VERSION 5.8 ;
BUSBITCHARS "[]" ;
DIVIDERCHAR "/" ;
UNITS
    DATABASE MICRONS 1000 ;
END UNITS

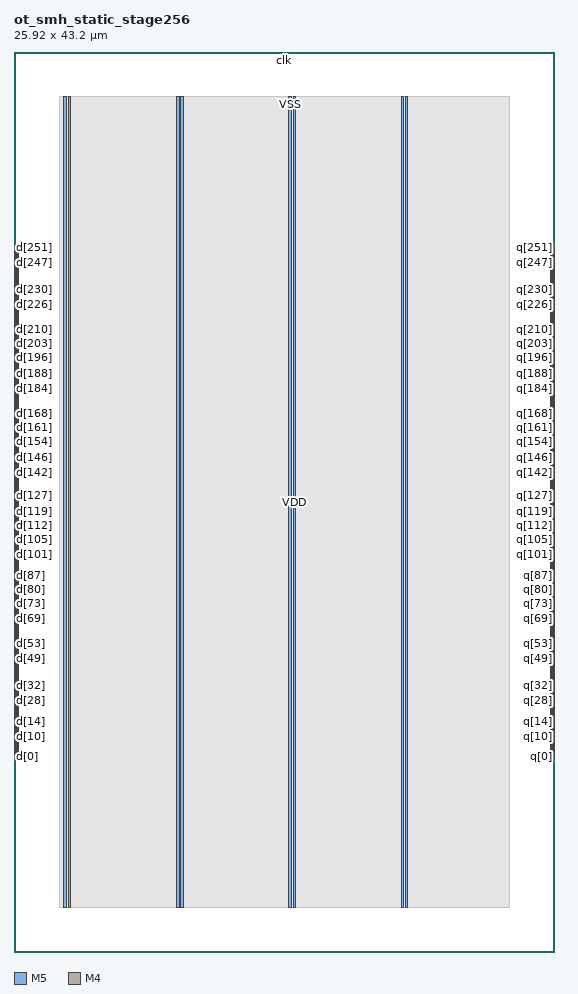
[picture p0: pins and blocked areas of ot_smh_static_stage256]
MACRO ot_smh_static_stage256
  FOREIGN ot_smh_static_stage256 0 0 ;
  CLASS BLOCK ;
  SIZE 25.92 BY 43.2 ;
  PIN clk
    DIRECTION INPUT ;
    USE SIGNAL ;
    PORT
      LAYER M5 ;
        RECT  12.96 43.008 12.984 43.2 ;
    END
  END clk
  PIN d[0]
    DIRECTION INPUT ;
    USE SIGNAL ;
    PORT
      LAYER M4 ;
        RECT  0 9.36 0.192 9.384 ;
    END
  END d[0]
  PIN d[100]
    DIRECTION INPUT ;
    USE SIGNAL ;
    PORT
      LAYER M4 ;
        RECT  0 18.96 0.192 18.984 ;
    END
  END d[100]
  PIN d[101]
    DIRECTION INPUT ;
    USE SIGNAL ;
    PORT
      LAYER M4 ;
        RECT  0 19.056 0.192 19.08 ;
    END
  END d[101]
  PIN d[102]
    DIRECTION INPUT ;
    USE SIGNAL ;
    PORT
      LAYER M4 ;
        RECT  0 19.152 0.192 19.176 ;
    END
  END d[102]
  PIN d[103]
    DIRECTION INPUT ;
    USE SIGNAL ;
    PORT
      LAYER M4 ;
        RECT  0 19.248 0.192 19.272 ;
    END
  END d[103]
  PIN d[104]
    DIRECTION INPUT ;
    USE SIGNAL ;
    PORT
      LAYER M4 ;
        RECT  0 19.344 0.192 19.368 ;
    END
  END d[104]
  PIN d[105]
    DIRECTION INPUT ;
    USE SIGNAL ;
    PORT
      LAYER M4 ;
        RECT  0 19.44 0.192 19.464 ;
    END
  END d[105]
  PIN d[106]
    DIRECTION INPUT ;
    USE SIGNAL ;
    PORT
      LAYER M4 ;
        RECT  0 19.536 0.192 19.56 ;
    END
  END d[106]
  PIN d[107]
    DIRECTION INPUT ;
    USE SIGNAL ;
    PORT
      LAYER M4 ;
        RECT  0 19.632 0.192 19.656 ;
    END
  END d[107]
  PIN d[108]
    DIRECTION INPUT ;
    USE SIGNAL ;
    PORT
      LAYER M4 ;
        RECT  0 19.728 0.192 19.752 ;
    END
  END d[108]
  PIN d[109]
    DIRECTION INPUT ;
    USE SIGNAL ;
    PORT
      LAYER M4 ;
        RECT  0 19.824 0.192 19.848 ;
    END
  END d[109]
  PIN d[10]
    DIRECTION INPUT ;
    USE SIGNAL ;
    PORT
      LAYER M4 ;
        RECT  0 10.32 0.192 10.344 ;
    END
  END d[10]
  PIN d[110]
    DIRECTION INPUT ;
    USE SIGNAL ;
    PORT
      LAYER M4 ;
        RECT  0 19.92 0.192 19.944 ;
    END
  END d[110]
  PIN d[111]
    DIRECTION INPUT ;
    USE SIGNAL ;
    PORT
      LAYER M4 ;
        RECT  0 20.016 0.192 20.04 ;
    END
  END d[111]
  PIN d[112]
    DIRECTION INPUT ;
    USE SIGNAL ;
    PORT
      LAYER M4 ;
        RECT  0 20.112 0.192 20.136 ;
    END
  END d[112]
  PIN d[113]
    DIRECTION INPUT ;
    USE SIGNAL ;
    PORT
      LAYER M4 ;
        RECT  0 20.208 0.192 20.232 ;
    END
  END d[113]
  PIN d[114]
    DIRECTION INPUT ;
    USE SIGNAL ;
    PORT
      LAYER M4 ;
        RECT  0 20.304 0.192 20.328 ;
    END
  END d[114]
  PIN d[115]
    DIRECTION INPUT ;
    USE SIGNAL ;
    PORT
      LAYER M4 ;
        RECT  0 20.4 0.192 20.424 ;
    END
  END d[115]
  PIN d[116]
    DIRECTION INPUT ;
    USE SIGNAL ;
    PORT
      LAYER M4 ;
        RECT  0 20.496 0.192 20.52 ;
    END
  END d[116]
  PIN d[117]
    DIRECTION INPUT ;
    USE SIGNAL ;
    PORT
      LAYER M4 ;
        RECT  0 20.592 0.192 20.616 ;
    END
  END d[117]
  PIN d[118]
    DIRECTION INPUT ;
    USE SIGNAL ;
    PORT
      LAYER M4 ;
        RECT  0 20.688 0.192 20.712 ;
    END
  END d[118]
  PIN d[119]
    DIRECTION INPUT ;
    USE SIGNAL ;
    PORT
      LAYER M4 ;
        RECT  0 20.784 0.192 20.808 ;
    END
  END d[119]
  PIN d[11]
    DIRECTION INPUT ;
    USE SIGNAL ;
    PORT
      LAYER M4 ;
        RECT  0 10.416 0.192 10.44 ;
    END
  END d[11]
  PIN d[120]
    DIRECTION INPUT ;
    USE SIGNAL ;
    PORT
      LAYER M4 ;
        RECT  0 20.88 0.192 20.904 ;
    END
  END d[120]
  PIN d[121]
    DIRECTION INPUT ;
    USE SIGNAL ;
    PORT
      LAYER M4 ;
        RECT  0 20.976 0.192 21 ;
    END
  END d[121]
  PIN d[122]
    DIRECTION INPUT ;
    USE SIGNAL ;
    PORT
      LAYER M4 ;
        RECT  0 21.072 0.192 21.096 ;
    END
  END d[122]
  PIN d[123]
    DIRECTION INPUT ;
    USE SIGNAL ;
    PORT
      LAYER M4 ;
        RECT  0 21.168 0.192 21.192 ;
    END
  END d[123]
  PIN d[124]
    DIRECTION INPUT ;
    USE SIGNAL ;
    PORT
      LAYER M4 ;
        RECT  0 21.264 0.192 21.288 ;
    END
  END d[124]
  PIN d[125]
    DIRECTION INPUT ;
    USE SIGNAL ;
    PORT
      LAYER M4 ;
        RECT  0 21.36 0.192 21.384 ;
    END
  END d[125]
  PIN d[126]
    DIRECTION INPUT ;
    USE SIGNAL ;
    PORT
      LAYER M4 ;
        RECT  0 21.456 0.192 21.48 ;
    END
  END d[126]
  PIN d[127]
    DIRECTION INPUT ;
    USE SIGNAL ;
    PORT
      LAYER M4 ;
        RECT  0 21.552 0.192 21.576 ;
    END
  END d[127]
  PIN d[128]
    DIRECTION INPUT ;
    USE SIGNAL ;
    PORT
      LAYER M4 ;
        RECT  0 21.648 0.192 21.672 ;
    END
  END d[128]
  PIN d[129]
    DIRECTION INPUT ;
    USE SIGNAL ;
    PORT
      LAYER M4 ;
        RECT  0 21.744 0.192 21.768 ;
    END
  END d[129]
  PIN d[12]
    DIRECTION INPUT ;
    USE SIGNAL ;
    PORT
      LAYER M4 ;
        RECT  0 10.512 0.192 10.536 ;
    END
  END d[12]
  PIN d[130]
    DIRECTION INPUT ;
    USE SIGNAL ;
    PORT
      LAYER M4 ;
        RECT  0 21.84 0.192 21.864 ;
    END
  END d[130]
  PIN d[131]
    DIRECTION INPUT ;
    USE SIGNAL ;
    PORT
      LAYER M4 ;
        RECT  0 21.936 0.192 21.96 ;
    END
  END d[131]
  PIN d[132]
    DIRECTION INPUT ;
    USE SIGNAL ;
    PORT
      LAYER M4 ;
        RECT  0 22.032 0.192 22.056 ;
    END
  END d[132]
  PIN d[133]
    DIRECTION INPUT ;
    USE SIGNAL ;
    PORT
      LAYER M4 ;
        RECT  0 22.128 0.192 22.152 ;
    END
  END d[133]
  PIN d[134]
    DIRECTION INPUT ;
    USE SIGNAL ;
    PORT
      LAYER M4 ;
        RECT  0 22.224 0.192 22.248 ;
    END
  END d[134]
  PIN d[135]
    DIRECTION INPUT ;
    USE SIGNAL ;
    PORT
      LAYER M4 ;
        RECT  0 22.32 0.192 22.344 ;
    END
  END d[135]
  PIN d[136]
    DIRECTION INPUT ;
    USE SIGNAL ;
    PORT
      LAYER M4 ;
        RECT  0 22.416 0.192 22.44 ;
    END
  END d[136]
  PIN d[137]
    DIRECTION INPUT ;
    USE SIGNAL ;
    PORT
      LAYER M4 ;
        RECT  0 22.512 0.192 22.536 ;
    END
  END d[137]
  PIN d[138]
    DIRECTION INPUT ;
    USE SIGNAL ;
    PORT
      LAYER M4 ;
        RECT  0 22.608 0.192 22.632 ;
    END
  END d[138]
  PIN d[139]
    DIRECTION INPUT ;
    USE SIGNAL ;
    PORT
      LAYER M4 ;
        RECT  0 22.704 0.192 22.728 ;
    END
  END d[139]
  PIN d[13]
    DIRECTION INPUT ;
    USE SIGNAL ;
    PORT
      LAYER M4 ;
        RECT  0 10.608 0.192 10.632 ;
    END
  END d[13]
  PIN d[140]
    DIRECTION INPUT ;
    USE SIGNAL ;
    PORT
      LAYER M4 ;
        RECT  0 22.8 0.192 22.824 ;
    END
  END d[140]
  PIN d[141]
    DIRECTION INPUT ;
    USE SIGNAL ;
    PORT
      LAYER M4 ;
        RECT  0 22.896 0.192 22.92 ;
    END
  END d[141]
  PIN d[142]
    DIRECTION INPUT ;
    USE SIGNAL ;
    PORT
      LAYER M4 ;
        RECT  0 22.992 0.192 23.016 ;
    END
  END d[142]
  PIN d[143]
    DIRECTION INPUT ;
    USE SIGNAL ;
    PORT
      LAYER M4 ;
        RECT  0 23.088 0.192 23.112 ;
    END
  END d[143]
  PIN d[144]
    DIRECTION INPUT ;
    USE SIGNAL ;
    PORT
      LAYER M4 ;
        RECT  0 23.184 0.192 23.208 ;
    END
  END d[144]
  PIN d[145]
    DIRECTION INPUT ;
    USE SIGNAL ;
    PORT
      LAYER M4 ;
        RECT  0 23.28 0.192 23.304 ;
    END
  END d[145]
  PIN d[146]
    DIRECTION INPUT ;
    USE SIGNAL ;
    PORT
      LAYER M4 ;
        RECT  0 23.376 0.192 23.4 ;
    END
  END d[146]
  PIN d[147]
    DIRECTION INPUT ;
    USE SIGNAL ;
    PORT
      LAYER M4 ;
        RECT  0 23.472 0.192 23.496 ;
    END
  END d[147]
  PIN d[148]
    DIRECTION INPUT ;
    USE SIGNAL ;
    PORT
      LAYER M4 ;
        RECT  0 23.568 0.192 23.592 ;
    END
  END d[148]
  PIN d[149]
    DIRECTION INPUT ;
    USE SIGNAL ;
    PORT
      LAYER M4 ;
        RECT  0 23.664 0.192 23.688 ;
    END
  END d[149]
  PIN d[14]
    DIRECTION INPUT ;
    USE SIGNAL ;
    PORT
      LAYER M4 ;
        RECT  0 10.704 0.192 10.728 ;
    END
  END d[14]
  PIN d[150]
    DIRECTION INPUT ;
    USE SIGNAL ;
    PORT
      LAYER M4 ;
        RECT  0 23.76 0.192 23.784 ;
    END
  END d[150]
  PIN d[151]
    DIRECTION INPUT ;
    USE SIGNAL ;
    PORT
      LAYER M4 ;
        RECT  0 23.856 0.192 23.88 ;
    END
  END d[151]
  PIN d[152]
    DIRECTION INPUT ;
    USE SIGNAL ;
    PORT
      LAYER M4 ;
        RECT  0 23.952 0.192 23.976 ;
    END
  END d[152]
  PIN d[153]
    DIRECTION INPUT ;
    USE SIGNAL ;
    PORT
      LAYER M4 ;
        RECT  0 24.048 0.192 24.072 ;
    END
  END d[153]
  PIN d[154]
    DIRECTION INPUT ;
    USE SIGNAL ;
    PORT
      LAYER M4 ;
        RECT  0 24.144 0.192 24.168 ;
    END
  END d[154]
  PIN d[155]
    DIRECTION INPUT ;
    USE SIGNAL ;
    PORT
      LAYER M4 ;
        RECT  0 24.24 0.192 24.264 ;
    END
  END d[155]
  PIN d[156]
    DIRECTION INPUT ;
    USE SIGNAL ;
    PORT
      LAYER M4 ;
        RECT  0 24.336 0.192 24.36 ;
    END
  END d[156]
  PIN d[157]
    DIRECTION INPUT ;
    USE SIGNAL ;
    PORT
      LAYER M4 ;
        RECT  0 24.432 0.192 24.456 ;
    END
  END d[157]
  PIN d[158]
    DIRECTION INPUT ;
    USE SIGNAL ;
    PORT
      LAYER M4 ;
        RECT  0 24.528 0.192 24.552 ;
    END
  END d[158]
  PIN d[159]
    DIRECTION INPUT ;
    USE SIGNAL ;
    PORT
      LAYER M4 ;
        RECT  0 24.624 0.192 24.648 ;
    END
  END d[159]
  PIN d[15]
    DIRECTION INPUT ;
    USE SIGNAL ;
    PORT
      LAYER M4 ;
        RECT  0 10.8 0.192 10.824 ;
    END
  END d[15]
  PIN d[160]
    DIRECTION INPUT ;
    USE SIGNAL ;
    PORT
      LAYER M4 ;
        RECT  0 24.72 0.192 24.744 ;
    END
  END d[160]
  PIN d[161]
    DIRECTION INPUT ;
    USE SIGNAL ;
    PORT
      LAYER M4 ;
        RECT  0 24.816 0.192 24.84 ;
    END
  END d[161]
  PIN d[162]
    DIRECTION INPUT ;
    USE SIGNAL ;
    PORT
      LAYER M4 ;
        RECT  0 24.912 0.192 24.936 ;
    END
  END d[162]
  PIN d[163]
    DIRECTION INPUT ;
    USE SIGNAL ;
    PORT
      LAYER M4 ;
        RECT  0 25.008 0.192 25.032 ;
    END
  END d[163]
  PIN d[164]
    DIRECTION INPUT ;
    USE SIGNAL ;
    PORT
      LAYER M4 ;
        RECT  0 25.104 0.192 25.128 ;
    END
  END d[164]
  PIN d[165]
    DIRECTION INPUT ;
    USE SIGNAL ;
    PORT
      LAYER M4 ;
        RECT  0 25.2 0.192 25.224 ;
    END
  END d[165]
  PIN d[166]
    DIRECTION INPUT ;
    USE SIGNAL ;
    PORT
      LAYER M4 ;
        RECT  0 25.296 0.192 25.32 ;
    END
  END d[166]
  PIN d[167]
    DIRECTION INPUT ;
    USE SIGNAL ;
    PORT
      LAYER M4 ;
        RECT  0 25.392 0.192 25.416 ;
    END
  END d[167]
  PIN d[168]
    DIRECTION INPUT ;
    USE SIGNAL ;
    PORT
      LAYER M4 ;
        RECT  0 25.488 0.192 25.512 ;
    END
  END d[168]
  PIN d[169]
    DIRECTION INPUT ;
    USE SIGNAL ;
    PORT
      LAYER M4 ;
        RECT  0 25.584 0.192 25.608 ;
    END
  END d[169]
  PIN d[16]
    DIRECTION INPUT ;
    USE SIGNAL ;
    PORT
      LAYER M4 ;
        RECT  0 10.896 0.192 10.92 ;
    END
  END d[16]
  PIN d[170]
    DIRECTION INPUT ;
    USE SIGNAL ;
    PORT
      LAYER M4 ;
        RECT  0 25.68 0.192 25.704 ;
    END
  END d[170]
  PIN d[171]
    DIRECTION INPUT ;
    USE SIGNAL ;
    PORT
      LAYER M4 ;
        RECT  0 25.776 0.192 25.8 ;
    END
  END d[171]
  PIN d[172]
    DIRECTION INPUT ;
    USE SIGNAL ;
    PORT
      LAYER M4 ;
        RECT  0 25.872 0.192 25.896 ;
    END
  END d[172]
  PIN d[173]
    DIRECTION INPUT ;
    USE SIGNAL ;
    PORT
      LAYER M4 ;
        RECT  0 25.968 0.192 25.992 ;
    END
  END d[173]
  PIN d[174]
    DIRECTION INPUT ;
    USE SIGNAL ;
    PORT
      LAYER M4 ;
        RECT  0 26.064 0.192 26.088 ;
    END
  END d[174]
  PIN d[175]
    DIRECTION INPUT ;
    USE SIGNAL ;
    PORT
      LAYER M4 ;
        RECT  0 26.16 0.192 26.184 ;
    END
  END d[175]
  PIN d[176]
    DIRECTION INPUT ;
    USE SIGNAL ;
    PORT
      LAYER M4 ;
        RECT  0 26.256 0.192 26.28 ;
    END
  END d[176]
  PIN d[177]
    DIRECTION INPUT ;
    USE SIGNAL ;
    PORT
      LAYER M4 ;
        RECT  0 26.352 0.192 26.376 ;
    END
  END d[177]
  PIN d[178]
    DIRECTION INPUT ;
    USE SIGNAL ;
    PORT
      LAYER M4 ;
        RECT  0 26.448 0.192 26.472 ;
    END
  END d[178]
  PIN d[179]
    DIRECTION INPUT ;
    USE SIGNAL ;
    PORT
      LAYER M4 ;
        RECT  0 26.544 0.192 26.568 ;
    END
  END d[179]
  PIN d[17]
    DIRECTION INPUT ;
    USE SIGNAL ;
    PORT
      LAYER M4 ;
        RECT  0 10.992 0.192 11.016 ;
    END
  END d[17]
  PIN d[180]
    DIRECTION INPUT ;
    USE SIGNAL ;
    PORT
      LAYER M4 ;
        RECT  0 26.64 0.192 26.664 ;
    END
  END d[180]
  PIN d[181]
    DIRECTION INPUT ;
    USE SIGNAL ;
    PORT
      LAYER M4 ;
        RECT  0 26.736 0.192 26.76 ;
    END
  END d[181]
  PIN d[182]
    DIRECTION INPUT ;
    USE SIGNAL ;
    PORT
      LAYER M4 ;
        RECT  0 26.832 0.192 26.856 ;
    END
  END d[182]
  PIN d[183]
    DIRECTION INPUT ;
    USE SIGNAL ;
    PORT
      LAYER M4 ;
        RECT  0 26.928 0.192 26.952 ;
    END
  END d[183]
  PIN d[184]
    DIRECTION INPUT ;
    USE SIGNAL ;
    PORT
      LAYER M4 ;
        RECT  0 27.024 0.192 27.048 ;
    END
  END d[184]
  PIN d[185]
    DIRECTION INPUT ;
    USE SIGNAL ;
    PORT
      LAYER M4 ;
        RECT  0 27.12 0.192 27.144 ;
    END
  END d[185]
  PIN d[186]
    DIRECTION INPUT ;
    USE SIGNAL ;
    PORT
      LAYER M4 ;
        RECT  0 27.216 0.192 27.24 ;
    END
  END d[186]
  PIN d[187]
    DIRECTION INPUT ;
    USE SIGNAL ;
    PORT
      LAYER M4 ;
        RECT  0 27.312 0.192 27.336 ;
    END
  END d[187]
  PIN d[188]
    DIRECTION INPUT ;
    USE SIGNAL ;
    PORT
      LAYER M4 ;
        RECT  0 27.408 0.192 27.432 ;
    END
  END d[188]
  PIN d[189]
    DIRECTION INPUT ;
    USE SIGNAL ;
    PORT
      LAYER M4 ;
        RECT  0 27.504 0.192 27.528 ;
    END
  END d[189]
  PIN d[18]
    DIRECTION INPUT ;
    USE SIGNAL ;
    PORT
      LAYER M4 ;
        RECT  0 11.088 0.192 11.112 ;
    END
  END d[18]
  PIN d[190]
    DIRECTION INPUT ;
    USE SIGNAL ;
    PORT
      LAYER M4 ;
        RECT  0 27.6 0.192 27.624 ;
    END
  END d[190]
  PIN d[191]
    DIRECTION INPUT ;
    USE SIGNAL ;
    PORT
      LAYER M4 ;
        RECT  0 27.696 0.192 27.72 ;
    END
  END d[191]
  PIN d[192]
    DIRECTION INPUT ;
    USE SIGNAL ;
    PORT
      LAYER M4 ;
        RECT  0 27.792 0.192 27.816 ;
    END
  END d[192]
  PIN d[193]
    DIRECTION INPUT ;
    USE SIGNAL ;
    PORT
      LAYER M4 ;
        RECT  0 27.888 0.192 27.912 ;
    END
  END d[193]
  PIN d[194]
    DIRECTION INPUT ;
    USE SIGNAL ;
    PORT
      LAYER M4 ;
        RECT  0 27.984 0.192 28.008 ;
    END
  END d[194]
  PIN d[195]
    DIRECTION INPUT ;
    USE SIGNAL ;
    PORT
      LAYER M4 ;
        RECT  0 28.08 0.192 28.104 ;
    END
  END d[195]
  PIN d[196]
    DIRECTION INPUT ;
    USE SIGNAL ;
    PORT
      LAYER M4 ;
        RECT  0 28.176 0.192 28.2 ;
    END
  END d[196]
  PIN d[197]
    DIRECTION INPUT ;
    USE SIGNAL ;
    PORT
      LAYER M4 ;
        RECT  0 28.272 0.192 28.296 ;
    END
  END d[197]
  PIN d[198]
    DIRECTION INPUT ;
    USE SIGNAL ;
    PORT
      LAYER M4 ;
        RECT  0 28.368 0.192 28.392 ;
    END
  END d[198]
  PIN d[199]
    DIRECTION INPUT ;
    USE SIGNAL ;
    PORT
      LAYER M4 ;
        RECT  0 28.464 0.192 28.488 ;
    END
  END d[199]
  PIN d[19]
    DIRECTION INPUT ;
    USE SIGNAL ;
    PORT
      LAYER M4 ;
        RECT  0 11.184 0.192 11.208 ;
    END
  END d[19]
  PIN d[1]
    DIRECTION INPUT ;
    USE SIGNAL ;
    PORT
      LAYER M4 ;
        RECT  0 9.456 0.192 9.48 ;
    END
  END d[1]
  PIN d[200]
    DIRECTION INPUT ;
    USE SIGNAL ;
    PORT
      LAYER M4 ;
        RECT  0 28.56 0.192 28.584 ;
    END
  END d[200]
  PIN d[201]
    DIRECTION INPUT ;
    USE SIGNAL ;
    PORT
      LAYER M4 ;
        RECT  0 28.656 0.192 28.68 ;
    END
  END d[201]
  PIN d[202]
    DIRECTION INPUT ;
    USE SIGNAL ;
    PORT
      LAYER M4 ;
        RECT  0 28.752 0.192 28.776 ;
    END
  END d[202]
  PIN d[203]
    DIRECTION INPUT ;
    USE SIGNAL ;
    PORT
      LAYER M4 ;
        RECT  0 28.848 0.192 28.872 ;
    END
  END d[203]
  PIN d[204]
    DIRECTION INPUT ;
    USE SIGNAL ;
    PORT
      LAYER M4 ;
        RECT  0 28.944 0.192 28.968 ;
    END
  END d[204]
  PIN d[205]
    DIRECTION INPUT ;
    USE SIGNAL ;
    PORT
      LAYER M4 ;
        RECT  0 29.04 0.192 29.064 ;
    END
  END d[205]
  PIN d[206]
    DIRECTION INPUT ;
    USE SIGNAL ;
    PORT
      LAYER M4 ;
        RECT  0 29.136 0.192 29.16 ;
    END
  END d[206]
  PIN d[207]
    DIRECTION INPUT ;
    USE SIGNAL ;
    PORT
      LAYER M4 ;
        RECT  0 29.232 0.192 29.256 ;
    END
  END d[207]
  PIN d[208]
    DIRECTION INPUT ;
    USE SIGNAL ;
    PORT
      LAYER M4 ;
        RECT  0 29.328 0.192 29.352 ;
    END
  END d[208]
  PIN d[209]
    DIRECTION INPUT ;
    USE SIGNAL ;
    PORT
      LAYER M4 ;
        RECT  0 29.424 0.192 29.448 ;
    END
  END d[209]
  PIN d[20]
    DIRECTION INPUT ;
    USE SIGNAL ;
    PORT
      LAYER M4 ;
        RECT  0 11.28 0.192 11.304 ;
    END
  END d[20]
  PIN d[210]
    DIRECTION INPUT ;
    USE SIGNAL ;
    PORT
      LAYER M4 ;
        RECT  0 29.52 0.192 29.544 ;
    END
  END d[210]
  PIN d[211]
    DIRECTION INPUT ;
    USE SIGNAL ;
    PORT
      LAYER M4 ;
        RECT  0 29.616 0.192 29.64 ;
    END
  END d[211]
  PIN d[212]
    DIRECTION INPUT ;
    USE SIGNAL ;
    PORT
      LAYER M4 ;
        RECT  0 29.712 0.192 29.736 ;
    END
  END d[212]
  PIN d[213]
    DIRECTION INPUT ;
    USE SIGNAL ;
    PORT
      LAYER M4 ;
        RECT  0 29.808 0.192 29.832 ;
    END
  END d[213]
  PIN d[214]
    DIRECTION INPUT ;
    USE SIGNAL ;
    PORT
      LAYER M4 ;
        RECT  0 29.904 0.192 29.928 ;
    END
  END d[214]
  PIN d[215]
    DIRECTION INPUT ;
    USE SIGNAL ;
    PORT
      LAYER M4 ;
        RECT  0 30 0.192 30.024 ;
    END
  END d[215]
  PIN d[216]
    DIRECTION INPUT ;
    USE SIGNAL ;
    PORT
      LAYER M4 ;
        RECT  0 30.096 0.192 30.12 ;
    END
  END d[216]
  PIN d[217]
    DIRECTION INPUT ;
    USE SIGNAL ;
    PORT
      LAYER M4 ;
        RECT  0 30.192 0.192 30.216 ;
    END
  END d[217]
  PIN d[218]
    DIRECTION INPUT ;
    USE SIGNAL ;
    PORT
      LAYER M4 ;
        RECT  0 30.288 0.192 30.312 ;
    END
  END d[218]
  PIN d[219]
    DIRECTION INPUT ;
    USE SIGNAL ;
    PORT
      LAYER M4 ;
        RECT  0 30.384 0.192 30.408 ;
    END
  END d[219]
  PIN d[21]
    DIRECTION INPUT ;
    USE SIGNAL ;
    PORT
      LAYER M4 ;
        RECT  0 11.376 0.192 11.4 ;
    END
  END d[21]
  PIN d[220]
    DIRECTION INPUT ;
    USE SIGNAL ;
    PORT
      LAYER M4 ;
        RECT  0 30.48 0.192 30.504 ;
    END
  END d[220]
  PIN d[221]
    DIRECTION INPUT ;
    USE SIGNAL ;
    PORT
      LAYER M4 ;
        RECT  0 30.576 0.192 30.6 ;
    END
  END d[221]
  PIN d[222]
    DIRECTION INPUT ;
    USE SIGNAL ;
    PORT
      LAYER M4 ;
        RECT  0 30.672 0.192 30.696 ;
    END
  END d[222]
  PIN d[223]
    DIRECTION INPUT ;
    USE SIGNAL ;
    PORT
      LAYER M4 ;
        RECT  0 30.768 0.192 30.792 ;
    END
  END d[223]
  PIN d[224]
    DIRECTION INPUT ;
    USE SIGNAL ;
    PORT
      LAYER M4 ;
        RECT  0 30.864 0.192 30.888 ;
    END
  END d[224]
  PIN d[225]
    DIRECTION INPUT ;
    USE SIGNAL ;
    PORT
      LAYER M4 ;
        RECT  0 30.96 0.192 30.984 ;
    END
  END d[225]
  PIN d[226]
    DIRECTION INPUT ;
    USE SIGNAL ;
    PORT
      LAYER M4 ;
        RECT  0 31.056 0.192 31.08 ;
    END
  END d[226]
  PIN d[227]
    DIRECTION INPUT ;
    USE SIGNAL ;
    PORT
      LAYER M4 ;
        RECT  0 31.152 0.192 31.176 ;
    END
  END d[227]
  PIN d[228]
    DIRECTION INPUT ;
    USE SIGNAL ;
    PORT
      LAYER M4 ;
        RECT  0 31.248 0.192 31.272 ;
    END
  END d[228]
  PIN d[229]
    DIRECTION INPUT ;
    USE SIGNAL ;
    PORT
      LAYER M4 ;
        RECT  0 31.344 0.192 31.368 ;
    END
  END d[229]
  PIN d[22]
    DIRECTION INPUT ;
    USE SIGNAL ;
    PORT
      LAYER M4 ;
        RECT  0 11.472 0.192 11.496 ;
    END
  END d[22]
  PIN d[230]
    DIRECTION INPUT ;
    USE SIGNAL ;
    PORT
      LAYER M4 ;
        RECT  0 31.44 0.192 31.464 ;
    END
  END d[230]
  PIN d[231]
    DIRECTION INPUT ;
    USE SIGNAL ;
    PORT
      LAYER M4 ;
        RECT  0 31.536 0.192 31.56 ;
    END
  END d[231]
  PIN d[232]
    DIRECTION INPUT ;
    USE SIGNAL ;
    PORT
      LAYER M4 ;
        RECT  0 31.632 0.192 31.656 ;
    END
  END d[232]
  PIN d[233]
    DIRECTION INPUT ;
    USE SIGNAL ;
    PORT
      LAYER M4 ;
        RECT  0 31.728 0.192 31.752 ;
    END
  END d[233]
  PIN d[234]
    DIRECTION INPUT ;
    USE SIGNAL ;
    PORT
      LAYER M4 ;
        RECT  0 31.824 0.192 31.848 ;
    END
  END d[234]
  PIN d[235]
    DIRECTION INPUT ;
    USE SIGNAL ;
    PORT
      LAYER M4 ;
        RECT  0 31.92 0.192 31.944 ;
    END
  END d[235]
  PIN d[236]
    DIRECTION INPUT ;
    USE SIGNAL ;
    PORT
      LAYER M4 ;
        RECT  0 32.016 0.192 32.04 ;
    END
  END d[236]
  PIN d[237]
    DIRECTION INPUT ;
    USE SIGNAL ;
    PORT
      LAYER M4 ;
        RECT  0 32.112 0.192 32.136 ;
    END
  END d[237]
  PIN d[238]
    DIRECTION INPUT ;
    USE SIGNAL ;
    PORT
      LAYER M4 ;
        RECT  0 32.208 0.192 32.232 ;
    END
  END d[238]
  PIN d[239]
    DIRECTION INPUT ;
    USE SIGNAL ;
    PORT
      LAYER M4 ;
        RECT  0 32.304 0.192 32.328 ;
    END
  END d[239]
  PIN d[23]
    DIRECTION INPUT ;
    USE SIGNAL ;
    PORT
      LAYER M4 ;
        RECT  0 11.568 0.192 11.592 ;
    END
  END d[23]
  PIN d[240]
    DIRECTION INPUT ;
    USE SIGNAL ;
    PORT
      LAYER M4 ;
        RECT  0 32.4 0.192 32.424 ;
    END
  END d[240]
  PIN d[241]
    DIRECTION INPUT ;
    USE SIGNAL ;
    PORT
      LAYER M4 ;
        RECT  0 32.496 0.192 32.52 ;
    END
  END d[241]
  PIN d[242]
    DIRECTION INPUT ;
    USE SIGNAL ;
    PORT
      LAYER M4 ;
        RECT  0 32.592 0.192 32.616 ;
    END
  END d[242]
  PIN d[243]
    DIRECTION INPUT ;
    USE SIGNAL ;
    PORT
      LAYER M4 ;
        RECT  0 32.688 0.192 32.712 ;
    END
  END d[243]
  PIN d[244]
    DIRECTION INPUT ;
    USE SIGNAL ;
    PORT
      LAYER M4 ;
        RECT  0 32.784 0.192 32.808 ;
    END
  END d[244]
  PIN d[245]
    DIRECTION INPUT ;
    USE SIGNAL ;
    PORT
      LAYER M4 ;
        RECT  0 32.88 0.192 32.904 ;
    END
  END d[245]
  PIN d[246]
    DIRECTION INPUT ;
    USE SIGNAL ;
    PORT
      LAYER M4 ;
        RECT  0 32.976 0.192 33 ;
    END
  END d[246]
  PIN d[247]
    DIRECTION INPUT ;
    USE SIGNAL ;
    PORT
      LAYER M4 ;
        RECT  0 33.072 0.192 33.096 ;
    END
  END d[247]
  PIN d[248]
    DIRECTION INPUT ;
    USE SIGNAL ;
    PORT
      LAYER M4 ;
        RECT  0 33.168 0.192 33.192 ;
    END
  END d[248]
  PIN d[249]
    DIRECTION INPUT ;
    USE SIGNAL ;
    PORT
      LAYER M4 ;
        RECT  0 33.264 0.192 33.288 ;
    END
  END d[249]
  PIN d[24]
    DIRECTION INPUT ;
    USE SIGNAL ;
    PORT
      LAYER M4 ;
        RECT  0 11.664 0.192 11.688 ;
    END
  END d[24]
  PIN d[250]
    DIRECTION INPUT ;
    USE SIGNAL ;
    PORT
      LAYER M4 ;
        RECT  0 33.36 0.192 33.384 ;
    END
  END d[250]
  PIN d[251]
    DIRECTION INPUT ;
    USE SIGNAL ;
    PORT
      LAYER M4 ;
        RECT  0 33.456 0.192 33.48 ;
    END
  END d[251]
  PIN d[252]
    DIRECTION INPUT ;
    USE SIGNAL ;
    PORT
      LAYER M4 ;
        RECT  0 33.552 0.192 33.576 ;
    END
  END d[252]
  PIN d[253]
    DIRECTION INPUT ;
    USE SIGNAL ;
    PORT
      LAYER M4 ;
        RECT  0 33.648 0.192 33.672 ;
    END
  END d[253]
  PIN d[254]
    DIRECTION INPUT ;
    USE SIGNAL ;
    PORT
      LAYER M4 ;
        RECT  0 33.744 0.192 33.768 ;
    END
  END d[254]
  PIN d[255]
    DIRECTION INPUT ;
    USE SIGNAL ;
    PORT
      LAYER M4 ;
        RECT  0 33.84 0.192 33.864 ;
    END
  END d[255]
  PIN d[25]
    DIRECTION INPUT ;
    USE SIGNAL ;
    PORT
      LAYER M4 ;
        RECT  0 11.76 0.192 11.784 ;
    END
  END d[25]
  PIN d[26]
    DIRECTION INPUT ;
    USE SIGNAL ;
    PORT
      LAYER M4 ;
        RECT  0 11.856 0.192 11.88 ;
    END
  END d[26]
  PIN d[27]
    DIRECTION INPUT ;
    USE SIGNAL ;
    PORT
      LAYER M4 ;
        RECT  0 11.952 0.192 11.976 ;
    END
  END d[27]
  PIN d[28]
    DIRECTION INPUT ;
    USE SIGNAL ;
    PORT
      LAYER M4 ;
        RECT  0 12.048 0.192 12.072 ;
    END
  END d[28]
  PIN d[29]
    DIRECTION INPUT ;
    USE SIGNAL ;
    PORT
      LAYER M4 ;
        RECT  0 12.144 0.192 12.168 ;
    END
  END d[29]
  PIN d[2]
    DIRECTION INPUT ;
    USE SIGNAL ;
    PORT
      LAYER M4 ;
        RECT  0 9.552 0.192 9.576 ;
    END
  END d[2]
  PIN d[30]
    DIRECTION INPUT ;
    USE SIGNAL ;
    PORT
      LAYER M4 ;
        RECT  0 12.24 0.192 12.264 ;
    END
  END d[30]
  PIN d[31]
    DIRECTION INPUT ;
    USE SIGNAL ;
    PORT
      LAYER M4 ;
        RECT  0 12.336 0.192 12.36 ;
    END
  END d[31]
  PIN d[32]
    DIRECTION INPUT ;
    USE SIGNAL ;
    PORT
      LAYER M4 ;
        RECT  0 12.432 0.192 12.456 ;
    END
  END d[32]
  PIN d[33]
    DIRECTION INPUT ;
    USE SIGNAL ;
    PORT
      LAYER M4 ;
        RECT  0 12.528 0.192 12.552 ;
    END
  END d[33]
  PIN d[34]
    DIRECTION INPUT ;
    USE SIGNAL ;
    PORT
      LAYER M4 ;
        RECT  0 12.624 0.192 12.648 ;
    END
  END d[34]
  PIN d[35]
    DIRECTION INPUT ;
    USE SIGNAL ;
    PORT
      LAYER M4 ;
        RECT  0 12.72 0.192 12.744 ;
    END
  END d[35]
  PIN d[36]
    DIRECTION INPUT ;
    USE SIGNAL ;
    PORT
      LAYER M4 ;
        RECT  0 12.816 0.192 12.84 ;
    END
  END d[36]
  PIN d[37]
    DIRECTION INPUT ;
    USE SIGNAL ;
    PORT
      LAYER M4 ;
        RECT  0 12.912 0.192 12.936 ;
    END
  END d[37]
  PIN d[38]
    DIRECTION INPUT ;
    USE SIGNAL ;
    PORT
      LAYER M4 ;
        RECT  0 13.008 0.192 13.032 ;
    END
  END d[38]
  PIN d[39]
    DIRECTION INPUT ;
    USE SIGNAL ;
    PORT
      LAYER M4 ;
        RECT  0 13.104 0.192 13.128 ;
    END
  END d[39]
  PIN d[3]
    DIRECTION INPUT ;
    USE SIGNAL ;
    PORT
      LAYER M4 ;
        RECT  0 9.648 0.192 9.672 ;
    END
  END d[3]
  PIN d[40]
    DIRECTION INPUT ;
    USE SIGNAL ;
    PORT
      LAYER M4 ;
        RECT  0 13.2 0.192 13.224 ;
    END
  END d[40]
  PIN d[41]
    DIRECTION INPUT ;
    USE SIGNAL ;
    PORT
      LAYER M4 ;
        RECT  0 13.296 0.192 13.32 ;
    END
  END d[41]
  PIN d[42]
    DIRECTION INPUT ;
    USE SIGNAL ;
    PORT
      LAYER M4 ;
        RECT  0 13.392 0.192 13.416 ;
    END
  END d[42]
  PIN d[43]
    DIRECTION INPUT ;
    USE SIGNAL ;
    PORT
      LAYER M4 ;
        RECT  0 13.488 0.192 13.512 ;
    END
  END d[43]
  PIN d[44]
    DIRECTION INPUT ;
    USE SIGNAL ;
    PORT
      LAYER M4 ;
        RECT  0 13.584 0.192 13.608 ;
    END
  END d[44]
  PIN d[45]
    DIRECTION INPUT ;
    USE SIGNAL ;
    PORT
      LAYER M4 ;
        RECT  0 13.68 0.192 13.704 ;
    END
  END d[45]
  PIN d[46]
    DIRECTION INPUT ;
    USE SIGNAL ;
    PORT
      LAYER M4 ;
        RECT  0 13.776 0.192 13.8 ;
    END
  END d[46]
  PIN d[47]
    DIRECTION INPUT ;
    USE SIGNAL ;
    PORT
      LAYER M4 ;
        RECT  0 13.872 0.192 13.896 ;
    END
  END d[47]
  PIN d[48]
    DIRECTION INPUT ;
    USE SIGNAL ;
    PORT
      LAYER M4 ;
        RECT  0 13.968 0.192 13.992 ;
    END
  END d[48]
  PIN d[49]
    DIRECTION INPUT ;
    USE SIGNAL ;
    PORT
      LAYER M4 ;
        RECT  0 14.064 0.192 14.088 ;
    END
  END d[49]
  PIN d[4]
    DIRECTION INPUT ;
    USE SIGNAL ;
    PORT
      LAYER M4 ;
        RECT  0 9.744 0.192 9.768 ;
    END
  END d[4]
  PIN d[50]
    DIRECTION INPUT ;
    USE SIGNAL ;
    PORT
      LAYER M4 ;
        RECT  0 14.16 0.192 14.184 ;
    END
  END d[50]
  PIN d[51]
    DIRECTION INPUT ;
    USE SIGNAL ;
    PORT
      LAYER M4 ;
        RECT  0 14.256 0.192 14.28 ;
    END
  END d[51]
  PIN d[52]
    DIRECTION INPUT ;
    USE SIGNAL ;
    PORT
      LAYER M4 ;
        RECT  0 14.352 0.192 14.376 ;
    END
  END d[52]
  PIN d[53]
    DIRECTION INPUT ;
    USE SIGNAL ;
    PORT
      LAYER M4 ;
        RECT  0 14.448 0.192 14.472 ;
    END
  END d[53]
  PIN d[54]
    DIRECTION INPUT ;
    USE SIGNAL ;
    PORT
      LAYER M4 ;
        RECT  0 14.544 0.192 14.568 ;
    END
  END d[54]
  PIN d[55]
    DIRECTION INPUT ;
    USE SIGNAL ;
    PORT
      LAYER M4 ;
        RECT  0 14.64 0.192 14.664 ;
    END
  END d[55]
  PIN d[56]
    DIRECTION INPUT ;
    USE SIGNAL ;
    PORT
      LAYER M4 ;
        RECT  0 14.736 0.192 14.76 ;
    END
  END d[56]
  PIN d[57]
    DIRECTION INPUT ;
    USE SIGNAL ;
    PORT
      LAYER M4 ;
        RECT  0 14.832 0.192 14.856 ;
    END
  END d[57]
  PIN d[58]
    DIRECTION INPUT ;
    USE SIGNAL ;
    PORT
      LAYER M4 ;
        RECT  0 14.928 0.192 14.952 ;
    END
  END d[58]
  PIN d[59]
    DIRECTION INPUT ;
    USE SIGNAL ;
    PORT
      LAYER M4 ;
        RECT  0 15.024 0.192 15.048 ;
    END
  END d[59]
  PIN d[5]
    DIRECTION INPUT ;
    USE SIGNAL ;
    PORT
      LAYER M4 ;
        RECT  0 9.84 0.192 9.864 ;
    END
  END d[5]
  PIN d[60]
    DIRECTION INPUT ;
    USE SIGNAL ;
    PORT
      LAYER M4 ;
        RECT  0 15.12 0.192 15.144 ;
    END
  END d[60]
  PIN d[61]
    DIRECTION INPUT ;
    USE SIGNAL ;
    PORT
      LAYER M4 ;
        RECT  0 15.216 0.192 15.24 ;
    END
  END d[61]
  PIN d[62]
    DIRECTION INPUT ;
    USE SIGNAL ;
    PORT
      LAYER M4 ;
        RECT  0 15.312 0.192 15.336 ;
    END
  END d[62]
  PIN d[63]
    DIRECTION INPUT ;
    USE SIGNAL ;
    PORT
      LAYER M4 ;
        RECT  0 15.408 0.192 15.432 ;
    END
  END d[63]
  PIN d[64]
    DIRECTION INPUT ;
    USE SIGNAL ;
    PORT
      LAYER M4 ;
        RECT  0 15.504 0.192 15.528 ;
    END
  END d[64]
  PIN d[65]
    DIRECTION INPUT ;
    USE SIGNAL ;
    PORT
      LAYER M4 ;
        RECT  0 15.6 0.192 15.624 ;
    END
  END d[65]
  PIN d[66]
    DIRECTION INPUT ;
    USE SIGNAL ;
    PORT
      LAYER M4 ;
        RECT  0 15.696 0.192 15.72 ;
    END
  END d[66]
  PIN d[67]
    DIRECTION INPUT ;
    USE SIGNAL ;
    PORT
      LAYER M4 ;
        RECT  0 15.792 0.192 15.816 ;
    END
  END d[67]
  PIN d[68]
    DIRECTION INPUT ;
    USE SIGNAL ;
    PORT
      LAYER M4 ;
        RECT  0 15.888 0.192 15.912 ;
    END
  END d[68]
  PIN d[69]
    DIRECTION INPUT ;
    USE SIGNAL ;
    PORT
      LAYER M4 ;
        RECT  0 15.984 0.192 16.008 ;
    END
  END d[69]
  PIN d[6]
    DIRECTION INPUT ;
    USE SIGNAL ;
    PORT
      LAYER M4 ;
        RECT  0 9.936 0.192 9.96 ;
    END
  END d[6]
  PIN d[70]
    DIRECTION INPUT ;
    USE SIGNAL ;
    PORT
      LAYER M4 ;
        RECT  0 16.08 0.192 16.104 ;
    END
  END d[70]
  PIN d[71]
    DIRECTION INPUT ;
    USE SIGNAL ;
    PORT
      LAYER M4 ;
        RECT  0 16.176 0.192 16.2 ;
    END
  END d[71]
  PIN d[72]
    DIRECTION INPUT ;
    USE SIGNAL ;
    PORT
      LAYER M4 ;
        RECT  0 16.272 0.192 16.296 ;
    END
  END d[72]
  PIN d[73]
    DIRECTION INPUT ;
    USE SIGNAL ;
    PORT
      LAYER M4 ;
        RECT  0 16.368 0.192 16.392 ;
    END
  END d[73]
  PIN d[74]
    DIRECTION INPUT ;
    USE SIGNAL ;
    PORT
      LAYER M4 ;
        RECT  0 16.464 0.192 16.488 ;
    END
  END d[74]
  PIN d[75]
    DIRECTION INPUT ;
    USE SIGNAL ;
    PORT
      LAYER M4 ;
        RECT  0 16.56 0.192 16.584 ;
    END
  END d[75]
  PIN d[76]
    DIRECTION INPUT ;
    USE SIGNAL ;
    PORT
      LAYER M4 ;
        RECT  0 16.656 0.192 16.68 ;
    END
  END d[76]
  PIN d[77]
    DIRECTION INPUT ;
    USE SIGNAL ;
    PORT
      LAYER M4 ;
        RECT  0 16.752 0.192 16.776 ;
    END
  END d[77]
  PIN d[78]
    DIRECTION INPUT ;
    USE SIGNAL ;
    PORT
      LAYER M4 ;
        RECT  0 16.848 0.192 16.872 ;
    END
  END d[78]
  PIN d[79]
    DIRECTION INPUT ;
    USE SIGNAL ;
    PORT
      LAYER M4 ;
        RECT  0 16.944 0.192 16.968 ;
    END
  END d[79]
  PIN d[7]
    DIRECTION INPUT ;
    USE SIGNAL ;
    PORT
      LAYER M4 ;
        RECT  0 10.032 0.192 10.056 ;
    END
  END d[7]
  PIN d[80]
    DIRECTION INPUT ;
    USE SIGNAL ;
    PORT
      LAYER M4 ;
        RECT  0 17.04 0.192 17.064 ;
    END
  END d[80]
  PIN d[81]
    DIRECTION INPUT ;
    USE SIGNAL ;
    PORT
      LAYER M4 ;
        RECT  0 17.136 0.192 17.16 ;
    END
  END d[81]
  PIN d[82]
    DIRECTION INPUT ;
    USE SIGNAL ;
    PORT
      LAYER M4 ;
        RECT  0 17.232 0.192 17.256 ;
    END
  END d[82]
  PIN d[83]
    DIRECTION INPUT ;
    USE SIGNAL ;
    PORT
      LAYER M4 ;
        RECT  0 17.328 0.192 17.352 ;
    END
  END d[83]
  PIN d[84]
    DIRECTION INPUT ;
    USE SIGNAL ;
    PORT
      LAYER M4 ;
        RECT  0 17.424 0.192 17.448 ;
    END
  END d[84]
  PIN d[85]
    DIRECTION INPUT ;
    USE SIGNAL ;
    PORT
      LAYER M4 ;
        RECT  0 17.52 0.192 17.544 ;
    END
  END d[85]
  PIN d[86]
    DIRECTION INPUT ;
    USE SIGNAL ;
    PORT
      LAYER M4 ;
        RECT  0 17.616 0.192 17.64 ;
    END
  END d[86]
  PIN d[87]
    DIRECTION INPUT ;
    USE SIGNAL ;
    PORT
      LAYER M4 ;
        RECT  0 17.712 0.192 17.736 ;
    END
  END d[87]
  PIN d[88]
    DIRECTION INPUT ;
    USE SIGNAL ;
    PORT
      LAYER M4 ;
        RECT  0 17.808 0.192 17.832 ;
    END
  END d[88]
  PIN d[89]
    DIRECTION INPUT ;
    USE SIGNAL ;
    PORT
      LAYER M4 ;
        RECT  0 17.904 0.192 17.928 ;
    END
  END d[89]
  PIN d[8]
    DIRECTION INPUT ;
    USE SIGNAL ;
    PORT
      LAYER M4 ;
        RECT  0 10.128 0.192 10.152 ;
    END
  END d[8]
  PIN d[90]
    DIRECTION INPUT ;
    USE SIGNAL ;
    PORT
      LAYER M4 ;
        RECT  0 18 0.192 18.024 ;
    END
  END d[90]
  PIN d[91]
    DIRECTION INPUT ;
    USE SIGNAL ;
    PORT
      LAYER M4 ;
        RECT  0 18.096 0.192 18.12 ;
    END
  END d[91]
  PIN d[92]
    DIRECTION INPUT ;
    USE SIGNAL ;
    PORT
      LAYER M4 ;
        RECT  0 18.192 0.192 18.216 ;
    END
  END d[92]
  PIN d[93]
    DIRECTION INPUT ;
    USE SIGNAL ;
    PORT
      LAYER M4 ;
        RECT  0 18.288 0.192 18.312 ;
    END
  END d[93]
  PIN d[94]
    DIRECTION INPUT ;
    USE SIGNAL ;
    PORT
      LAYER M4 ;
        RECT  0 18.384 0.192 18.408 ;
    END
  END d[94]
  PIN d[95]
    DIRECTION INPUT ;
    USE SIGNAL ;
    PORT
      LAYER M4 ;
        RECT  0 18.48 0.192 18.504 ;
    END
  END d[95]
  PIN d[96]
    DIRECTION INPUT ;
    USE SIGNAL ;
    PORT
      LAYER M4 ;
        RECT  0 18.576 0.192 18.6 ;
    END
  END d[96]
  PIN d[97]
    DIRECTION INPUT ;
    USE SIGNAL ;
    PORT
      LAYER M4 ;
        RECT  0 18.672 0.192 18.696 ;
    END
  END d[97]
  PIN d[98]
    DIRECTION INPUT ;
    USE SIGNAL ;
    PORT
      LAYER M4 ;
        RECT  0 18.768 0.192 18.792 ;
    END
  END d[98]
  PIN d[99]
    DIRECTION INPUT ;
    USE SIGNAL ;
    PORT
      LAYER M4 ;
        RECT  0 18.864 0.192 18.888 ;
    END
  END d[99]
  PIN d[9]
    DIRECTION INPUT ;
    USE SIGNAL ;
    PORT
      LAYER M4 ;
        RECT  0 10.224 0.192 10.248 ;
    END
  END d[9]
  PIN q[0]
    DIRECTION OUTPUT ;
    USE SIGNAL ;
    PORT
      LAYER M4 ;
        RECT  25.728 9.36 25.92 9.384 ;
    END
  END q[0]
  PIN q[100]
    DIRECTION OUTPUT ;
    USE SIGNAL ;
    PORT
      LAYER M4 ;
        RECT  25.728 18.96 25.92 18.984 ;
    END
  END q[100]
  PIN q[101]
    DIRECTION OUTPUT ;
    USE SIGNAL ;
    PORT
      LAYER M4 ;
        RECT  25.728 19.056 25.92 19.08 ;
    END
  END q[101]
  PIN q[102]
    DIRECTION OUTPUT ;
    USE SIGNAL ;
    PORT
      LAYER M4 ;
        RECT  25.728 19.152 25.92 19.176 ;
    END
  END q[102]
  PIN q[103]
    DIRECTION OUTPUT ;
    USE SIGNAL ;
    PORT
      LAYER M4 ;
        RECT  25.728 19.248 25.92 19.272 ;
    END
  END q[103]
  PIN q[104]
    DIRECTION OUTPUT ;
    USE SIGNAL ;
    PORT
      LAYER M4 ;
        RECT  25.728 19.344 25.92 19.368 ;
    END
  END q[104]
  PIN q[105]
    DIRECTION OUTPUT ;
    USE SIGNAL ;
    PORT
      LAYER M4 ;
        RECT  25.728 19.44 25.92 19.464 ;
    END
  END q[105]
  PIN q[106]
    DIRECTION OUTPUT ;
    USE SIGNAL ;
    PORT
      LAYER M4 ;
        RECT  25.728 19.536 25.92 19.56 ;
    END
  END q[106]
  PIN q[107]
    DIRECTION OUTPUT ;
    USE SIGNAL ;
    PORT
      LAYER M4 ;
        RECT  25.728 19.632 25.92 19.656 ;
    END
  END q[107]
  PIN q[108]
    DIRECTION OUTPUT ;
    USE SIGNAL ;
    PORT
      LAYER M4 ;
        RECT  25.728 19.728 25.92 19.752 ;
    END
  END q[108]
  PIN q[109]
    DIRECTION OUTPUT ;
    USE SIGNAL ;
    PORT
      LAYER M4 ;
        RECT  25.728 19.824 25.92 19.848 ;
    END
  END q[109]
  PIN q[10]
    DIRECTION OUTPUT ;
    USE SIGNAL ;
    PORT
      LAYER M4 ;
        RECT  25.728 10.32 25.92 10.344 ;
    END
  END q[10]
  PIN q[110]
    DIRECTION OUTPUT ;
    USE SIGNAL ;
    PORT
      LAYER M4 ;
        RECT  25.728 19.92 25.92 19.944 ;
    END
  END q[110]
  PIN q[111]
    DIRECTION OUTPUT ;
    USE SIGNAL ;
    PORT
      LAYER M4 ;
        RECT  25.728 20.016 25.92 20.04 ;
    END
  END q[111]
  PIN q[112]
    DIRECTION OUTPUT ;
    USE SIGNAL ;
    PORT
      LAYER M4 ;
        RECT  25.728 20.112 25.92 20.136 ;
    END
  END q[112]
  PIN q[113]
    DIRECTION OUTPUT ;
    USE SIGNAL ;
    PORT
      LAYER M4 ;
        RECT  25.728 20.208 25.92 20.232 ;
    END
  END q[113]
  PIN q[114]
    DIRECTION OUTPUT ;
    USE SIGNAL ;
    PORT
      LAYER M4 ;
        RECT  25.728 20.304 25.92 20.328 ;
    END
  END q[114]
  PIN q[115]
    DIRECTION OUTPUT ;
    USE SIGNAL ;
    PORT
      LAYER M4 ;
        RECT  25.728 20.4 25.92 20.424 ;
    END
  END q[115]
  PIN q[116]
    DIRECTION OUTPUT ;
    USE SIGNAL ;
    PORT
      LAYER M4 ;
        RECT  25.728 20.496 25.92 20.52 ;
    END
  END q[116]
  PIN q[117]
    DIRECTION OUTPUT ;
    USE SIGNAL ;
    PORT
      LAYER M4 ;
        RECT  25.728 20.592 25.92 20.616 ;
    END
  END q[117]
  PIN q[118]
    DIRECTION OUTPUT ;
    USE SIGNAL ;
    PORT
      LAYER M4 ;
        RECT  25.728 20.688 25.92 20.712 ;
    END
  END q[118]
  PIN q[119]
    DIRECTION OUTPUT ;
    USE SIGNAL ;
    PORT
      LAYER M4 ;
        RECT  25.728 20.784 25.92 20.808 ;
    END
  END q[119]
  PIN q[11]
    DIRECTION OUTPUT ;
    USE SIGNAL ;
    PORT
      LAYER M4 ;
        RECT  25.728 10.416 25.92 10.44 ;
    END
  END q[11]
  PIN q[120]
    DIRECTION OUTPUT ;
    USE SIGNAL ;
    PORT
      LAYER M4 ;
        RECT  25.728 20.88 25.92 20.904 ;
    END
  END q[120]
  PIN q[121]
    DIRECTION OUTPUT ;
    USE SIGNAL ;
    PORT
      LAYER M4 ;
        RECT  25.728 20.976 25.92 21 ;
    END
  END q[121]
  PIN q[122]
    DIRECTION OUTPUT ;
    USE SIGNAL ;
    PORT
      LAYER M4 ;
        RECT  25.728 21.072 25.92 21.096 ;
    END
  END q[122]
  PIN q[123]
    DIRECTION OUTPUT ;
    USE SIGNAL ;
    PORT
      LAYER M4 ;
        RECT  25.728 21.168 25.92 21.192 ;
    END
  END q[123]
  PIN q[124]
    DIRECTION OUTPUT ;
    USE SIGNAL ;
    PORT
      LAYER M4 ;
        RECT  25.728 21.264 25.92 21.288 ;
    END
  END q[124]
  PIN q[125]
    DIRECTION OUTPUT ;
    USE SIGNAL ;
    PORT
      LAYER M4 ;
        RECT  25.728 21.36 25.92 21.384 ;
    END
  END q[125]
  PIN q[126]
    DIRECTION OUTPUT ;
    USE SIGNAL ;
    PORT
      LAYER M4 ;
        RECT  25.728 21.456 25.92 21.48 ;
    END
  END q[126]
  PIN q[127]
    DIRECTION OUTPUT ;
    USE SIGNAL ;
    PORT
      LAYER M4 ;
        RECT  25.728 21.552 25.92 21.576 ;
    END
  END q[127]
  PIN q[128]
    DIRECTION OUTPUT ;
    USE SIGNAL ;
    PORT
      LAYER M4 ;
        RECT  25.728 21.648 25.92 21.672 ;
    END
  END q[128]
  PIN q[129]
    DIRECTION OUTPUT ;
    USE SIGNAL ;
    PORT
      LAYER M4 ;
        RECT  25.728 21.744 25.92 21.768 ;
    END
  END q[129]
  PIN q[12]
    DIRECTION OUTPUT ;
    USE SIGNAL ;
    PORT
      LAYER M4 ;
        RECT  25.728 10.512 25.92 10.536 ;
    END
  END q[12]
  PIN q[130]
    DIRECTION OUTPUT ;
    USE SIGNAL ;
    PORT
      LAYER M4 ;
        RECT  25.728 21.84 25.92 21.864 ;
    END
  END q[130]
  PIN q[131]
    DIRECTION OUTPUT ;
    USE SIGNAL ;
    PORT
      LAYER M4 ;
        RECT  25.728 21.936 25.92 21.96 ;
    END
  END q[131]
  PIN q[132]
    DIRECTION OUTPUT ;
    USE SIGNAL ;
    PORT
      LAYER M4 ;
        RECT  25.728 22.032 25.92 22.056 ;
    END
  END q[132]
  PIN q[133]
    DIRECTION OUTPUT ;
    USE SIGNAL ;
    PORT
      LAYER M4 ;
        RECT  25.728 22.128 25.92 22.152 ;
    END
  END q[133]
  PIN q[134]
    DIRECTION OUTPUT ;
    USE SIGNAL ;
    PORT
      LAYER M4 ;
        RECT  25.728 22.224 25.92 22.248 ;
    END
  END q[134]
  PIN q[135]
    DIRECTION OUTPUT ;
    USE SIGNAL ;
    PORT
      LAYER M4 ;
        RECT  25.728 22.32 25.92 22.344 ;
    END
  END q[135]
  PIN q[136]
    DIRECTION OUTPUT ;
    USE SIGNAL ;
    PORT
      LAYER M4 ;
        RECT  25.728 22.416 25.92 22.44 ;
    END
  END q[136]
  PIN q[137]
    DIRECTION OUTPUT ;
    USE SIGNAL ;
    PORT
      LAYER M4 ;
        RECT  25.728 22.512 25.92 22.536 ;
    END
  END q[137]
  PIN q[138]
    DIRECTION OUTPUT ;
    USE SIGNAL ;
    PORT
      LAYER M4 ;
        RECT  25.728 22.608 25.92 22.632 ;
    END
  END q[138]
  PIN q[139]
    DIRECTION OUTPUT ;
    USE SIGNAL ;
    PORT
      LAYER M4 ;
        RECT  25.728 22.704 25.92 22.728 ;
    END
  END q[139]
  PIN q[13]
    DIRECTION OUTPUT ;
    USE SIGNAL ;
    PORT
      LAYER M4 ;
        RECT  25.728 10.608 25.92 10.632 ;
    END
  END q[13]
  PIN q[140]
    DIRECTION OUTPUT ;
    USE SIGNAL ;
    PORT
      LAYER M4 ;
        RECT  25.728 22.8 25.92 22.824 ;
    END
  END q[140]
  PIN q[141]
    DIRECTION OUTPUT ;
    USE SIGNAL ;
    PORT
      LAYER M4 ;
        RECT  25.728 22.896 25.92 22.92 ;
    END
  END q[141]
  PIN q[142]
    DIRECTION OUTPUT ;
    USE SIGNAL ;
    PORT
      LAYER M4 ;
        RECT  25.728 22.992 25.92 23.016 ;
    END
  END q[142]
  PIN q[143]
    DIRECTION OUTPUT ;
    USE SIGNAL ;
    PORT
      LAYER M4 ;
        RECT  25.728 23.088 25.92 23.112 ;
    END
  END q[143]
  PIN q[144]
    DIRECTION OUTPUT ;
    USE SIGNAL ;
    PORT
      LAYER M4 ;
        RECT  25.728 23.184 25.92 23.208 ;
    END
  END q[144]
  PIN q[145]
    DIRECTION OUTPUT ;
    USE SIGNAL ;
    PORT
      LAYER M4 ;
        RECT  25.728 23.28 25.92 23.304 ;
    END
  END q[145]
  PIN q[146]
    DIRECTION OUTPUT ;
    USE SIGNAL ;
    PORT
      LAYER M4 ;
        RECT  25.728 23.376 25.92 23.4 ;
    END
  END q[146]
  PIN q[147]
    DIRECTION OUTPUT ;
    USE SIGNAL ;
    PORT
      LAYER M4 ;
        RECT  25.728 23.472 25.92 23.496 ;
    END
  END q[147]
  PIN q[148]
    DIRECTION OUTPUT ;
    USE SIGNAL ;
    PORT
      LAYER M4 ;
        RECT  25.728 23.568 25.92 23.592 ;
    END
  END q[148]
  PIN q[149]
    DIRECTION OUTPUT ;
    USE SIGNAL ;
    PORT
      LAYER M4 ;
        RECT  25.728 23.664 25.92 23.688 ;
    END
  END q[149]
  PIN q[14]
    DIRECTION OUTPUT ;
    USE SIGNAL ;
    PORT
      LAYER M4 ;
        RECT  25.728 10.704 25.92 10.728 ;
    END
  END q[14]
  PIN q[150]
    DIRECTION OUTPUT ;
    USE SIGNAL ;
    PORT
      LAYER M4 ;
        RECT  25.728 23.76 25.92 23.784 ;
    END
  END q[150]
  PIN q[151]
    DIRECTION OUTPUT ;
    USE SIGNAL ;
    PORT
      LAYER M4 ;
        RECT  25.728 23.856 25.92 23.88 ;
    END
  END q[151]
  PIN q[152]
    DIRECTION OUTPUT ;
    USE SIGNAL ;
    PORT
      LAYER M4 ;
        RECT  25.728 23.952 25.92 23.976 ;
    END
  END q[152]
  PIN q[153]
    DIRECTION OUTPUT ;
    USE SIGNAL ;
    PORT
      LAYER M4 ;
        RECT  25.728 24.048 25.92 24.072 ;
    END
  END q[153]
  PIN q[154]
    DIRECTION OUTPUT ;
    USE SIGNAL ;
    PORT
      LAYER M4 ;
        RECT  25.728 24.144 25.92 24.168 ;
    END
  END q[154]
  PIN q[155]
    DIRECTION OUTPUT ;
    USE SIGNAL ;
    PORT
      LAYER M4 ;
        RECT  25.728 24.24 25.92 24.264 ;
    END
  END q[155]
  PIN q[156]
    DIRECTION OUTPUT ;
    USE SIGNAL ;
    PORT
      LAYER M4 ;
        RECT  25.728 24.336 25.92 24.36 ;
    END
  END q[156]
  PIN q[157]
    DIRECTION OUTPUT ;
    USE SIGNAL ;
    PORT
      LAYER M4 ;
        RECT  25.728 24.432 25.92 24.456 ;
    END
  END q[157]
  PIN q[158]
    DIRECTION OUTPUT ;
    USE SIGNAL ;
    PORT
      LAYER M4 ;
        RECT  25.728 24.528 25.92 24.552 ;
    END
  END q[158]
  PIN q[159]
    DIRECTION OUTPUT ;
    USE SIGNAL ;
    PORT
      LAYER M4 ;
        RECT  25.728 24.624 25.92 24.648 ;
    END
  END q[159]
  PIN q[15]
    DIRECTION OUTPUT ;
    USE SIGNAL ;
    PORT
      LAYER M4 ;
        RECT  25.728 10.8 25.92 10.824 ;
    END
  END q[15]
  PIN q[160]
    DIRECTION OUTPUT ;
    USE SIGNAL ;
    PORT
      LAYER M4 ;
        RECT  25.728 24.72 25.92 24.744 ;
    END
  END q[160]
  PIN q[161]
    DIRECTION OUTPUT ;
    USE SIGNAL ;
    PORT
      LAYER M4 ;
        RECT  25.728 24.816 25.92 24.84 ;
    END
  END q[161]
  PIN q[162]
    DIRECTION OUTPUT ;
    USE SIGNAL ;
    PORT
      LAYER M4 ;
        RECT  25.728 24.912 25.92 24.936 ;
    END
  END q[162]
  PIN q[163]
    DIRECTION OUTPUT ;
    USE SIGNAL ;
    PORT
      LAYER M4 ;
        RECT  25.728 25.008 25.92 25.032 ;
    END
  END q[163]
  PIN q[164]
    DIRECTION OUTPUT ;
    USE SIGNAL ;
    PORT
      LAYER M4 ;
        RECT  25.728 25.104 25.92 25.128 ;
    END
  END q[164]
  PIN q[165]
    DIRECTION OUTPUT ;
    USE SIGNAL ;
    PORT
      LAYER M4 ;
        RECT  25.728 25.2 25.92 25.224 ;
    END
  END q[165]
  PIN q[166]
    DIRECTION OUTPUT ;
    USE SIGNAL ;
    PORT
      LAYER M4 ;
        RECT  25.728 25.296 25.92 25.32 ;
    END
  END q[166]
  PIN q[167]
    DIRECTION OUTPUT ;
    USE SIGNAL ;
    PORT
      LAYER M4 ;
        RECT  25.728 25.392 25.92 25.416 ;
    END
  END q[167]
  PIN q[168]
    DIRECTION OUTPUT ;
    USE SIGNAL ;
    PORT
      LAYER M4 ;
        RECT  25.728 25.488 25.92 25.512 ;
    END
  END q[168]
  PIN q[169]
    DIRECTION OUTPUT ;
    USE SIGNAL ;
    PORT
      LAYER M4 ;
        RECT  25.728 25.584 25.92 25.608 ;
    END
  END q[169]
  PIN q[16]
    DIRECTION OUTPUT ;
    USE SIGNAL ;
    PORT
      LAYER M4 ;
        RECT  25.728 10.896 25.92 10.92 ;
    END
  END q[16]
  PIN q[170]
    DIRECTION OUTPUT ;
    USE SIGNAL ;
    PORT
      LAYER M4 ;
        RECT  25.728 25.68 25.92 25.704 ;
    END
  END q[170]
  PIN q[171]
    DIRECTION OUTPUT ;
    USE SIGNAL ;
    PORT
      LAYER M4 ;
        RECT  25.728 25.776 25.92 25.8 ;
    END
  END q[171]
  PIN q[172]
    DIRECTION OUTPUT ;
    USE SIGNAL ;
    PORT
      LAYER M4 ;
        RECT  25.728 25.872 25.92 25.896 ;
    END
  END q[172]
  PIN q[173]
    DIRECTION OUTPUT ;
    USE SIGNAL ;
    PORT
      LAYER M4 ;
        RECT  25.728 25.968 25.92 25.992 ;
    END
  END q[173]
  PIN q[174]
    DIRECTION OUTPUT ;
    USE SIGNAL ;
    PORT
      LAYER M4 ;
        RECT  25.728 26.064 25.92 26.088 ;
    END
  END q[174]
  PIN q[175]
    DIRECTION OUTPUT ;
    USE SIGNAL ;
    PORT
      LAYER M4 ;
        RECT  25.728 26.16 25.92 26.184 ;
    END
  END q[175]
  PIN q[176]
    DIRECTION OUTPUT ;
    USE SIGNAL ;
    PORT
      LAYER M4 ;
        RECT  25.728 26.256 25.92 26.28 ;
    END
  END q[176]
  PIN q[177]
    DIRECTION OUTPUT ;
    USE SIGNAL ;
    PORT
      LAYER M4 ;
        RECT  25.728 26.352 25.92 26.376 ;
    END
  END q[177]
  PIN q[178]
    DIRECTION OUTPUT ;
    USE SIGNAL ;
    PORT
      LAYER M4 ;
        RECT  25.728 26.448 25.92 26.472 ;
    END
  END q[178]
  PIN q[179]
    DIRECTION OUTPUT ;
    USE SIGNAL ;
    PORT
      LAYER M4 ;
        RECT  25.728 26.544 25.92 26.568 ;
    END
  END q[179]
  PIN q[17]
    DIRECTION OUTPUT ;
    USE SIGNAL ;
    PORT
      LAYER M4 ;
        RECT  25.728 10.992 25.92 11.016 ;
    END
  END q[17]
  PIN q[180]
    DIRECTION OUTPUT ;
    USE SIGNAL ;
    PORT
      LAYER M4 ;
        RECT  25.728 26.64 25.92 26.664 ;
    END
  END q[180]
  PIN q[181]
    DIRECTION OUTPUT ;
    USE SIGNAL ;
    PORT
      LAYER M4 ;
        RECT  25.728 26.736 25.92 26.76 ;
    END
  END q[181]
  PIN q[182]
    DIRECTION OUTPUT ;
    USE SIGNAL ;
    PORT
      LAYER M4 ;
        RECT  25.728 26.832 25.92 26.856 ;
    END
  END q[182]
  PIN q[183]
    DIRECTION OUTPUT ;
    USE SIGNAL ;
    PORT
      LAYER M4 ;
        RECT  25.728 26.928 25.92 26.952 ;
    END
  END q[183]
  PIN q[184]
    DIRECTION OUTPUT ;
    USE SIGNAL ;
    PORT
      LAYER M4 ;
        RECT  25.728 27.024 25.92 27.048 ;
    END
  END q[184]
  PIN q[185]
    DIRECTION OUTPUT ;
    USE SIGNAL ;
    PORT
      LAYER M4 ;
        RECT  25.728 27.12 25.92 27.144 ;
    END
  END q[185]
  PIN q[186]
    DIRECTION OUTPUT ;
    USE SIGNAL ;
    PORT
      LAYER M4 ;
        RECT  25.728 27.216 25.92 27.24 ;
    END
  END q[186]
  PIN q[187]
    DIRECTION OUTPUT ;
    USE SIGNAL ;
    PORT
      LAYER M4 ;
        RECT  25.728 27.312 25.92 27.336 ;
    END
  END q[187]
  PIN q[188]
    DIRECTION OUTPUT ;
    USE SIGNAL ;
    PORT
      LAYER M4 ;
        RECT  25.728 27.408 25.92 27.432 ;
    END
  END q[188]
  PIN q[189]
    DIRECTION OUTPUT ;
    USE SIGNAL ;
    PORT
      LAYER M4 ;
        RECT  25.728 27.504 25.92 27.528 ;
    END
  END q[189]
  PIN q[18]
    DIRECTION OUTPUT ;
    USE SIGNAL ;
    PORT
      LAYER M4 ;
        RECT  25.728 11.088 25.92 11.112 ;
    END
  END q[18]
  PIN q[190]
    DIRECTION OUTPUT ;
    USE SIGNAL ;
    PORT
      LAYER M4 ;
        RECT  25.728 27.6 25.92 27.624 ;
    END
  END q[190]
  PIN q[191]
    DIRECTION OUTPUT ;
    USE SIGNAL ;
    PORT
      LAYER M4 ;
        RECT  25.728 27.696 25.92 27.72 ;
    END
  END q[191]
  PIN q[192]
    DIRECTION OUTPUT ;
    USE SIGNAL ;
    PORT
      LAYER M4 ;
        RECT  25.728 27.792 25.92 27.816 ;
    END
  END q[192]
  PIN q[193]
    DIRECTION OUTPUT ;
    USE SIGNAL ;
    PORT
      LAYER M4 ;
        RECT  25.728 27.888 25.92 27.912 ;
    END
  END q[193]
  PIN q[194]
    DIRECTION OUTPUT ;
    USE SIGNAL ;
    PORT
      LAYER M4 ;
        RECT  25.728 27.984 25.92 28.008 ;
    END
  END q[194]
  PIN q[195]
    DIRECTION OUTPUT ;
    USE SIGNAL ;
    PORT
      LAYER M4 ;
        RECT  25.728 28.08 25.92 28.104 ;
    END
  END q[195]
  PIN q[196]
    DIRECTION OUTPUT ;
    USE SIGNAL ;
    PORT
      LAYER M4 ;
        RECT  25.728 28.176 25.92 28.2 ;
    END
  END q[196]
  PIN q[197]
    DIRECTION OUTPUT ;
    USE SIGNAL ;
    PORT
      LAYER M4 ;
        RECT  25.728 28.272 25.92 28.296 ;
    END
  END q[197]
  PIN q[198]
    DIRECTION OUTPUT ;
    USE SIGNAL ;
    PORT
      LAYER M4 ;
        RECT  25.728 28.368 25.92 28.392 ;
    END
  END q[198]
  PIN q[199]
    DIRECTION OUTPUT ;
    USE SIGNAL ;
    PORT
      LAYER M4 ;
        RECT  25.728 28.464 25.92 28.488 ;
    END
  END q[199]
  PIN q[19]
    DIRECTION OUTPUT ;
    USE SIGNAL ;
    PORT
      LAYER M4 ;
        RECT  25.728 11.184 25.92 11.208 ;
    END
  END q[19]
  PIN q[1]
    DIRECTION OUTPUT ;
    USE SIGNAL ;
    PORT
      LAYER M4 ;
        RECT  25.728 9.456 25.92 9.48 ;
    END
  END q[1]
  PIN q[200]
    DIRECTION OUTPUT ;
    USE SIGNAL ;
    PORT
      LAYER M4 ;
        RECT  25.728 28.56 25.92 28.584 ;
    END
  END q[200]
  PIN q[201]
    DIRECTION OUTPUT ;
    USE SIGNAL ;
    PORT
      LAYER M4 ;
        RECT  25.728 28.656 25.92 28.68 ;
    END
  END q[201]
  PIN q[202]
    DIRECTION OUTPUT ;
    USE SIGNAL ;
    PORT
      LAYER M4 ;
        RECT  25.728 28.752 25.92 28.776 ;
    END
  END q[202]
  PIN q[203]
    DIRECTION OUTPUT ;
    USE SIGNAL ;
    PORT
      LAYER M4 ;
        RECT  25.728 28.848 25.92 28.872 ;
    END
  END q[203]
  PIN q[204]
    DIRECTION OUTPUT ;
    USE SIGNAL ;
    PORT
      LAYER M4 ;
        RECT  25.728 28.944 25.92 28.968 ;
    END
  END q[204]
  PIN q[205]
    DIRECTION OUTPUT ;
    USE SIGNAL ;
    PORT
      LAYER M4 ;
        RECT  25.728 29.04 25.92 29.064 ;
    END
  END q[205]
  PIN q[206]
    DIRECTION OUTPUT ;
    USE SIGNAL ;
    PORT
      LAYER M4 ;
        RECT  25.728 29.136 25.92 29.16 ;
    END
  END q[206]
  PIN q[207]
    DIRECTION OUTPUT ;
    USE SIGNAL ;
    PORT
      LAYER M4 ;
        RECT  25.728 29.232 25.92 29.256 ;
    END
  END q[207]
  PIN q[208]
    DIRECTION OUTPUT ;
    USE SIGNAL ;
    PORT
      LAYER M4 ;
        RECT  25.728 29.328 25.92 29.352 ;
    END
  END q[208]
  PIN q[209]
    DIRECTION OUTPUT ;
    USE SIGNAL ;
    PORT
      LAYER M4 ;
        RECT  25.728 29.424 25.92 29.448 ;
    END
  END q[209]
  PIN q[20]
    DIRECTION OUTPUT ;
    USE SIGNAL ;
    PORT
      LAYER M4 ;
        RECT  25.728 11.28 25.92 11.304 ;
    END
  END q[20]
  PIN q[210]
    DIRECTION OUTPUT ;
    USE SIGNAL ;
    PORT
      LAYER M4 ;
        RECT  25.728 29.52 25.92 29.544 ;
    END
  END q[210]
  PIN q[211]
    DIRECTION OUTPUT ;
    USE SIGNAL ;
    PORT
      LAYER M4 ;
        RECT  25.728 29.616 25.92 29.64 ;
    END
  END q[211]
  PIN q[212]
    DIRECTION OUTPUT ;
    USE SIGNAL ;
    PORT
      LAYER M4 ;
        RECT  25.728 29.712 25.92 29.736 ;
    END
  END q[212]
  PIN q[213]
    DIRECTION OUTPUT ;
    USE SIGNAL ;
    PORT
      LAYER M4 ;
        RECT  25.728 29.808 25.92 29.832 ;
    END
  END q[213]
  PIN q[214]
    DIRECTION OUTPUT ;
    USE SIGNAL ;
    PORT
      LAYER M4 ;
        RECT  25.728 29.904 25.92 29.928 ;
    END
  END q[214]
  PIN q[215]
    DIRECTION OUTPUT ;
    USE SIGNAL ;
    PORT
      LAYER M4 ;
        RECT  25.728 30 25.92 30.024 ;
    END
  END q[215]
  PIN q[216]
    DIRECTION OUTPUT ;
    USE SIGNAL ;
    PORT
      LAYER M4 ;
        RECT  25.728 30.096 25.92 30.12 ;
    END
  END q[216]
  PIN q[217]
    DIRECTION OUTPUT ;
    USE SIGNAL ;
    PORT
      LAYER M4 ;
        RECT  25.728 30.192 25.92 30.216 ;
    END
  END q[217]
  PIN q[218]
    DIRECTION OUTPUT ;
    USE SIGNAL ;
    PORT
      LAYER M4 ;
        RECT  25.728 30.288 25.92 30.312 ;
    END
  END q[218]
  PIN q[219]
    DIRECTION OUTPUT ;
    USE SIGNAL ;
    PORT
      LAYER M4 ;
        RECT  25.728 30.384 25.92 30.408 ;
    END
  END q[219]
  PIN q[21]
    DIRECTION OUTPUT ;
    USE SIGNAL ;
    PORT
      LAYER M4 ;
        RECT  25.728 11.376 25.92 11.4 ;
    END
  END q[21]
  PIN q[220]
    DIRECTION OUTPUT ;
    USE SIGNAL ;
    PORT
      LAYER M4 ;
        RECT  25.728 30.48 25.92 30.504 ;
    END
  END q[220]
  PIN q[221]
    DIRECTION OUTPUT ;
    USE SIGNAL ;
    PORT
      LAYER M4 ;
        RECT  25.728 30.576 25.92 30.6 ;
    END
  END q[221]
  PIN q[222]
    DIRECTION OUTPUT ;
    USE SIGNAL ;
    PORT
      LAYER M4 ;
        RECT  25.728 30.672 25.92 30.696 ;
    END
  END q[222]
  PIN q[223]
    DIRECTION OUTPUT ;
    USE SIGNAL ;
    PORT
      LAYER M4 ;
        RECT  25.728 30.768 25.92 30.792 ;
    END
  END q[223]
  PIN q[224]
    DIRECTION OUTPUT ;
    USE SIGNAL ;
    PORT
      LAYER M4 ;
        RECT  25.728 30.864 25.92 30.888 ;
    END
  END q[224]
  PIN q[225]
    DIRECTION OUTPUT ;
    USE SIGNAL ;
    PORT
      LAYER M4 ;
        RECT  25.728 30.96 25.92 30.984 ;
    END
  END q[225]
  PIN q[226]
    DIRECTION OUTPUT ;
    USE SIGNAL ;
    PORT
      LAYER M4 ;
        RECT  25.728 31.056 25.92 31.08 ;
    END
  END q[226]
  PIN q[227]
    DIRECTION OUTPUT ;
    USE SIGNAL ;
    PORT
      LAYER M4 ;
        RECT  25.728 31.152 25.92 31.176 ;
    END
  END q[227]
  PIN q[228]
    DIRECTION OUTPUT ;
    USE SIGNAL ;
    PORT
      LAYER M4 ;
        RECT  25.728 31.248 25.92 31.272 ;
    END
  END q[228]
  PIN q[229]
    DIRECTION OUTPUT ;
    USE SIGNAL ;
    PORT
      LAYER M4 ;
        RECT  25.728 31.344 25.92 31.368 ;
    END
  END q[229]
  PIN q[22]
    DIRECTION OUTPUT ;
    USE SIGNAL ;
    PORT
      LAYER M4 ;
        RECT  25.728 11.472 25.92 11.496 ;
    END
  END q[22]
  PIN q[230]
    DIRECTION OUTPUT ;
    USE SIGNAL ;
    PORT
      LAYER M4 ;
        RECT  25.728 31.44 25.92 31.464 ;
    END
  END q[230]
  PIN q[231]
    DIRECTION OUTPUT ;
    USE SIGNAL ;
    PORT
      LAYER M4 ;
        RECT  25.728 31.536 25.92 31.56 ;
    END
  END q[231]
  PIN q[232]
    DIRECTION OUTPUT ;
    USE SIGNAL ;
    PORT
      LAYER M4 ;
        RECT  25.728 31.632 25.92 31.656 ;
    END
  END q[232]
  PIN q[233]
    DIRECTION OUTPUT ;
    USE SIGNAL ;
    PORT
      LAYER M4 ;
        RECT  25.728 31.728 25.92 31.752 ;
    END
  END q[233]
  PIN q[234]
    DIRECTION OUTPUT ;
    USE SIGNAL ;
    PORT
      LAYER M4 ;
        RECT  25.728 31.824 25.92 31.848 ;
    END
  END q[234]
  PIN q[235]
    DIRECTION OUTPUT ;
    USE SIGNAL ;
    PORT
      LAYER M4 ;
        RECT  25.728 31.92 25.92 31.944 ;
    END
  END q[235]
  PIN q[236]
    DIRECTION OUTPUT ;
    USE SIGNAL ;
    PORT
      LAYER M4 ;
        RECT  25.728 32.016 25.92 32.04 ;
    END
  END q[236]
  PIN q[237]
    DIRECTION OUTPUT ;
    USE SIGNAL ;
    PORT
      LAYER M4 ;
        RECT  25.728 32.112 25.92 32.136 ;
    END
  END q[237]
  PIN q[238]
    DIRECTION OUTPUT ;
    USE SIGNAL ;
    PORT
      LAYER M4 ;
        RECT  25.728 32.208 25.92 32.232 ;
    END
  END q[238]
  PIN q[239]
    DIRECTION OUTPUT ;
    USE SIGNAL ;
    PORT
      LAYER M4 ;
        RECT  25.728 32.304 25.92 32.328 ;
    END
  END q[239]
  PIN q[23]
    DIRECTION OUTPUT ;
    USE SIGNAL ;
    PORT
      LAYER M4 ;
        RECT  25.728 11.568 25.92 11.592 ;
    END
  END q[23]
  PIN q[240]
    DIRECTION OUTPUT ;
    USE SIGNAL ;
    PORT
      LAYER M4 ;
        RECT  25.728 32.4 25.92 32.424 ;
    END
  END q[240]
  PIN q[241]
    DIRECTION OUTPUT ;
    USE SIGNAL ;
    PORT
      LAYER M4 ;
        RECT  25.728 32.496 25.92 32.52 ;
    END
  END q[241]
  PIN q[242]
    DIRECTION OUTPUT ;
    USE SIGNAL ;
    PORT
      LAYER M4 ;
        RECT  25.728 32.592 25.92 32.616 ;
    END
  END q[242]
  PIN q[243]
    DIRECTION OUTPUT ;
    USE SIGNAL ;
    PORT
      LAYER M4 ;
        RECT  25.728 32.688 25.92 32.712 ;
    END
  END q[243]
  PIN q[244]
    DIRECTION OUTPUT ;
    USE SIGNAL ;
    PORT
      LAYER M4 ;
        RECT  25.728 32.784 25.92 32.808 ;
    END
  END q[244]
  PIN q[245]
    DIRECTION OUTPUT ;
    USE SIGNAL ;
    PORT
      LAYER M4 ;
        RECT  25.728 32.88 25.92 32.904 ;
    END
  END q[245]
  PIN q[246]
    DIRECTION OUTPUT ;
    USE SIGNAL ;
    PORT
      LAYER M4 ;
        RECT  25.728 32.976 25.92 33 ;
    END
  END q[246]
  PIN q[247]
    DIRECTION OUTPUT ;
    USE SIGNAL ;
    PORT
      LAYER M4 ;
        RECT  25.728 33.072 25.92 33.096 ;
    END
  END q[247]
  PIN q[248]
    DIRECTION OUTPUT ;
    USE SIGNAL ;
    PORT
      LAYER M4 ;
        RECT  25.728 33.168 25.92 33.192 ;
    END
  END q[248]
  PIN q[249]
    DIRECTION OUTPUT ;
    USE SIGNAL ;
    PORT
      LAYER M4 ;
        RECT  25.728 33.264 25.92 33.288 ;
    END
  END q[249]
  PIN q[24]
    DIRECTION OUTPUT ;
    USE SIGNAL ;
    PORT
      LAYER M4 ;
        RECT  25.728 11.664 25.92 11.688 ;
    END
  END q[24]
  PIN q[250]
    DIRECTION OUTPUT ;
    USE SIGNAL ;
    PORT
      LAYER M4 ;
        RECT  25.728 33.36 25.92 33.384 ;
    END
  END q[250]
  PIN q[251]
    DIRECTION OUTPUT ;
    USE SIGNAL ;
    PORT
      LAYER M4 ;
        RECT  25.728 33.456 25.92 33.48 ;
    END
  END q[251]
  PIN q[252]
    DIRECTION OUTPUT ;
    USE SIGNAL ;
    PORT
      LAYER M4 ;
        RECT  25.728 33.552 25.92 33.576 ;
    END
  END q[252]
  PIN q[253]
    DIRECTION OUTPUT ;
    USE SIGNAL ;
    PORT
      LAYER M4 ;
        RECT  25.728 33.648 25.92 33.672 ;
    END
  END q[253]
  PIN q[254]
    DIRECTION OUTPUT ;
    USE SIGNAL ;
    PORT
      LAYER M4 ;
        RECT  25.728 33.744 25.92 33.768 ;
    END
  END q[254]
  PIN q[255]
    DIRECTION OUTPUT ;
    USE SIGNAL ;
    PORT
      LAYER M4 ;
        RECT  25.728 33.84 25.92 33.864 ;
    END
  END q[255]
  PIN q[25]
    DIRECTION OUTPUT ;
    USE SIGNAL ;
    PORT
      LAYER M4 ;
        RECT  25.728 11.76 25.92 11.784 ;
    END
  END q[25]
  PIN q[26]
    DIRECTION OUTPUT ;
    USE SIGNAL ;
    PORT
      LAYER M4 ;
        RECT  25.728 11.856 25.92 11.88 ;
    END
  END q[26]
  PIN q[27]
    DIRECTION OUTPUT ;
    USE SIGNAL ;
    PORT
      LAYER M4 ;
        RECT  25.728 11.952 25.92 11.976 ;
    END
  END q[27]
  PIN q[28]
    DIRECTION OUTPUT ;
    USE SIGNAL ;
    PORT
      LAYER M4 ;
        RECT  25.728 12.048 25.92 12.072 ;
    END
  END q[28]
  PIN q[29]
    DIRECTION OUTPUT ;
    USE SIGNAL ;
    PORT
      LAYER M4 ;
        RECT  25.728 12.144 25.92 12.168 ;
    END
  END q[29]
  PIN q[2]
    DIRECTION OUTPUT ;
    USE SIGNAL ;
    PORT
      LAYER M4 ;
        RECT  25.728 9.552 25.92 9.576 ;
    END
  END q[2]
  PIN q[30]
    DIRECTION OUTPUT ;
    USE SIGNAL ;
    PORT
      LAYER M4 ;
        RECT  25.728 12.24 25.92 12.264 ;
    END
  END q[30]
  PIN q[31]
    DIRECTION OUTPUT ;
    USE SIGNAL ;
    PORT
      LAYER M4 ;
        RECT  25.728 12.336 25.92 12.36 ;
    END
  END q[31]
  PIN q[32]
    DIRECTION OUTPUT ;
    USE SIGNAL ;
    PORT
      LAYER M4 ;
        RECT  25.728 12.432 25.92 12.456 ;
    END
  END q[32]
  PIN q[33]
    DIRECTION OUTPUT ;
    USE SIGNAL ;
    PORT
      LAYER M4 ;
        RECT  25.728 12.528 25.92 12.552 ;
    END
  END q[33]
  PIN q[34]
    DIRECTION OUTPUT ;
    USE SIGNAL ;
    PORT
      LAYER M4 ;
        RECT  25.728 12.624 25.92 12.648 ;
    END
  END q[34]
  PIN q[35]
    DIRECTION OUTPUT ;
    USE SIGNAL ;
    PORT
      LAYER M4 ;
        RECT  25.728 12.72 25.92 12.744 ;
    END
  END q[35]
  PIN q[36]
    DIRECTION OUTPUT ;
    USE SIGNAL ;
    PORT
      LAYER M4 ;
        RECT  25.728 12.816 25.92 12.84 ;
    END
  END q[36]
  PIN q[37]
    DIRECTION OUTPUT ;
    USE SIGNAL ;
    PORT
      LAYER M4 ;
        RECT  25.728 12.912 25.92 12.936 ;
    END
  END q[37]
  PIN q[38]
    DIRECTION OUTPUT ;
    USE SIGNAL ;
    PORT
      LAYER M4 ;
        RECT  25.728 13.008 25.92 13.032 ;
    END
  END q[38]
  PIN q[39]
    DIRECTION OUTPUT ;
    USE SIGNAL ;
    PORT
      LAYER M4 ;
        RECT  25.728 13.104 25.92 13.128 ;
    END
  END q[39]
  PIN q[3]
    DIRECTION OUTPUT ;
    USE SIGNAL ;
    PORT
      LAYER M4 ;
        RECT  25.728 9.648 25.92 9.672 ;
    END
  END q[3]
  PIN q[40]
    DIRECTION OUTPUT ;
    USE SIGNAL ;
    PORT
      LAYER M4 ;
        RECT  25.728 13.2 25.92 13.224 ;
    END
  END q[40]
  PIN q[41]
    DIRECTION OUTPUT ;
    USE SIGNAL ;
    PORT
      LAYER M4 ;
        RECT  25.728 13.296 25.92 13.32 ;
    END
  END q[41]
  PIN q[42]
    DIRECTION OUTPUT ;
    USE SIGNAL ;
    PORT
      LAYER M4 ;
        RECT  25.728 13.392 25.92 13.416 ;
    END
  END q[42]
  PIN q[43]
    DIRECTION OUTPUT ;
    USE SIGNAL ;
    PORT
      LAYER M4 ;
        RECT  25.728 13.488 25.92 13.512 ;
    END
  END q[43]
  PIN q[44]
    DIRECTION OUTPUT ;
    USE SIGNAL ;
    PORT
      LAYER M4 ;
        RECT  25.728 13.584 25.92 13.608 ;
    END
  END q[44]
  PIN q[45]
    DIRECTION OUTPUT ;
    USE SIGNAL ;
    PORT
      LAYER M4 ;
        RECT  25.728 13.68 25.92 13.704 ;
    END
  END q[45]
  PIN q[46]
    DIRECTION OUTPUT ;
    USE SIGNAL ;
    PORT
      LAYER M4 ;
        RECT  25.728 13.776 25.92 13.8 ;
    END
  END q[46]
  PIN q[47]
    DIRECTION OUTPUT ;
    USE SIGNAL ;
    PORT
      LAYER M4 ;
        RECT  25.728 13.872 25.92 13.896 ;
    END
  END q[47]
  PIN q[48]
    DIRECTION OUTPUT ;
    USE SIGNAL ;
    PORT
      LAYER M4 ;
        RECT  25.728 13.968 25.92 13.992 ;
    END
  END q[48]
  PIN q[49]
    DIRECTION OUTPUT ;
    USE SIGNAL ;
    PORT
      LAYER M4 ;
        RECT  25.728 14.064 25.92 14.088 ;
    END
  END q[49]
  PIN q[4]
    DIRECTION OUTPUT ;
    USE SIGNAL ;
    PORT
      LAYER M4 ;
        RECT  25.728 9.744 25.92 9.768 ;
    END
  END q[4]
  PIN q[50]
    DIRECTION OUTPUT ;
    USE SIGNAL ;
    PORT
      LAYER M4 ;
        RECT  25.728 14.16 25.92 14.184 ;
    END
  END q[50]
  PIN q[51]
    DIRECTION OUTPUT ;
    USE SIGNAL ;
    PORT
      LAYER M4 ;
        RECT  25.728 14.256 25.92 14.28 ;
    END
  END q[51]
  PIN q[52]
    DIRECTION OUTPUT ;
    USE SIGNAL ;
    PORT
      LAYER M4 ;
        RECT  25.728 14.352 25.92 14.376 ;
    END
  END q[52]
  PIN q[53]
    DIRECTION OUTPUT ;
    USE SIGNAL ;
    PORT
      LAYER M4 ;
        RECT  25.728 14.448 25.92 14.472 ;
    END
  END q[53]
  PIN q[54]
    DIRECTION OUTPUT ;
    USE SIGNAL ;
    PORT
      LAYER M4 ;
        RECT  25.728 14.544 25.92 14.568 ;
    END
  END q[54]
  PIN q[55]
    DIRECTION OUTPUT ;
    USE SIGNAL ;
    PORT
      LAYER M4 ;
        RECT  25.728 14.64 25.92 14.664 ;
    END
  END q[55]
  PIN q[56]
    DIRECTION OUTPUT ;
    USE SIGNAL ;
    PORT
      LAYER M4 ;
        RECT  25.728 14.736 25.92 14.76 ;
    END
  END q[56]
  PIN q[57]
    DIRECTION OUTPUT ;
    USE SIGNAL ;
    PORT
      LAYER M4 ;
        RECT  25.728 14.832 25.92 14.856 ;
    END
  END q[57]
  PIN q[58]
    DIRECTION OUTPUT ;
    USE SIGNAL ;
    PORT
      LAYER M4 ;
        RECT  25.728 14.928 25.92 14.952 ;
    END
  END q[58]
  PIN q[59]
    DIRECTION OUTPUT ;
    USE SIGNAL ;
    PORT
      LAYER M4 ;
        RECT  25.728 15.024 25.92 15.048 ;
    END
  END q[59]
  PIN q[5]
    DIRECTION OUTPUT ;
    USE SIGNAL ;
    PORT
      LAYER M4 ;
        RECT  25.728 9.84 25.92 9.864 ;
    END
  END q[5]
  PIN q[60]
    DIRECTION OUTPUT ;
    USE SIGNAL ;
    PORT
      LAYER M4 ;
        RECT  25.728 15.12 25.92 15.144 ;
    END
  END q[60]
  PIN q[61]
    DIRECTION OUTPUT ;
    USE SIGNAL ;
    PORT
      LAYER M4 ;
        RECT  25.728 15.216 25.92 15.24 ;
    END
  END q[61]
  PIN q[62]
    DIRECTION OUTPUT ;
    USE SIGNAL ;
    PORT
      LAYER M4 ;
        RECT  25.728 15.312 25.92 15.336 ;
    END
  END q[62]
  PIN q[63]
    DIRECTION OUTPUT ;
    USE SIGNAL ;
    PORT
      LAYER M4 ;
        RECT  25.728 15.408 25.92 15.432 ;
    END
  END q[63]
  PIN q[64]
    DIRECTION OUTPUT ;
    USE SIGNAL ;
    PORT
      LAYER M4 ;
        RECT  25.728 15.504 25.92 15.528 ;
    END
  END q[64]
  PIN q[65]
    DIRECTION OUTPUT ;
    USE SIGNAL ;
    PORT
      LAYER M4 ;
        RECT  25.728 15.6 25.92 15.624 ;
    END
  END q[65]
  PIN q[66]
    DIRECTION OUTPUT ;
    USE SIGNAL ;
    PORT
      LAYER M4 ;
        RECT  25.728 15.696 25.92 15.72 ;
    END
  END q[66]
  PIN q[67]
    DIRECTION OUTPUT ;
    USE SIGNAL ;
    PORT
      LAYER M4 ;
        RECT  25.728 15.792 25.92 15.816 ;
    END
  END q[67]
  PIN q[68]
    DIRECTION OUTPUT ;
    USE SIGNAL ;
    PORT
      LAYER M4 ;
        RECT  25.728 15.888 25.92 15.912 ;
    END
  END q[68]
  PIN q[69]
    DIRECTION OUTPUT ;
    USE SIGNAL ;
    PORT
      LAYER M4 ;
        RECT  25.728 15.984 25.92 16.008 ;
    END
  END q[69]
  PIN q[6]
    DIRECTION OUTPUT ;
    USE SIGNAL ;
    PORT
      LAYER M4 ;
        RECT  25.728 9.936 25.92 9.96 ;
    END
  END q[6]
  PIN q[70]
    DIRECTION OUTPUT ;
    USE SIGNAL ;
    PORT
      LAYER M4 ;
        RECT  25.728 16.08 25.92 16.104 ;
    END
  END q[70]
  PIN q[71]
    DIRECTION OUTPUT ;
    USE SIGNAL ;
    PORT
      LAYER M4 ;
        RECT  25.728 16.176 25.92 16.2 ;
    END
  END q[71]
  PIN q[72]
    DIRECTION OUTPUT ;
    USE SIGNAL ;
    PORT
      LAYER M4 ;
        RECT  25.728 16.272 25.92 16.296 ;
    END
  END q[72]
  PIN q[73]
    DIRECTION OUTPUT ;
    USE SIGNAL ;
    PORT
      LAYER M4 ;
        RECT  25.728 16.368 25.92 16.392 ;
    END
  END q[73]
  PIN q[74]
    DIRECTION OUTPUT ;
    USE SIGNAL ;
    PORT
      LAYER M4 ;
        RECT  25.728 16.464 25.92 16.488 ;
    END
  END q[74]
  PIN q[75]
    DIRECTION OUTPUT ;
    USE SIGNAL ;
    PORT
      LAYER M4 ;
        RECT  25.728 16.56 25.92 16.584 ;
    END
  END q[75]
  PIN q[76]
    DIRECTION OUTPUT ;
    USE SIGNAL ;
    PORT
      LAYER M4 ;
        RECT  25.728 16.656 25.92 16.68 ;
    END
  END q[76]
  PIN q[77]
    DIRECTION OUTPUT ;
    USE SIGNAL ;
    PORT
      LAYER M4 ;
        RECT  25.728 16.752 25.92 16.776 ;
    END
  END q[77]
  PIN q[78]
    DIRECTION OUTPUT ;
    USE SIGNAL ;
    PORT
      LAYER M4 ;
        RECT  25.728 16.848 25.92 16.872 ;
    END
  END q[78]
  PIN q[79]
    DIRECTION OUTPUT ;
    USE SIGNAL ;
    PORT
      LAYER M4 ;
        RECT  25.728 16.944 25.92 16.968 ;
    END
  END q[79]
  PIN q[7]
    DIRECTION OUTPUT ;
    USE SIGNAL ;
    PORT
      LAYER M4 ;
        RECT  25.728 10.032 25.92 10.056 ;
    END
  END q[7]
  PIN q[80]
    DIRECTION OUTPUT ;
    USE SIGNAL ;
    PORT
      LAYER M4 ;
        RECT  25.728 17.04 25.92 17.064 ;
    END
  END q[80]
  PIN q[81]
    DIRECTION OUTPUT ;
    USE SIGNAL ;
    PORT
      LAYER M4 ;
        RECT  25.728 17.136 25.92 17.16 ;
    END
  END q[81]
  PIN q[82]
    DIRECTION OUTPUT ;
    USE SIGNAL ;
    PORT
      LAYER M4 ;
        RECT  25.728 17.232 25.92 17.256 ;
    END
  END q[82]
  PIN q[83]
    DIRECTION OUTPUT ;
    USE SIGNAL ;
    PORT
      LAYER M4 ;
        RECT  25.728 17.328 25.92 17.352 ;
    END
  END q[83]
  PIN q[84]
    DIRECTION OUTPUT ;
    USE SIGNAL ;
    PORT
      LAYER M4 ;
        RECT  25.728 17.424 25.92 17.448 ;
    END
  END q[84]
  PIN q[85]
    DIRECTION OUTPUT ;
    USE SIGNAL ;
    PORT
      LAYER M4 ;
        RECT  25.728 17.52 25.92 17.544 ;
    END
  END q[85]
  PIN q[86]
    DIRECTION OUTPUT ;
    USE SIGNAL ;
    PORT
      LAYER M4 ;
        RECT  25.728 17.616 25.92 17.64 ;
    END
  END q[86]
  PIN q[87]
    DIRECTION OUTPUT ;
    USE SIGNAL ;
    PORT
      LAYER M4 ;
        RECT  25.728 17.712 25.92 17.736 ;
    END
  END q[87]
  PIN q[88]
    DIRECTION OUTPUT ;
    USE SIGNAL ;
    PORT
      LAYER M4 ;
        RECT  25.728 17.808 25.92 17.832 ;
    END
  END q[88]
  PIN q[89]
    DIRECTION OUTPUT ;
    USE SIGNAL ;
    PORT
      LAYER M4 ;
        RECT  25.728 17.904 25.92 17.928 ;
    END
  END q[89]
  PIN q[8]
    DIRECTION OUTPUT ;
    USE SIGNAL ;
    PORT
      LAYER M4 ;
        RECT  25.728 10.128 25.92 10.152 ;
    END
  END q[8]
  PIN q[90]
    DIRECTION OUTPUT ;
    USE SIGNAL ;
    PORT
      LAYER M4 ;
        RECT  25.728 18 25.92 18.024 ;
    END
  END q[90]
  PIN q[91]
    DIRECTION OUTPUT ;
    USE SIGNAL ;
    PORT
      LAYER M4 ;
        RECT  25.728 18.096 25.92 18.12 ;
    END
  END q[91]
  PIN q[92]
    DIRECTION OUTPUT ;
    USE SIGNAL ;
    PORT
      LAYER M4 ;
        RECT  25.728 18.192 25.92 18.216 ;
    END
  END q[92]
  PIN q[93]
    DIRECTION OUTPUT ;
    USE SIGNAL ;
    PORT
      LAYER M4 ;
        RECT  25.728 18.288 25.92 18.312 ;
    END
  END q[93]
  PIN q[94]
    DIRECTION OUTPUT ;
    USE SIGNAL ;
    PORT
      LAYER M4 ;
        RECT  25.728 18.384 25.92 18.408 ;
    END
  END q[94]
  PIN q[95]
    DIRECTION OUTPUT ;
    USE SIGNAL ;
    PORT
      LAYER M4 ;
        RECT  25.728 18.48 25.92 18.504 ;
    END
  END q[95]
  PIN q[96]
    DIRECTION OUTPUT ;
    USE SIGNAL ;
    PORT
      LAYER M4 ;
        RECT  25.728 18.576 25.92 18.6 ;
    END
  END q[96]
  PIN q[97]
    DIRECTION OUTPUT ;
    USE SIGNAL ;
    PORT
      LAYER M4 ;
        RECT  25.728 18.672 25.92 18.696 ;
    END
  END q[97]
  PIN q[98]
    DIRECTION OUTPUT ;
    USE SIGNAL ;
    PORT
      LAYER M4 ;
        RECT  25.728 18.768 25.92 18.792 ;
    END
  END q[98]
  PIN q[99]
    DIRECTION OUTPUT ;
    USE SIGNAL ;
    PORT
      LAYER M4 ;
        RECT  25.728 18.864 25.92 18.888 ;
    END
  END q[99]
  PIN q[9]
    DIRECTION OUTPUT ;
    USE SIGNAL ;
    PORT
      LAYER M4 ;
        RECT  25.728 10.224 25.92 10.248 ;
    END
  END q[9]
  PIN VDD
    DIRECTION INOUT ;
    USE POWER ;
    PORT
      LAYER M5 ;
        RECT  18.792 2.151 18.912 41.049 ;
        RECT  13.392 2.151 13.512 41.049 ;
        RECT  7.992 2.151 8.112 41.049 ;
        RECT  2.592 2.151 2.712 41.049 ;
    END
  END VDD
  PIN VSS
    DIRECTION INOUT ;
    USE GROUND ;
    PORT
      LAYER M5 ;
        RECT  18.6 2.137 18.72 41.063 ;
        RECT  13.2 2.137 13.32 41.063 ;
        RECT  7.8 2.137 7.92 41.063 ;
        RECT  2.4 2.137 2.52 41.063 ;
    END
  END VSS
  OBS
    LAYER RVTN ;
     RECT  2.16 2.16 2.268 2.295 ;
     RECT  23.652 2.16 23.76 2.295 ;
     RECT  23.652 2.565 23.76 2.7 ;
     RECT  2.16 2.565 2.268 2.835 ;
     RECT  23.112 2.7 23.76 2.835 ;
     RECT  23.112 3.105 23.76 3.24 ;
     RECT  2.16 3.105 2.268 3.375 ;
     RECT  22.572 3.24 22.896 3.375 ;
     RECT  23.112 3.24 23.436 3.375 ;
     RECT  23.652 3.24 23.76 3.375 ;
     RECT  21.168 3.645 22.032 3.78 ;
     RECT  22.788 3.645 23.76 3.78 ;
     RECT  2.16 3.645 2.268 3.915 ;
     RECT  22.032 3.78 22.464 3.915 ;
     RECT  23.058 3.78 23.598 3.915 ;
     RECT  23.652 3.78 23.76 3.915 ;
     RECT  22.41 4.185 23.598 4.32 ;
     RECT  23.652 4.185 23.76 4.32 ;
     RECT  2.16 4.185 2.268 4.455 ;
     RECT  21.87 4.32 22.302 4.455 ;
     RECT  22.734 4.32 23.058 4.455 ;
     RECT  23.112 4.32 23.76 4.455 ;
     RECT  21.384 4.725 22.68 4.86 ;
     RECT  23.112 4.725 23.76 4.86 ;
     RECT  2.16 4.725 2.268 4.995 ;
     RECT  21.33 4.86 21.762 4.995 ;
     RECT  22.086 4.86 22.41 4.995 ;
     RECT  22.572 4.86 23.76 4.995 ;
     RECT  22.14 5.265 22.464 5.4 ;
     RECT  22.572 5.265 23.76 5.4 ;
     RECT  2.16 5.265 2.268 5.535 ;
     RECT  21.438 5.4 22.302 5.535 ;
     RECT  23.112 5.4 23.76 5.535 ;
     RECT  21.924 5.805 23.004 5.94 ;
     RECT  23.112 5.805 23.544 5.94 ;
     RECT  23.652 5.805 23.76 5.94 ;
     RECT  2.16 5.805 2.268 6.075 ;
     RECT  20.898 5.94 22.194 6.075 ;
     RECT  22.464 5.94 23.76 6.075 ;
     RECT  21.006 6.345 22.14 6.48 ;
     RECT  22.248 6.345 23.544 6.48 ;
     RECT  2.16 6.345 2.268 6.615 ;
     RECT  20.952 6.48 21.924 6.615 ;
     RECT  22.032 6.48 23.544 6.615 ;
     RECT  23.652 6.345 23.76 6.615 ;
     RECT  20.736 6.885 21.168 7.02 ;
     RECT  21.6 6.885 23.544 7.02 ;
     RECT  23.652 6.885 23.76 7.02 ;
     RECT  2.16 6.885 2.268 7.155 ;
     RECT  21.6 7.02 22.032 7.155 ;
     RECT  22.14 7.02 22.734 7.155 ;
     RECT  22.788 7.02 23.76 7.155 ;
     RECT  2.16 7.425 2.268 7.56 ;
     RECT  20.304 7.425 20.736 7.56 ;
     RECT  20.844 7.425 23.598 7.56 ;
     RECT  23.652 7.425 23.76 7.56 ;
     RECT  2.16 7.56 2.538 7.695 ;
     RECT  3.348 7.56 3.78 7.695 ;
     RECT  20.358 7.56 20.79 7.695 ;
     RECT  21.276 7.56 22.14 7.695 ;
     RECT  22.356 7.56 23.76 7.695 ;
     RECT  2.916 7.965 3.618 8.1 ;
     RECT  21.168 7.965 23.76 8.1 ;
     RECT  2.16 7.965 2.268 8.235 ;
     RECT  2.862 8.1 3.132 8.235 ;
     RECT  3.402 8.1 3.672 8.235 ;
     RECT  4.104 8.1 4.536 8.235 ;
     RECT  20.898 8.1 23.328 8.235 ;
     RECT  23.652 8.1 23.76 8.235 ;
     RECT  2.376 8.505 2.916 8.64 ;
     RECT  3.186 8.505 3.456 8.64 ;
     RECT  3.51 8.505 3.78 8.64 ;
     RECT  4.212 8.505 4.644 8.64 ;
     RECT  20.52 8.505 22.788 8.64 ;
     RECT  22.95 8.505 23.76 8.64 ;
     RECT  2.16 8.505 2.268 8.775 ;
     RECT  2.538 8.64 3.24 8.775 ;
     RECT  3.402 8.64 4.698 8.775 ;
     RECT  5.184 8.64 6.264 8.775 ;
     RECT  20.412 8.64 23.166 8.775 ;
     RECT  23.382 8.64 23.76 8.775 ;
     RECT  2.16 9.045 2.538 9.18 ;
     RECT  3.078 9.045 3.51 9.18 ;
     RECT  3.672 9.045 4.374 9.18 ;
     RECT  4.428 9.045 4.86 9.18 ;
     RECT  20.088 9.045 20.628 9.18 ;
     RECT  20.736 9.045 23.76 9.18 ;
     RECT  2.16 9.18 2.268 9.315 ;
     RECT  2.7 9.18 5.346 9.315 ;
     RECT  6.75 9.18 7.83 9.315 ;
     RECT  9.99 9.18 10.26 9.315 ;
     RECT  13.716 9.18 13.986 9.315 ;
     RECT  19.872 9.18 20.142 9.315 ;
     RECT  20.844 9.18 23.598 9.315 ;
     RECT  23.652 9.18 23.76 9.315 ;
     RECT  2.97 9.585 3.24 9.72 ;
     RECT  3.348 9.585 5.292 9.72 ;
     RECT  5.508 9.585 5.94 9.72 ;
     RECT  8.154 9.585 9.234 9.72 ;
     RECT  15.066 9.585 15.336 9.72 ;
     RECT  16.686 9.585 16.956 9.72 ;
     RECT  19.98 9.585 20.628 9.72 ;
     RECT  20.736 9.585 22.14 9.72 ;
     RECT  22.248 9.585 23.76 9.72 ;
     RECT  2.16 9.585 2.538 9.855 ;
     RECT  3.294 9.72 3.564 9.855 ;
     RECT  3.996 9.72 8.748 9.855 ;
     RECT  11.772 9.72 12.042 9.855 ;
     RECT  14.31 9.72 14.58 9.855 ;
     RECT  15.876 9.72 16.146 9.855 ;
     RECT  18.36 9.72 18.63 9.855 ;
     RECT  20.088 9.72 23.76 9.855 ;
     RECT  5.292 10.125 7.452 10.26 ;
     RECT  14.04 10.125 14.31 10.26 ;
     RECT  19.98 10.125 20.412 10.26 ;
     RECT  20.52 10.125 20.844 10.26 ;
     RECT  20.898 10.125 21.924 10.26 ;
     RECT  22.032 10.125 22.734 10.26 ;
     RECT  22.788 10.125 23.058 10.26 ;
     RECT  23.112 10.125 23.544 10.26 ;
     RECT  23.652 10.125 23.76 10.26 ;
     RECT  2.16 10.125 2.538 10.395 ;
     RECT  2.592 10.26 3.888 10.395 ;
     RECT  4.482 10.26 6.642 10.395 ;
     RECT  8.316 10.26 9.396 10.395 ;
     RECT  13.5 10.26 13.77 10.395 ;
     RECT  14.526 10.125 14.796 10.395 ;
     RECT  19.602 10.26 21.114 10.395 ;
     RECT  21.33 10.26 23.112 10.395 ;
     RECT  23.22 10.26 23.76 10.395 ;
     RECT  2.16 10.665 2.268 10.8 ;
     RECT  2.322 10.665 2.592 10.8 ;
     RECT  3.078 10.665 3.348 10.8 ;
     RECT  3.51 10.665 4.806 10.8 ;
     RECT  4.86 10.665 6.372 10.8 ;
     RECT  7.02 10.665 9.18 10.8 ;
     RECT  13.446 10.665 13.986 10.8 ;
     RECT  15.552 10.665 15.822 10.8 ;
     RECT  17.442 10.665 17.712 10.8 ;
     RECT  19.872 10.665 20.196 10.8 ;
     RECT  20.412 10.665 22.032 10.8 ;
     RECT  22.14 10.665 22.842 10.8 ;
     RECT  22.896 10.665 23.166 10.8 ;
     RECT  2.16 10.8 2.97 10.935 ;
     RECT  3.24 10.8 3.942 10.935 ;
     RECT  4.104 10.8 6.534 10.935 ;
     RECT  7.452 10.8 8.532 10.935 ;
     RECT  12.798 10.8 13.068 10.935 ;
     RECT  13.986 10.8 14.256 10.935 ;
     RECT  19.548 10.8 20.574 10.935 ;
     RECT  20.79 10.8 21.222 10.935 ;
     RECT  21.33 10.8 23.112 10.935 ;
     RECT  23.22 10.665 23.76 10.935 ;
     RECT  2.16 11.205 2.538 11.34 ;
     RECT  2.808 11.205 3.78 11.34 ;
     RECT  4.104 11.205 4.536 11.34 ;
     RECT  4.59 11.205 6.75 11.34 ;
     RECT  13.176 11.205 13.716 11.34 ;
     RECT  16.524 11.205 16.794 11.34 ;
     RECT  19.332 11.205 20.196 11.34 ;
     RECT  20.304 11.205 20.736 11.34 ;
     RECT  20.79 11.205 21.654 11.34 ;
     RECT  21.708 11.205 21.978 11.34 ;
     RECT  22.032 11.205 23.004 11.34 ;
     RECT  23.058 11.205 23.49 11.34 ;
     RECT  23.652 11.205 23.76 11.34 ;
     RECT  2.16 11.34 2.268 11.475 ;
     RECT  2.592 11.34 4.428 11.475 ;
     RECT  4.806 11.34 6.966 11.475 ;
     RECT  7.182 11.34 8.262 11.475 ;
     RECT  12.474 11.34 12.744 11.475 ;
     RECT  14.256 11.34 14.526 11.475 ;
     RECT  18.63 11.34 19.062 11.475 ;
     RECT  19.818 11.34 20.952 11.475 ;
     RECT  21.114 11.34 21.546 11.475 ;
     RECT  21.6 11.34 22.842 11.475 ;
     RECT  22.95 11.34 23.22 11.475 ;
     RECT  23.328 11.34 23.76 11.475 ;
     RECT  2.538 11.745 6.534 11.88 ;
     RECT  6.75 11.745 7.83 11.88 ;
     RECT  7.992 11.745 9.072 11.88 ;
     RECT  9.774 11.745 10.044 11.88 ;
     RECT  10.908 11.745 11.178 11.88 ;
     RECT  11.61 11.745 11.88 11.88 ;
     RECT  13.23 11.745 13.5 11.88 ;
     RECT  18.954 11.745 19.386 11.88 ;
     RECT  19.818 11.745 21.222 11.88 ;
     RECT  21.276 11.745 23.112 11.88 ;
     RECT  23.22 11.745 23.76 11.88 ;
     RECT  2.16 11.745 2.268 12.015 ;
     RECT  2.646 11.88 2.916 12.015 ;
     RECT  3.078 11.88 3.348 12.015 ;
     RECT  3.456 11.88 4.32 12.015 ;
     RECT  4.698 11.88 5.13 12.015 ;
     RECT  5.4 11.88 7.56 12.015 ;
     RECT  9.72 11.88 9.99 12.015 ;
     RECT  10.044 11.88 10.314 12.015 ;
     RECT  11.502 11.88 11.772 12.015 ;
     RECT  19.494 11.88 20.034 12.015 ;
     RECT  20.304 11.88 21.168 12.015 ;
     RECT  21.222 11.88 21.492 12.015 ;
     RECT  21.546 11.88 21.87 12.015 ;
     RECT  21.924 11.88 22.356 12.015 ;
     RECT  22.464 11.88 23.166 12.015 ;
     RECT  23.274 11.88 23.544 12.015 ;
     RECT  23.652 11.88 23.76 12.015 ;
     RECT  2.16 12.285 3.51 12.42 ;
     RECT  3.78 12.285 4.212 12.42 ;
     RECT  4.428 12.285 6.588 12.42 ;
     RECT  7.56 12.285 8.64 12.42 ;
     RECT  19.602 12.285 19.926 12.42 ;
     RECT  19.98 12.285 22.68 12.42 ;
     RECT  22.896 12.285 23.328 12.42 ;
     RECT  23.382 12.285 23.76 12.42 ;
     RECT  2.16 12.42 2.538 12.555 ;
     RECT  2.592 12.42 2.862 12.555 ;
     RECT  2.916 12.42 3.348 12.555 ;
     RECT  3.402 12.42 4.752 12.555 ;
     RECT  4.806 12.42 6.426 12.555 ;
     RECT  6.858 12.42 9.018 12.555 ;
     RECT  10.26 12.285 10.53 12.555 ;
     RECT  13.446 12.42 13.986 12.555 ;
     RECT  19.602 12.42 23.76 12.555 ;
     RECT  2.16 12.825 2.538 12.96 ;
     RECT  2.808 12.825 3.078 12.96 ;
     RECT  3.834 12.825 4.104 12.96 ;
     RECT  4.914 12.825 6.102 12.96 ;
     RECT  6.318 12.825 7.398 12.96 ;
     RECT  14.958 12.825 15.228 12.96 ;
     RECT  16.254 12.825 16.524 12.96 ;
     RECT  19.116 12.825 19.656 12.96 ;
     RECT  20.034 12.825 23.112 12.96 ;
     RECT  23.22 12.825 23.76 12.96 ;
     RECT  2.16 12.96 2.268 13.095 ;
     RECT  2.322 12.96 3.996 13.095 ;
     RECT  4.104 12.96 5.184 13.095 ;
     RECT  5.292 12.96 6.372 13.095 ;
     RECT  7.074 12.96 8.154 13.095 ;
     RECT  9.828 12.96 10.098 13.095 ;
     RECT  10.854 12.96 11.124 13.095 ;
     RECT  11.502 12.96 11.772 13.095 ;
     RECT  18.198 12.96 18.63 13.095 ;
     RECT  19.062 12.96 23.76 13.095 ;
     RECT  2.16 13.365 2.268 13.5 ;
     RECT  2.538 13.365 2.808 13.5 ;
     RECT  3.078 13.365 3.348 13.5 ;
     RECT  3.564 13.365 7.668 13.5 ;
     RECT  8.046 13.365 9.666 13.5 ;
     RECT  10.422 13.365 10.692 13.5 ;
     RECT  12.906 13.365 13.176 13.5 ;
     RECT  19.332 13.365 19.872 13.5 ;
     RECT  19.926 13.365 20.25 13.5 ;
     RECT  20.304 13.365 20.628 13.5 ;
     RECT  20.682 13.365 23.76 13.5 ;
     RECT  2.16 13.5 3.672 13.635 ;
     RECT  3.726 13.5 7.398 13.635 ;
     RECT  10.152 13.5 10.422 13.635 ;
     RECT  11.772 13.5 12.042 13.635 ;
     RECT  19.116 13.5 19.548 13.635 ;
     RECT  19.818 13.5 20.142 13.635 ;
     RECT  20.196 13.5 22.464 13.635 ;
     RECT  22.572 13.5 23.274 13.635 ;
     RECT  23.652 13.5 23.76 13.635 ;
     RECT  2.16 13.905 2.268 14.04 ;
     RECT  2.538 13.905 2.808 14.04 ;
     RECT  2.862 13.905 5.076 14.04 ;
     RECT  5.616 13.905 6.048 14.04 ;
     RECT  7.506 13.905 8.586 14.04 ;
     RECT  9.288 13.905 9.558 14.04 ;
     RECT  9.828 13.905 10.098 14.04 ;
     RECT  11.61 13.905 11.88 14.04 ;
     RECT  19.116 13.905 19.656 14.04 ;
     RECT  19.71 13.905 20.142 14.04 ;
     RECT  20.196 13.905 22.626 14.04 ;
     RECT  22.734 13.905 23.598 14.04 ;
     RECT  2.16 14.04 3.078 14.175 ;
     RECT  3.294 14.04 5.508 14.175 ;
     RECT  5.886 14.04 6.156 14.175 ;
     RECT  6.21 14.04 8.37 14.175 ;
     RECT  9.018 14.04 9.288 14.175 ;
     RECT  19.17 14.04 19.818 14.175 ;
     RECT  19.926 14.04 20.466 14.175 ;
     RECT  20.52 14.04 20.952 14.175 ;
     RECT  21.006 14.04 21.546 14.175 ;
     RECT  21.6 14.04 23.112 14.175 ;
     RECT  23.166 14.04 23.598 14.175 ;
     RECT  23.652 13.905 23.76 14.175 ;
     RECT  2.16 14.445 2.808 14.58 ;
     RECT  2.916 14.445 3.78 14.58 ;
     RECT  4.482 14.445 4.914 14.58 ;
     RECT  5.184 14.445 7.344 14.58 ;
     RECT  9.828 14.445 10.098 14.58 ;
     RECT  11.61 14.445 11.88 14.58 ;
     RECT  18.63 14.445 18.954 14.58 ;
     RECT  19.062 14.445 22.896 14.58 ;
     RECT  22.95 14.445 23.544 14.58 ;
     RECT  23.652 14.445 23.76 14.58 ;
     RECT  2.16 14.58 2.268 14.715 ;
     RECT  2.538 14.58 5.832 14.715 ;
     RECT  6.048 14.58 7.398 14.715 ;
     RECT  8.046 14.58 9.126 14.715 ;
     RECT  10.098 14.58 10.368 14.715 ;
     RECT  10.8 14.58 11.07 14.715 ;
     RECT  12.312 14.58 12.582 14.715 ;
     RECT  18.846 14.58 20.358 14.715 ;
     RECT  20.466 14.58 22.572 14.715 ;
     RECT  22.626 14.58 23.76 14.715 ;
     RECT  2.16 14.985 3.942 15.12 ;
     RECT  3.996 14.985 4.86 15.12 ;
     RECT  5.076 14.985 7.344 15.12 ;
     RECT  11.07 14.985 11.34 15.12 ;
     RECT  12.528 14.985 12.798 15.12 ;
     RECT  16.146 14.985 16.416 15.12 ;
     RECT  18.846 14.985 20.142 15.12 ;
     RECT  20.25 14.985 21.762 15.12 ;
     RECT  21.87 14.985 23.436 15.12 ;
     RECT  23.652 14.985 23.76 15.12 ;
     RECT  2.16 15.12 2.808 15.255 ;
     RECT  2.97 15.12 5.184 15.255 ;
     RECT  5.346 15.12 7.506 15.255 ;
     RECT  7.668 15.12 8.748 15.255 ;
     RECT  10.152 15.12 10.422 15.255 ;
     RECT  13.176 14.985 13.446 15.255 ;
     RECT  17.712 15.12 17.982 15.255 ;
     RECT  18.738 15.12 20.142 15.255 ;
     RECT  20.25 15.12 23.76 15.255 ;
     RECT  2.16 15.525 3.51 15.66 ;
     RECT  3.726 15.525 6.75 15.66 ;
     RECT  7.776 15.525 8.964 15.66 ;
     RECT  13.122 15.525 13.392 15.66 ;
     RECT  14.526 15.525 14.796 15.66 ;
     RECT  18.36 15.525 18.9 15.66 ;
     RECT  19.008 15.525 19.764 15.66 ;
     RECT  19.926 15.525 22.572 15.66 ;
     RECT  22.788 15.525 23.76 15.66 ;
     RECT  2.16 15.66 2.268 15.795 ;
     RECT  2.538 15.66 3.078 15.795 ;
     RECT  3.24 15.66 3.51 15.795 ;
     RECT  3.726 15.66 5.346 15.795 ;
     RECT  5.67 15.66 8.91 15.795 ;
     RECT  12.528 15.66 12.798 15.795 ;
     RECT  14.094 15.66 14.364 15.795 ;
     RECT  18.468 15.66 18.792 15.795 ;
     RECT  18.846 15.66 19.71 15.795 ;
     RECT  19.764 15.66 20.088 15.795 ;
     RECT  20.142 15.66 23.544 15.795 ;
     RECT  23.652 15.66 23.76 15.795 ;
     RECT  3.24 16.065 3.51 16.2 ;
     RECT  3.78 16.065 4.644 16.2 ;
     RECT  4.914 16.065 5.994 16.2 ;
     RECT  6.048 16.065 7.128 16.2 ;
     RECT  14.094 16.065 14.634 16.2 ;
     RECT  18.576 16.065 19.44 16.2 ;
     RECT  19.656 16.065 20.196 16.2 ;
     RECT  20.25 16.065 21.924 16.2 ;
     RECT  22.032 16.065 22.842 16.2 ;
     RECT  22.896 16.065 23.328 16.2 ;
     RECT  23.382 16.065 23.76 16.2 ;
     RECT  2.16 16.065 3.078 16.335 ;
     RECT  3.132 16.2 3.564 16.335 ;
     RECT  3.726 16.2 5.778 16.335 ;
     RECT  6.75 16.2 7.83 16.335 ;
     RECT  8.046 16.2 9.126 16.335 ;
     RECT  14.31 16.2 14.58 16.335 ;
     RECT  15.714 16.2 15.984 16.335 ;
     RECT  18.684 16.2 19.224 16.335 ;
     RECT  19.278 16.2 19.602 16.335 ;
     RECT  19.656 16.2 19.98 16.335 ;
     RECT  20.034 16.2 20.79 16.335 ;
     RECT  20.898 16.2 21.438 16.335 ;
     RECT  21.492 16.2 22.518 16.335 ;
     RECT  22.572 16.2 23.166 16.335 ;
     RECT  23.22 16.2 23.76 16.335 ;
     RECT  2.16 16.605 2.538 16.74 ;
     RECT  2.916 16.605 6.372 16.74 ;
     RECT  6.966 16.605 8.046 16.74 ;
     RECT  12.042 16.605 12.312 16.74 ;
     RECT  12.96 16.605 13.23 16.74 ;
     RECT  18.576 16.605 18.9 16.74 ;
     RECT  18.954 16.605 19.818 16.74 ;
     RECT  19.872 16.605 20.412 16.74 ;
     RECT  20.466 16.605 23.112 16.74 ;
     RECT  23.22 16.605 23.76 16.74 ;
     RECT  2.16 16.74 5.184 16.875 ;
     RECT  5.4 16.74 7.83 16.875 ;
     RECT  15.066 16.74 15.336 16.875 ;
     RECT  16.038 16.74 16.308 16.875 ;
     RECT  16.686 16.74 16.956 16.875 ;
     RECT  18.414 16.74 20.574 16.875 ;
     RECT  20.682 16.74 23.544 16.875 ;
     RECT  23.652 16.74 23.76 16.875 ;
     RECT  2.16 17.145 3.24 17.28 ;
     RECT  3.294 17.145 3.996 17.28 ;
     RECT  4.05 17.145 4.914 17.28 ;
     RECT  4.968 17.145 5.4 17.28 ;
     RECT  5.832 17.145 7.992 17.28 ;
     RECT  8.046 17.145 9.126 17.28 ;
     RECT  9.882 17.145 10.152 17.28 ;
     RECT  10.206 17.145 10.476 17.28 ;
     RECT  13.122 17.145 13.392 17.28 ;
     RECT  14.904 17.145 15.174 17.28 ;
     RECT  15.39 17.145 15.66 17.28 ;
     RECT  18.414 17.145 19.278 17.28 ;
     RECT  19.494 17.145 20.034 17.28 ;
     RECT  20.088 17.145 20.52 17.28 ;
     RECT  20.574 17.145 22.464 17.28 ;
     RECT  22.572 17.145 23.112 17.28 ;
     RECT  23.22 17.145 23.76 17.28 ;
     RECT  2.16 17.28 3.942 17.415 ;
     RECT  4.104 17.28 5.616 17.415 ;
     RECT  5.67 17.28 7.83 17.415 ;
     RECT  8.208 17.28 9.288 17.415 ;
     RECT  10.962 17.28 11.232 17.415 ;
     RECT  11.286 17.28 11.556 17.415 ;
     RECT  13.932 17.28 14.202 17.415 ;
     RECT  18.09 17.28 19.278 17.415 ;
     RECT  19.332 17.28 19.656 17.415 ;
     RECT  19.71 17.28 22.842 17.415 ;
     RECT  22.95 17.28 23.76 17.415 ;
     RECT  2.16 17.685 3.348 17.82 ;
     RECT  3.402 17.685 3.672 17.82 ;
     RECT  3.78 17.685 4.212 17.82 ;
     RECT  4.536 17.685 5.616 17.82 ;
     RECT  5.67 17.685 6.318 17.82 ;
     RECT  6.696 17.685 8.856 17.82 ;
     RECT  8.91 17.685 9.18 17.82 ;
     RECT  11.826 17.685 12.096 17.82 ;
     RECT  18.198 17.685 19.062 17.82 ;
     RECT  19.224 17.685 22.842 17.82 ;
     RECT  22.896 17.685 23.328 17.82 ;
     RECT  23.382 17.685 23.76 17.82 ;
     RECT  2.16 17.82 2.268 17.955 ;
     RECT  2.538 17.82 2.808 17.955 ;
     RECT  3.024 17.82 3.726 17.955 ;
     RECT  3.942 17.82 5.886 17.955 ;
     RECT  6.966 17.82 9.126 17.955 ;
     RECT  9.774 17.82 10.044 17.955 ;
     RECT  10.692 17.82 10.962 17.955 ;
     RECT  11.772 17.82 12.042 17.955 ;
     RECT  18.414 17.82 20.25 17.955 ;
     RECT  20.304 17.82 22.95 17.955 ;
     RECT  23.058 17.82 23.49 17.955 ;
     RECT  23.652 17.82 23.76 17.955 ;
     RECT  2.16 18.225 4.266 18.36 ;
     RECT  4.536 18.225 5.616 18.36 ;
     RECT  5.778 18.225 7.938 18.36 ;
     RECT  11.448 18.225 11.718 18.36 ;
     RECT  18.36 18.225 18.684 18.36 ;
     RECT  18.738 18.225 19.494 18.36 ;
     RECT  19.548 18.225 20.088 18.36 ;
     RECT  20.142 18.225 23.22 18.36 ;
     RECT  23.328 18.225 23.598 18.36 ;
     RECT  2.16 18.36 2.808 18.495 ;
     RECT  2.862 18.36 4.806 18.495 ;
     RECT  5.67 18.36 6.858 18.495 ;
     RECT  9.504 18.36 9.774 18.495 ;
     RECT  11.664 18.36 11.934 18.495 ;
     RECT  12.15 18.36 12.42 18.495 ;
     RECT  18.522 18.36 19.386 18.495 ;
     RECT  19.44 18.36 20.412 18.495 ;
     RECT  20.466 18.36 23.004 18.495 ;
     RECT  23.112 18.36 23.544 18.495 ;
     RECT  23.652 18.225 23.76 18.495 ;
     RECT  2.16 18.765 3.672 18.9 ;
     RECT  3.942 18.765 5.022 18.9 ;
     RECT  5.4 18.765 6.75 18.9 ;
     RECT  6.858 18.765 7.938 18.9 ;
     RECT  8.046 18.765 8.316 18.9 ;
     RECT  8.586 18.765 8.856 18.9 ;
     RECT  10.53 18.765 10.8 18.9 ;
     RECT  17.82 18.765 22.68 18.9 ;
     RECT  22.788 18.765 23.76 18.9 ;
     RECT  2.16 18.9 4.374 19.035 ;
     RECT  4.59 18.9 5.022 19.035 ;
     RECT  5.67 18.9 7.83 19.035 ;
     RECT  8.046 18.9 9.396 19.035 ;
     RECT  16.038 18.9 16.308 19.035 ;
     RECT  18.252 18.9 19.764 19.035 ;
     RECT  19.872 18.9 23.544 19.035 ;
     RECT  23.652 18.9 23.76 19.035 ;
     RECT  2.808 19.305 3.78 19.44 ;
     RECT  3.942 19.305 4.374 19.44 ;
     RECT  5.022 19.305 5.454 19.44 ;
     RECT  6.966 19.305 8.046 19.44 ;
     RECT  10.206 19.305 10.476 19.44 ;
     RECT  10.584 19.305 10.854 19.44 ;
     RECT  15.12 19.305 15.39 19.44 ;
     RECT  18.252 19.305 18.576 19.44 ;
     RECT  18.684 19.305 19.008 19.44 ;
     RECT  19.17 19.305 23.112 19.44 ;
     RECT  23.22 19.305 23.76 19.44 ;
     RECT  2.16 19.305 2.538 19.575 ;
     RECT  2.808 19.44 5.562 19.575 ;
     RECT  6.75 19.44 8.91 19.575 ;
     RECT  12.744 19.44 13.014 19.575 ;
     RECT  13.122 19.44 13.392 19.575 ;
     RECT  17.982 19.44 18.306 19.575 ;
     RECT  18.63 19.44 23.598 19.575 ;
     RECT  23.652 19.44 23.76 19.575 ;
     RECT  2.16 19.845 3.78 19.98 ;
     RECT  4.212 19.845 4.482 19.98 ;
     RECT  5.076 19.845 6.588 19.98 ;
     RECT  8.316 19.845 9.396 19.98 ;
     RECT  11.826 19.845 12.096 19.98 ;
     RECT  14.202 19.845 14.472 19.98 ;
     RECT  17.874 19.845 18.414 19.98 ;
     RECT  18.792 19.845 20.844 19.98 ;
     RECT  20.952 19.845 23.76 19.98 ;
     RECT  2.16 19.98 3.24 20.115 ;
     RECT  3.294 19.98 7.398 20.115 ;
     RECT  7.614 19.98 8.694 20.115 ;
     RECT  12.258 19.98 12.798 20.115 ;
     RECT  13.554 19.98 13.824 20.115 ;
     RECT  15.282 19.98 15.552 20.115 ;
     RECT  18.036 19.98 18.576 20.115 ;
     RECT  18.63 19.98 21.006 20.115 ;
     RECT  21.06 19.98 23.76 20.115 ;
     RECT  2.16 20.385 3.672 20.52 ;
     RECT  3.78 20.385 4.212 20.52 ;
     RECT  4.428 20.385 5.508 20.52 ;
     RECT  6.912 20.385 7.992 20.52 ;
     RECT  12.366 20.385 12.636 20.52 ;
     RECT  16.2 20.385 16.47 20.52 ;
     RECT  17.658 20.385 17.982 20.52 ;
     RECT  18.09 20.385 18.846 20.52 ;
     RECT  19.116 20.385 19.44 20.52 ;
     RECT  19.548 20.385 20.628 20.52 ;
     RECT  20.736 20.385 23.76 20.52 ;
     RECT  2.16 20.52 6.534 20.655 ;
     RECT  6.912 20.52 9.072 20.655 ;
     RECT  9.882 20.52 10.152 20.655 ;
     RECT  11.664 20.52 11.934 20.655 ;
     RECT  14.958 20.52 15.228 20.655 ;
     RECT  18.306 20.52 19.71 20.655 ;
     RECT  19.818 20.52 20.142 20.655 ;
     RECT  20.25 20.52 20.79 20.655 ;
     RECT  20.844 20.52 23.76 20.655 ;
     RECT  2.16 20.925 3.672 21.06 ;
     RECT  3.888 20.925 6.48 21.06 ;
     RECT  9.018 20.925 9.288 21.06 ;
     RECT  10.422 20.925 10.962 21.06 ;
     RECT  13.824 20.925 14.094 21.06 ;
     RECT  18.198 20.925 19.494 21.06 ;
     RECT  19.602 20.925 19.926 21.06 ;
     RECT  19.98 20.925 23.436 21.06 ;
     RECT  2.16 21.06 2.538 21.195 ;
     RECT  2.592 21.06 4.536 21.195 ;
     RECT  4.644 21.06 5.076 21.195 ;
     RECT  5.13 21.06 5.562 21.195 ;
     RECT  5.886 21.06 6.966 21.195 ;
     RECT  7.992 21.06 9.072 21.195 ;
     RECT  11.124 21.06 11.394 21.195 ;
     RECT  16.2 21.06 16.47 21.195 ;
     RECT  17.982 21.06 18.63 21.195 ;
     RECT  18.684 21.06 20.52 21.195 ;
     RECT  20.574 21.06 21.114 21.195 ;
     RECT  21.222 21.06 23.598 21.195 ;
     RECT  23.652 20.925 23.76 21.195 ;
     RECT  2.16 21.465 3.402 21.6 ;
     RECT  3.564 21.465 3.834 21.6 ;
     RECT  3.888 21.465 5.4 21.6 ;
     RECT  5.724 21.465 6.372 21.6 ;
     RECT  6.48 21.465 7.56 21.6 ;
     RECT  11.718 21.465 11.988 21.6 ;
     RECT  15.39 21.465 15.66 21.6 ;
     RECT  17.442 21.465 17.712 21.6 ;
     RECT  18.036 21.465 18.9 21.6 ;
     RECT  18.954 21.465 19.494 21.6 ;
     RECT  19.548 21.465 20.088 21.6 ;
     RECT  20.142 21.465 21.762 21.6 ;
     RECT  21.816 21.465 23.112 21.6 ;
     RECT  2.16 21.6 3.078 21.735 ;
     RECT  3.294 21.6 7.398 21.735 ;
     RECT  11.016 21.6 11.286 21.735 ;
     RECT  15.174 21.6 15.444 21.735 ;
     RECT  18.522 21.6 19.71 21.735 ;
     RECT  19.764 21.6 21.492 21.735 ;
     RECT  21.546 21.6 23.112 21.735 ;
     RECT  23.22 21.465 23.76 21.735 ;
     RECT  2.16 22.005 3.672 22.14 ;
     RECT  3.726 22.005 3.996 22.14 ;
     RECT  4.158 22.005 5.238 22.14 ;
     RECT  5.508 22.005 6.588 22.14 ;
     RECT  6.912 22.005 7.992 22.14 ;
     RECT  8.208 22.005 9.558 22.14 ;
     RECT  13.23 22.005 13.5 22.14 ;
     RECT  14.256 22.005 14.526 22.14 ;
     RECT  14.85 22.005 15.12 22.14 ;
     RECT  15.66 22.005 15.93 22.14 ;
     RECT  18.144 22.005 23.76 22.14 ;
     RECT  2.16 22.14 4.644 22.275 ;
     RECT  4.806 22.14 5.238 22.275 ;
     RECT  5.67 22.14 8.91 22.275 ;
     RECT  9.558 22.14 9.828 22.275 ;
     RECT  15.822 22.14 16.092 22.275 ;
     RECT  17.874 22.14 18.198 22.275 ;
     RECT  18.414 22.14 20.358 22.275 ;
     RECT  20.52 22.14 22.032 22.275 ;
     RECT  22.14 22.14 23.112 22.275 ;
     RECT  23.22 22.14 23.76 22.275 ;
     RECT  2.16 22.545 3.672 22.68 ;
     RECT  3.888 22.545 6.48 22.68 ;
     RECT  7.83 22.545 8.91 22.68 ;
     RECT  12.258 22.545 12.528 22.68 ;
     RECT  13.554 22.545 13.824 22.68 ;
     RECT  18.306 22.545 18.63 22.68 ;
     RECT  18.792 22.545 19.656 22.68 ;
     RECT  19.764 22.545 22.302 22.68 ;
     RECT  22.356 22.545 23.76 22.68 ;
     RECT  2.16 22.68 3.942 22.815 ;
     RECT  3.996 22.68 4.266 22.815 ;
     RECT  4.482 22.68 6.75 22.815 ;
     RECT  7.02 22.68 8.208 22.815 ;
     RECT  11.664 22.68 11.934 22.815 ;
     RECT  18.36 22.68 18.684 22.815 ;
     RECT  18.738 22.68 19.278 22.815 ;
     RECT  19.332 22.68 20.952 22.815 ;
     RECT  21.06 22.68 23.598 22.815 ;
     RECT  23.652 22.68 23.76 22.815 ;
     RECT  2.16 23.085 2.268 23.22 ;
     RECT  2.538 23.085 3.078 23.22 ;
     RECT  3.294 23.085 7.83 23.22 ;
     RECT  8.262 23.085 9.342 23.22 ;
     RECT  11.61 23.085 11.88 23.22 ;
     RECT  14.04 23.085 14.31 23.22 ;
     RECT  15.768 23.085 16.308 23.22 ;
     RECT  18.306 23.085 18.846 23.22 ;
     RECT  18.9 23.085 19.224 23.22 ;
     RECT  19.332 23.085 20.088 23.22 ;
     RECT  20.142 23.085 23.76 23.22 ;
     RECT  2.16 23.22 3.672 23.355 ;
     RECT  3.78 23.22 6.372 23.355 ;
     RECT  7.506 23.22 8.586 23.355 ;
     RECT  10.854 23.22 11.124 23.355 ;
     RECT  12.528 23.085 12.798 23.355 ;
     RECT  18.144 23.22 19.548 23.355 ;
     RECT  19.818 23.22 23.76 23.355 ;
     RECT  2.16 23.625 2.268 23.76 ;
     RECT  2.808 23.625 3.618 23.76 ;
     RECT  3.996 23.625 5.94 23.76 ;
     RECT  6.21 23.625 7.29 23.76 ;
     RECT  7.83 23.625 8.91 23.76 ;
     RECT  14.58 23.625 14.85 23.76 ;
     RECT  16.848 23.625 17.388 23.76 ;
     RECT  17.928 23.625 19.224 23.76 ;
     RECT  19.332 23.625 19.764 23.76 ;
     RECT  19.818 23.625 22.95 23.76 ;
     RECT  23.22 23.625 23.76 23.76 ;
     RECT  2.16 23.76 3.78 23.895 ;
     RECT  3.996 23.76 6.588 23.895 ;
     RECT  7.668 23.76 8.748 23.895 ;
     RECT  10.692 23.76 10.962 23.895 ;
     RECT  13.77 23.76 14.31 23.895 ;
     RECT  18.252 23.76 18.576 23.895 ;
     RECT  18.63 23.76 19.062 23.895 ;
     RECT  19.116 23.76 19.764 23.895 ;
     RECT  19.818 23.76 21.06 23.895 ;
     RECT  21.168 23.76 22.302 23.895 ;
     RECT  22.356 23.76 23.76 23.895 ;
     RECT  2.16 24.165 2.538 24.3 ;
     RECT  2.808 24.165 3.51 24.3 ;
     RECT  4.212 24.165 4.644 24.3 ;
     RECT  5.292 24.165 7.452 24.3 ;
     RECT  7.992 24.165 8.262 24.3 ;
     RECT  12.042 24.165 12.312 24.3 ;
     RECT  16.416 24.165 16.686 24.3 ;
     RECT  17.82 24.165 18.36 24.3 ;
     RECT  18.468 24.165 18.792 24.3 ;
     RECT  18.846 24.165 19.386 24.3 ;
     RECT  19.494 24.165 19.818 24.3 ;
     RECT  19.872 24.165 20.736 24.3 ;
     RECT  20.79 24.165 22.086 24.3 ;
     RECT  22.14 24.165 23.112 24.3 ;
     RECT  23.166 24.165 23.598 24.3 ;
     RECT  2.16 24.3 6.966 24.435 ;
     RECT  8.046 24.3 9.126 24.435 ;
     RECT  13.392 24.3 13.662 24.435 ;
     RECT  17.874 24.3 18.144 24.435 ;
     RECT  18.36 24.3 20.088 24.435 ;
     RECT  20.142 24.3 22.626 24.435 ;
     RECT  22.68 24.3 23.544 24.435 ;
     RECT  23.652 24.165 23.76 24.435 ;
     RECT  2.16 24.705 4.482 24.84 ;
     RECT  4.752 24.705 7.344 24.84 ;
     RECT  14.148 24.705 14.688 24.84 ;
     RECT  15.39 24.705 15.66 24.84 ;
     RECT  16.092 24.705 16.362 24.84 ;
     RECT  17.658 24.705 18.522 24.84 ;
     RECT  18.576 24.705 19.008 24.84 ;
     RECT  19.062 24.705 19.602 24.84 ;
     RECT  19.656 24.705 20.52 24.84 ;
     RECT  20.574 24.705 23.166 24.84 ;
     RECT  23.22 24.705 23.76 24.84 ;
     RECT  2.16 24.84 3.672 24.975 ;
     RECT  3.888 24.84 5.832 24.975 ;
     RECT  6.426 24.84 7.506 24.975 ;
     RECT  8.316 24.84 9.396 24.975 ;
     RECT  13.716 24.84 13.986 24.975 ;
     RECT  14.526 24.84 14.796 24.975 ;
     RECT  15.336 24.84 15.606 24.975 ;
     RECT  18.036 24.84 18.468 24.975 ;
     RECT  18.792 24.84 20.412 24.975 ;
     RECT  20.466 24.84 22.194 24.975 ;
     RECT  22.248 24.84 23.76 24.975 ;
     RECT  2.16 25.245 4.752 25.38 ;
     RECT  4.86 25.245 5.292 25.38 ;
     RECT  6.048 25.245 7.128 25.38 ;
     RECT  9.828 25.245 10.098 25.38 ;
     RECT  18.252 25.245 18.576 25.38 ;
     RECT  18.792 25.245 23.544 25.38 ;
     RECT  23.652 25.245 23.76 25.38 ;
     RECT  2.16 25.38 5.184 25.515 ;
     RECT  5.94 25.38 6.588 25.515 ;
     RECT  6.75 25.38 7.83 25.515 ;
     RECT  7.938 25.38 9.018 25.515 ;
     RECT  12.312 25.38 12.582 25.515 ;
     RECT  15.066 25.38 15.336 25.515 ;
     RECT  16.956 25.38 17.226 25.515 ;
     RECT  18.306 25.38 18.576 25.515 ;
     RECT  18.684 25.38 19.872 25.515 ;
     RECT  19.926 25.38 23.22 25.515 ;
     RECT  23.382 25.38 23.76 25.515 ;
     RECT  2.16 25.785 2.808 25.92 ;
     RECT  3.078 25.785 4.05 25.92 ;
     RECT  4.104 25.785 5.184 25.92 ;
     RECT  5.238 25.785 6.318 25.92 ;
     RECT  6.48 25.785 7.56 25.92 ;
     RECT  14.796 25.785 15.066 25.92 ;
     RECT  15.714 25.785 15.984 25.92 ;
     RECT  17.712 25.785 18.036 25.92 ;
     RECT  18.306 25.785 18.576 25.92 ;
     RECT  18.63 25.785 18.954 25.92 ;
     RECT  19.008 25.785 20.196 25.92 ;
     RECT  20.304 25.785 23.544 25.92 ;
     RECT  23.652 25.785 23.76 25.92 ;
     RECT  2.16 25.92 3.348 26.055 ;
     RECT  3.51 25.92 3.78 26.055 ;
     RECT  4.266 25.92 5.562 26.055 ;
     RECT  5.886 25.92 8.046 26.055 ;
     RECT  17.01 25.92 17.55 26.055 ;
     RECT  18.306 25.92 19.926 26.055 ;
     RECT  20.034 25.92 21.924 26.055 ;
     RECT  22.086 25.92 23.76 26.055 ;
     RECT  2.16 26.325 2.268 26.46 ;
     RECT  2.538 26.325 4.374 26.46 ;
     RECT  4.536 26.325 5.616 26.46 ;
     RECT  5.886 26.325 9.126 26.46 ;
     RECT  16.038 26.325 16.308 26.46 ;
     RECT  17.55 26.325 17.82 26.46 ;
     RECT  18.252 26.325 18.792 26.46 ;
     RECT  18.846 26.325 19.386 26.46 ;
     RECT  19.44 26.325 22.788 26.46 ;
     RECT  22.842 26.325 23.112 26.46 ;
     RECT  2.16 26.46 2.97 26.595 ;
     RECT  3.186 26.46 4.482 26.595 ;
     RECT  5.508 26.46 6.588 26.595 ;
     RECT  7.02 26.46 9.18 26.595 ;
     RECT  9.234 26.46 9.504 26.595 ;
     RECT  10.8 26.46 11.07 26.595 ;
     RECT  12.636 26.46 12.906 26.595 ;
     RECT  14.85 26.46 15.12 26.595 ;
     RECT  17.874 26.46 19.008 26.595 ;
     RECT  19.062 26.46 19.386 26.595 ;
     RECT  19.494 26.46 19.818 26.595 ;
     RECT  20.034 26.46 20.466 26.595 ;
     RECT  20.52 26.46 22.14 26.595 ;
     RECT  22.194 26.46 23.166 26.595 ;
     RECT  23.22 26.325 23.76 26.595 ;
     RECT  2.484 26.865 2.754 27 ;
     RECT  2.916 26.865 3.78 27 ;
     RECT  5.724 26.865 7.884 27 ;
     RECT  13.932 26.865 14.202 27 ;
     RECT  16.794 26.865 17.064 27 ;
     RECT  17.874 26.865 18.144 27 ;
     RECT  18.306 26.865 22.734 27 ;
     RECT  22.896 26.865 23.598 27 ;
     RECT  2.16 26.865 2.268 27.135 ;
     RECT  2.538 27 3.78 27.135 ;
     RECT  3.996 26.865 5.508 27.135 ;
     RECT  5.994 27 7.182 27.135 ;
     RECT  8.316 27 9.396 27.135 ;
     RECT  12.96 27 13.23 27.135 ;
     RECT  18.414 27 18.846 27.135 ;
     RECT  18.954 27 21.384 27.135 ;
     RECT  21.492 27 23.436 27.135 ;
     RECT  23.652 26.865 23.76 27.135 ;
     RECT  2.16 27.405 5.292 27.54 ;
     RECT  5.67 27.405 6.75 27.54 ;
     RECT  6.966 27.405 9.126 27.54 ;
     RECT  9.72 27.405 9.99 27.54 ;
     RECT  11.286 27.405 11.556 27.54 ;
     RECT  16.038 27.405 16.308 27.54 ;
     RECT  18.576 27.405 19.44 27.54 ;
     RECT  19.764 27.405 20.628 27.54 ;
     RECT  20.736 27.405 23.76 27.54 ;
     RECT  2.16 27.54 3.24 27.675 ;
     RECT  3.888 27.54 4.32 27.675 ;
     RECT  4.806 27.54 5.67 27.675 ;
     RECT  5.994 27.54 6.21 27.675 ;
     RECT  14.904 27.54 15.174 27.675 ;
     RECT  18.63 27.54 18.954 27.675 ;
     RECT  19.062 27.54 20.25 27.675 ;
     RECT  20.358 27.54 23.112 27.675 ;
     RECT  23.22 27.54 23.76 27.675 ;
     RECT  2.16 27.945 5.454 28.08 ;
     RECT  5.616 27.945 6.696 28.08 ;
     RECT  7.02 27.945 8.1 28.08 ;
     RECT  10.908 27.945 11.178 28.08 ;
     RECT  13.068 27.945 13.338 28.08 ;
     RECT  17.442 27.945 17.712 28.08 ;
     RECT  19.116 27.945 19.656 28.08 ;
     RECT  19.71 27.945 20.142 28.08 ;
     RECT  20.25 27.945 20.682 28.08 ;
     RECT  20.736 27.945 21.6 28.08 ;
     RECT  21.708 27.945 22.518 28.08 ;
     RECT  22.734 27.945 23.166 28.08 ;
     RECT  23.22 27.945 23.76 28.08 ;
     RECT  2.16 28.08 3.24 28.215 ;
     RECT  3.348 28.08 3.78 28.215 ;
     RECT  3.942 28.08 8.694 28.215 ;
     RECT  11.178 28.08 11.448 28.215 ;
     RECT  15.498 28.08 15.768 28.215 ;
     RECT  17.874 28.08 18.144 28.215 ;
     RECT  19.008 28.08 19.656 28.215 ;
     RECT  19.71 28.08 21.114 28.215 ;
     RECT  21.222 28.08 21.978 28.215 ;
     RECT  22.086 28.08 23.76 28.215 ;
     RECT  2.16 28.485 2.268 28.62 ;
     RECT  2.322 28.485 7.668 28.62 ;
     RECT  8.046 28.485 9.396 28.62 ;
     RECT  15.552 28.485 15.822 28.62 ;
     RECT  16.254 28.485 16.524 28.62 ;
     RECT  16.794 28.485 17.064 28.62 ;
     RECT  18.954 28.485 19.278 28.62 ;
     RECT  19.44 28.485 22.356 28.62 ;
     RECT  22.464 28.485 23.166 28.62 ;
     RECT  23.22 28.485 23.76 28.62 ;
     RECT  2.16 28.62 4.59 28.755 ;
     RECT  5.832 28.62 6.912 28.755 ;
     RECT  7.722 28.62 8.154 28.755 ;
     RECT  13.068 28.62 13.338 28.755 ;
     RECT  18.846 28.62 19.656 28.755 ;
     RECT  19.71 28.62 20.142 28.755 ;
     RECT  20.196 28.62 20.79 28.755 ;
     RECT  20.844 28.62 21.384 28.755 ;
     RECT  21.438 28.62 23.76 28.755 ;
     RECT  2.16 29.025 3.78 29.16 ;
     RECT  3.888 29.025 4.59 29.16 ;
     RECT  5.022 29.025 5.454 29.16 ;
     RECT  6.75 29.025 7.83 29.16 ;
     RECT  14.796 29.025 15.336 29.16 ;
     RECT  15.66 29.025 16.2 29.16 ;
     RECT  18.576 29.025 18.9 29.16 ;
     RECT  18.954 29.025 19.278 29.16 ;
     RECT  19.44 29.025 23.328 29.16 ;
     RECT  23.382 29.025 23.76 29.16 ;
     RECT  2.16 29.16 3.672 29.295 ;
     RECT  3.78 29.16 4.212 29.295 ;
     RECT  4.266 29.16 5.346 29.295 ;
     RECT  7.938 29.16 9.018 29.295 ;
     RECT  13.338 29.16 13.608 29.295 ;
     RECT  14.202 29.16 14.472 29.295 ;
     RECT  14.688 29.16 14.958 29.295 ;
     RECT  19.116 29.16 20.844 29.295 ;
     RECT  20.898 29.16 23.058 29.295 ;
     RECT  23.22 29.16 23.76 29.295 ;
     RECT  2.16 29.565 5.022 29.7 ;
     RECT  5.616 29.565 6.696 29.7 ;
     RECT  6.804 29.565 8.964 29.7 ;
     RECT  14.418 29.565 14.688 29.7 ;
     RECT  14.904 29.565 15.174 29.7 ;
     RECT  18.09 29.565 18.36 29.7 ;
     RECT  19.008 29.565 21.276 29.7 ;
     RECT  21.33 29.565 22.842 29.7 ;
     RECT  22.95 29.565 23.76 29.7 ;
     RECT  2.16 29.7 2.538 29.835 ;
     RECT  2.7 29.7 2.97 29.835 ;
     RECT  3.24 29.7 3.51 29.835 ;
     RECT  3.942 29.7 4.374 29.835 ;
     RECT  5.292 29.7 6.372 29.835 ;
     RECT  6.966 29.7 8.046 29.835 ;
     RECT  8.1 29.7 9.18 29.835 ;
     RECT  11.61 29.7 11.88 29.835 ;
     RECT  17.388 29.7 17.658 29.835 ;
     RECT  19.386 29.7 19.71 29.835 ;
     RECT  19.764 29.7 21.816 29.835 ;
     RECT  21.924 29.7 23.22 29.835 ;
     RECT  23.328 29.7 23.598 29.835 ;
     RECT  23.652 29.7 23.76 29.835 ;
     RECT  2.16 30.105 2.808 30.24 ;
     RECT  3.456 30.105 3.888 30.24 ;
     RECT  4.536 30.105 6.696 30.24 ;
     RECT  6.966 30.105 8.046 30.24 ;
     RECT  8.154 30.105 9.234 30.24 ;
     RECT  10.746 30.105 11.016 30.24 ;
     RECT  14.364 30.105 14.634 30.24 ;
     RECT  15.498 30.105 15.768 30.24 ;
     RECT  16.308 30.105 16.578 30.24 ;
     RECT  19.386 30.105 19.71 30.24 ;
     RECT  19.764 30.105 20.088 30.24 ;
     RECT  20.142 30.105 21.654 30.24 ;
     RECT  21.708 30.105 23.76 30.24 ;
     RECT  2.16 30.24 3.51 30.375 ;
     RECT  3.888 30.24 4.158 30.375 ;
     RECT  4.32 30.24 4.752 30.375 ;
     RECT  5.67 30.24 6.75 30.375 ;
     RECT  7.02 30.24 8.1 30.375 ;
     RECT  12.636 30.24 12.906 30.375 ;
     RECT  13.5 30.24 13.77 30.375 ;
     RECT  19.17 30.24 19.71 30.375 ;
     RECT  19.872 30.24 20.844 30.375 ;
     RECT  20.898 30.24 22.086 30.375 ;
     RECT  22.14 30.24 23.544 30.375 ;
     RECT  23.652 30.24 23.76 30.375 ;
     RECT  2.16 30.645 2.268 30.78 ;
     RECT  2.322 30.645 2.592 30.78 ;
     RECT  2.7 30.645 3.132 30.78 ;
     RECT  3.402 30.645 3.672 30.78 ;
     RECT  3.834 30.645 4.266 30.78 ;
     RECT  4.536 30.645 6.156 30.78 ;
     RECT  7.722 30.645 8.91 30.78 ;
     RECT  13.824 30.645 14.094 30.78 ;
     RECT  14.904 30.645 15.174 30.78 ;
     RECT  17.928 30.645 18.36 30.78 ;
     RECT  19.386 30.645 22.896 30.78 ;
     RECT  22.95 30.645 23.22 30.78 ;
     RECT  23.652 30.645 23.76 30.78 ;
     RECT  2.16 30.78 3.672 30.915 ;
     RECT  4.05 30.78 4.482 30.915 ;
     RECT  5.4 30.78 6.48 30.915 ;
     RECT  7.938 30.78 9.018 30.915 ;
     RECT  12.852 30.78 13.122 30.915 ;
     RECT  13.23 30.78 13.5 30.915 ;
     RECT  19.44 30.78 20.898 30.915 ;
     RECT  21.006 30.78 21.33 30.915 ;
     RECT  21.384 30.78 21.654 30.915 ;
     RECT  21.816 30.78 22.788 30.915 ;
     RECT  22.95 30.78 23.76 30.915 ;
     RECT  2.16 31.185 2.808 31.32 ;
     RECT  3.24 31.185 4.104 31.32 ;
     RECT  4.428 31.185 7.668 31.32 ;
     RECT  10.368 31.185 10.638 31.32 ;
     RECT  12.582 31.185 13.122 31.32 ;
     RECT  14.742 31.185 15.012 31.32 ;
     RECT  19.278 31.185 20.682 31.32 ;
     RECT  20.736 31.185 21.708 31.32 ;
     RECT  21.762 31.185 22.734 31.32 ;
     RECT  22.842 31.185 23.112 31.32 ;
     RECT  23.22 31.185 23.76 31.32 ;
     RECT  2.16 31.32 2.97 31.455 ;
     RECT  3.51 31.32 6.534 31.455 ;
     RECT  8.046 31.185 9.126 31.455 ;
     RECT  12.636 31.32 12.906 31.455 ;
     RECT  13.608 31.32 13.878 31.455 ;
     RECT  19.548 31.32 19.872 31.455 ;
     RECT  20.142 31.32 20.682 31.455 ;
     RECT  20.736 31.32 21.492 31.455 ;
     RECT  21.654 31.32 23.76 31.455 ;
     RECT  2.16 31.725 3.24 31.86 ;
     RECT  3.402 31.725 3.834 31.86 ;
     RECT  3.996 31.725 7.236 31.86 ;
     RECT  12.69 31.725 12.96 31.86 ;
     RECT  13.77 31.725 14.31 31.86 ;
     RECT  14.796 31.725 15.066 31.86 ;
     RECT  19.656 31.725 22.194 31.86 ;
     RECT  22.248 31.725 23.004 31.86 ;
     RECT  23.112 31.725 23.544 31.86 ;
     RECT  23.652 31.725 23.76 31.86 ;
     RECT  2.16 31.86 2.268 31.995 ;
     RECT  2.862 31.86 3.402 31.995 ;
     RECT  3.51 31.86 4.914 31.995 ;
     RECT  5.184 31.86 8.424 31.995 ;
     RECT  12.528 31.86 12.798 31.995 ;
     RECT  12.96 31.86 13.23 31.995 ;
     RECT  19.926 31.86 20.682 31.995 ;
     RECT  20.736 31.86 21.762 31.995 ;
     RECT  21.816 31.86 22.788 31.995 ;
     RECT  22.896 31.86 23.76 31.995 ;
     RECT  2.646 32.265 3.078 32.4 ;
     RECT  3.402 32.265 5.562 32.4 ;
     RECT  5.778 32.265 7.938 32.4 ;
     RECT  10.26 32.265 10.53 32.4 ;
     RECT  11.88 32.265 12.15 32.4 ;
     RECT  13.932 32.265 14.202 32.4 ;
     RECT  15.66 32.265 15.93 32.4 ;
     RECT  19.926 32.265 20.466 32.4 ;
     RECT  20.52 32.265 22.518 32.4 ;
     RECT  22.572 32.265 23.274 32.4 ;
     RECT  23.382 32.265 23.76 32.4 ;
     RECT  2.16 32.265 2.538 32.535 ;
     RECT  3.024 32.4 3.294 32.535 ;
     RECT  4.32 32.4 6.48 32.535 ;
     RECT  6.966 32.4 8.046 32.535 ;
     RECT  10.962 32.4 11.232 32.535 ;
     RECT  13.392 32.4 13.662 32.535 ;
     RECT  13.878 32.4 14.148 32.535 ;
     RECT  19.818 32.4 20.79 32.535 ;
     RECT  20.898 32.4 21.222 32.535 ;
     RECT  21.33 32.4 21.6 32.535 ;
     RECT  21.654 32.4 23.76 32.535 ;
     RECT  2.16 32.805 2.97 32.94 ;
     RECT  3.024 32.805 3.456 32.94 ;
     RECT  3.618 32.805 4.05 32.94 ;
     RECT  4.482 32.805 4.914 32.94 ;
     RECT  7.182 32.805 8.262 32.94 ;
     RECT  13.014 32.805 13.284 32.94 ;
     RECT  20.25 32.805 23.328 32.94 ;
     RECT  23.382 32.805 23.76 32.94 ;
     RECT  2.16 32.94 2.808 33.075 ;
     RECT  3.24 32.94 4.32 33.075 ;
     RECT  4.428 32.94 5.508 33.075 ;
     RECT  6.048 32.94 7.128 33.075 ;
     RECT  8.208 32.94 9.288 33.075 ;
     RECT  12.312 32.94 12.582 33.075 ;
     RECT  13.284 32.94 13.554 33.075 ;
     RECT  18.144 32.94 18.414 33.075 ;
     RECT  20.25 32.94 23.544 33.075 ;
     RECT  23.652 32.94 23.76 33.075 ;
     RECT  2.16 33.345 2.268 33.48 ;
     RECT  2.376 33.345 2.646 33.48 ;
     RECT  2.916 33.345 3.456 33.48 ;
     RECT  3.51 33.345 4.374 33.48 ;
     RECT  4.806 33.345 5.238 33.48 ;
     RECT  5.508 33.345 6.588 33.48 ;
     RECT  6.966 33.345 8.046 33.48 ;
     RECT  8.586 33.345 8.856 33.48 ;
     RECT  11.286 33.345 11.556 33.48 ;
     RECT  20.412 33.345 22.41 33.48 ;
     RECT  22.464 33.345 23.166 33.48 ;
     RECT  23.22 33.345 23.76 33.48 ;
     RECT  2.16 33.48 3.672 33.615 ;
     RECT  3.726 33.48 5.238 33.615 ;
     RECT  6.966 33.48 9.126 33.615 ;
     RECT  9.18 33.48 9.45 33.615 ;
     RECT  14.526 33.48 15.066 33.615 ;
     RECT  19.224 33.48 19.656 33.615 ;
     RECT  20.412 33.48 21.384 33.615 ;
     RECT  21.438 33.48 23.274 33.615 ;
     RECT  23.382 33.48 23.76 33.615 ;
     RECT  2.16 33.885 2.808 34.02 ;
     RECT  3.024 33.885 3.726 34.02 ;
     RECT  4.158 33.885 4.59 34.02 ;
     RECT  5.346 33.885 5.616 34.02 ;
     RECT  6.696 33.885 8.856 34.02 ;
     RECT  9.396 33.885 9.666 34.02 ;
     RECT  12.042 33.885 12.312 34.02 ;
     RECT  12.852 33.885 13.122 34.02 ;
     RECT  13.662 33.885 13.932 34.02 ;
     RECT  20.79 33.885 23.166 34.02 ;
     RECT  2.16 34.02 2.538 34.155 ;
     RECT  2.97 34.02 3.672 34.155 ;
     RECT  4.482 34.02 4.914 34.155 ;
     RECT  5.616 34.02 6.696 34.155 ;
     RECT  7.938 34.02 9.018 34.155 ;
     RECT  12.312 34.02 12.582 34.155 ;
     RECT  20.25 34.02 20.844 34.155 ;
     RECT  20.952 34.02 23.166 34.155 ;
     RECT  23.22 33.885 23.76 34.155 ;
     RECT  2.16 34.425 3.564 34.56 ;
     RECT  3.78 34.425 5.292 34.56 ;
     RECT  20.304 34.425 23.76 34.56 ;
     RECT  2.16 34.56 2.538 34.695 ;
     RECT  3.024 34.56 3.294 34.695 ;
     RECT  3.618 34.56 4.05 34.695 ;
     RECT  4.212 34.56 4.644 34.695 ;
     RECT  4.914 34.56 5.994 34.695 ;
     RECT  20.412 34.56 20.736 34.695 ;
     RECT  21.06 34.56 22.194 34.695 ;
     RECT  22.356 34.56 23.76 34.695 ;
     RECT  2.16 34.965 2.268 35.1 ;
     RECT  2.646 34.965 2.916 35.1 ;
     RECT  3.078 34.965 3.51 35.1 ;
     RECT  3.618 34.965 4.05 35.1 ;
     RECT  4.212 34.965 4.644 35.1 ;
     RECT  20.574 34.965 22.086 35.1 ;
     RECT  22.194 34.965 23.76 35.1 ;
     RECT  2.16 35.1 2.538 35.235 ;
     RECT  3.51 35.1 4.374 35.235 ;
     RECT  20.79 35.1 22.464 35.235 ;
     RECT  22.518 35.1 22.788 35.235 ;
     RECT  22.95 35.1 23.49 35.235 ;
     RECT  23.652 35.1 23.76 35.235 ;
     RECT  2.16 35.505 2.538 35.64 ;
     RECT  2.754 35.505 3.024 35.64 ;
     RECT  3.672 35.505 4.104 35.64 ;
     RECT  21.33 35.505 23.382 35.64 ;
     RECT  23.652 35.505 23.76 35.64 ;
     RECT  2.16 35.64 2.268 35.775 ;
     RECT  3.24 35.64 3.51 35.775 ;
     RECT  20.52 35.64 21.06 35.775 ;
     RECT  21.384 35.64 23.76 35.775 ;
     RECT  3.132 36.045 3.402 36.18 ;
     RECT  20.79 36.045 22.626 36.18 ;
     RECT  22.68 36.045 23.76 36.18 ;
     RECT  2.16 36.045 2.268 36.315 ;
     RECT  3.078 36.18 3.78 36.315 ;
     RECT  20.682 36.18 23.166 36.315 ;
     RECT  23.22 36.18 23.76 36.315 ;
     RECT  21.114 36.585 22.95 36.72 ;
     RECT  23.112 36.585 23.544 36.72 ;
     RECT  2.16 36.585 2.268 36.855 ;
     RECT  20.952 36.72 23.544 36.855 ;
     RECT  23.652 36.585 23.76 36.855 ;
     RECT  20.952 37.125 23.544 37.26 ;
     RECT  23.652 37.125 23.76 37.26 ;
     RECT  2.16 37.125 2.268 37.395 ;
     RECT  20.898 37.26 21.33 37.395 ;
     RECT  21.6 37.26 22.572 37.395 ;
     RECT  22.626 37.26 22.95 37.395 ;
     RECT  23.112 37.26 23.76 37.395 ;
     RECT  21.276 37.665 21.708 37.8 ;
     RECT  21.87 37.665 23.274 37.8 ;
     RECT  23.652 37.665 23.76 37.8 ;
     RECT  2.16 37.665 2.268 37.935 ;
     RECT  21.708 37.8 22.572 37.935 ;
     RECT  22.68 37.8 23.76 37.935 ;
     RECT  21.492 38.205 23.76 38.34 ;
     RECT  2.16 38.205 2.268 38.475 ;
     RECT  21.33 38.34 23.382 38.475 ;
     RECT  23.652 38.34 23.76 38.475 ;
     RECT  20.898 38.745 21.762 38.88 ;
     RECT  21.816 38.745 22.248 38.88 ;
     RECT  22.302 38.745 22.95 38.88 ;
     RECT  23.112 38.745 23.76 38.88 ;
     RECT  2.16 38.745 2.268 39.015 ;
     RECT  21.708 38.88 22.14 39.015 ;
     RECT  22.572 38.88 23.76 39.015 ;
     RECT  21.924 39.285 22.356 39.42 ;
     RECT  22.788 39.285 23.76 39.42 ;
     RECT  2.16 39.285 2.268 39.555 ;
     RECT  22.95 39.42 23.598 39.555 ;
     RECT  23.652 39.42 23.76 39.555 ;
     RECT  2.16 39.825 2.268 40.095 ;
     RECT  21.708 39.96 22.14 40.095 ;
     RECT  23.112 39.825 23.76 40.095 ;
     RECT  22.788 40.365 23.76 40.5 ;
     RECT  2.16 40.365 2.268 40.635 ;
     RECT  23.652 40.5 23.76 40.635 ;
     RECT  2.16 40.905 2.268 41.04 ;
     RECT  23.652 40.905 23.76 41.04 ;
    LAYER RVTP ;
     RECT  2.16 2.295 2.268 2.565 ;
     RECT  23.652 2.295 23.76 2.565 ;
     RECT  2.16 2.835 2.268 3.105 ;
     RECT  23.112 2.835 23.76 3.105 ;
     RECT  22.572 3.375 22.896 3.51 ;
     RECT  23.112 3.375 23.436 3.51 ;
     RECT  23.652 3.375 23.76 3.51 ;
     RECT  2.16 3.375 2.268 3.645 ;
     RECT  21.168 3.51 22.032 3.645 ;
     RECT  22.788 3.51 23.76 3.645 ;
     RECT  22.032 3.915 22.464 4.05 ;
     RECT  23.058 3.915 23.598 4.05 ;
     RECT  2.16 3.915 2.268 4.185 ;
     RECT  22.41 4.05 23.598 4.185 ;
     RECT  23.652 3.915 23.76 4.185 ;
     RECT  21.87 4.455 22.302 4.59 ;
     RECT  22.734 4.455 23.058 4.59 ;
     RECT  2.16 4.455 2.268 4.725 ;
     RECT  21.384 4.59 22.68 4.725 ;
     RECT  23.112 4.455 23.76 4.725 ;
     RECT  21.33 4.995 21.762 5.13 ;
     RECT  22.086 4.995 22.41 5.13 ;
     RECT  2.16 4.995 2.268 5.265 ;
     RECT  22.14 5.13 22.464 5.265 ;
     RECT  22.572 4.995 23.76 5.265 ;
     RECT  21.438 5.535 22.302 5.67 ;
     RECT  23.112 5.535 23.76 5.67 ;
     RECT  2.16 5.535 2.268 5.805 ;
     RECT  21.924 5.67 23.004 5.805 ;
     RECT  23.112 5.67 23.544 5.805 ;
     RECT  23.652 5.67 23.76 5.805 ;
     RECT  20.898 6.075 22.194 6.21 ;
     RECT  22.464 6.075 23.76 6.21 ;
     RECT  2.16 6.075 2.268 6.345 ;
     RECT  21.006 6.21 22.14 6.345 ;
     RECT  22.248 6.21 23.544 6.345 ;
     RECT  23.652 6.21 23.76 6.345 ;
     RECT  20.952 6.615 21.924 6.75 ;
     RECT  22.032 6.615 23.544 6.75 ;
     RECT  2.16 6.615 2.268 6.885 ;
     RECT  20.736 6.75 21.168 6.885 ;
     RECT  21.6 6.75 23.544 6.885 ;
     RECT  23.652 6.615 23.76 6.885 ;
     RECT  21.6 7.155 22.032 7.29 ;
     RECT  22.14 7.155 22.734 7.29 ;
     RECT  22.788 7.155 23.76 7.29 ;
     RECT  2.16 7.155 2.268 7.425 ;
     RECT  20.304 7.29 20.736 7.425 ;
     RECT  20.844 7.29 23.598 7.425 ;
     RECT  23.652 7.29 23.76 7.425 ;
     RECT  2.16 7.695 2.538 7.83 ;
     RECT  3.348 7.695 3.78 7.83 ;
     RECT  20.358 7.695 20.79 7.83 ;
     RECT  21.276 7.695 22.14 7.83 ;
     RECT  22.356 7.695 23.76 7.83 ;
     RECT  2.16 7.83 2.268 7.965 ;
     RECT  2.916 7.83 3.618 7.965 ;
     RECT  21.168 7.83 23.76 7.965 ;
     RECT  2.862 8.235 3.132 8.37 ;
     RECT  3.402 8.235 3.672 8.37 ;
     RECT  4.104 8.235 4.536 8.37 ;
     RECT  20.898 8.235 23.328 8.37 ;
     RECT  23.652 8.235 23.76 8.37 ;
     RECT  2.16 8.235 2.268 8.505 ;
     RECT  2.376 8.37 2.916 8.505 ;
     RECT  3.186 8.37 3.456 8.505 ;
     RECT  3.51 8.37 3.78 8.505 ;
     RECT  4.212 8.37 4.644 8.505 ;
     RECT  20.52 8.37 22.788 8.505 ;
     RECT  22.95 8.37 23.76 8.505 ;
     RECT  2.16 8.775 2.268 8.91 ;
     RECT  2.538 8.775 3.24 8.91 ;
     RECT  3.402 8.775 4.698 8.91 ;
     RECT  5.184 8.775 6.264 8.91 ;
     RECT  20.412 8.775 23.166 8.91 ;
     RECT  23.382 8.775 23.76 8.91 ;
     RECT  2.16 8.91 2.538 9.045 ;
     RECT  3.078 8.91 3.51 9.045 ;
     RECT  3.672 8.91 4.374 9.045 ;
     RECT  4.428 8.91 4.86 9.045 ;
     RECT  20.088 8.91 20.628 9.045 ;
     RECT  20.736 8.91 23.76 9.045 ;
     RECT  2.16 9.315 2.268 9.45 ;
     RECT  2.7 9.315 5.346 9.45 ;
     RECT  6.75 9.315 7.83 9.45 ;
     RECT  9.99 9.315 10.26 9.45 ;
     RECT  13.716 9.315 13.986 9.45 ;
     RECT  19.872 9.315 20.142 9.45 ;
     RECT  20.844 9.315 23.598 9.45 ;
     RECT  23.652 9.315 23.76 9.45 ;
     RECT  2.16 9.45 2.538 9.585 ;
     RECT  2.97 9.45 3.24 9.585 ;
     RECT  3.348 9.45 5.292 9.585 ;
     RECT  5.508 9.45 5.94 9.585 ;
     RECT  8.154 9.45 9.234 9.585 ;
     RECT  15.066 9.45 15.336 9.585 ;
     RECT  16.686 9.45 16.956 9.585 ;
     RECT  19.98 9.45 20.628 9.585 ;
     RECT  20.736 9.45 22.14 9.585 ;
     RECT  22.248 9.45 23.76 9.585 ;
     RECT  3.294 9.855 3.564 9.99 ;
     RECT  3.996 9.855 8.748 9.99 ;
     RECT  11.772 9.855 12.042 9.99 ;
     RECT  14.31 9.855 14.58 9.99 ;
     RECT  15.876 9.855 16.146 9.99 ;
     RECT  18.36 9.855 18.63 9.99 ;
     RECT  20.088 9.855 23.76 9.99 ;
     RECT  2.16 9.855 2.538 10.125 ;
     RECT  5.292 9.99 7.452 10.125 ;
     RECT  14.04 9.99 14.31 10.125 ;
     RECT  14.526 9.99 14.796 10.125 ;
     RECT  19.98 9.99 20.412 10.125 ;
     RECT  20.52 9.99 20.844 10.125 ;
     RECT  20.898 9.99 21.924 10.125 ;
     RECT  22.032 9.99 22.734 10.125 ;
     RECT  22.788 9.99 23.058 10.125 ;
     RECT  23.112 9.99 23.544 10.125 ;
     RECT  23.652 9.99 23.76 10.125 ;
     RECT  2.16 10.395 2.538 10.53 ;
     RECT  2.592 10.395 3.888 10.53 ;
     RECT  4.482 10.395 6.642 10.53 ;
     RECT  8.316 10.395 9.396 10.53 ;
     RECT  13.5 10.395 13.77 10.53 ;
     RECT  14.526 10.395 14.796 10.53 ;
     RECT  19.602 10.395 21.114 10.53 ;
     RECT  21.33 10.395 23.112 10.53 ;
     RECT  2.16 10.53 2.268 10.665 ;
     RECT  2.322 10.53 2.592 10.665 ;
     RECT  3.078 10.53 3.348 10.665 ;
     RECT  3.51 10.53 4.806 10.665 ;
     RECT  4.86 10.53 6.372 10.665 ;
     RECT  7.02 10.53 9.18 10.665 ;
     RECT  13.446 10.53 13.986 10.665 ;
     RECT  15.552 10.53 15.822 10.665 ;
     RECT  17.442 10.53 17.712 10.665 ;
     RECT  19.872 10.53 20.196 10.665 ;
     RECT  20.412 10.53 22.032 10.665 ;
     RECT  22.14 10.53 22.842 10.665 ;
     RECT  22.896 10.53 23.166 10.665 ;
     RECT  23.22 10.395 23.76 10.665 ;
     RECT  2.16 10.935 2.97 11.07 ;
     RECT  3.24 10.935 3.942 11.07 ;
     RECT  4.104 10.935 6.534 11.07 ;
     RECT  7.452 10.935 8.532 11.07 ;
     RECT  12.798 10.935 13.068 11.07 ;
     RECT  13.986 10.935 14.256 11.07 ;
     RECT  19.548 10.935 20.574 11.07 ;
     RECT  20.79 10.935 21.222 11.07 ;
     RECT  21.33 10.935 23.112 11.07 ;
     RECT  23.22 10.935 23.76 11.07 ;
     RECT  2.16 11.07 2.538 11.205 ;
     RECT  2.808 11.07 3.78 11.205 ;
     RECT  4.104 11.07 4.536 11.205 ;
     RECT  4.59 11.07 6.75 11.205 ;
     RECT  13.176 11.07 13.716 11.205 ;
     RECT  16.524 11.07 16.794 11.205 ;
     RECT  19.332 11.07 20.196 11.205 ;
     RECT  20.304 11.07 20.736 11.205 ;
     RECT  20.79 11.07 21.654 11.205 ;
     RECT  21.708 11.07 21.978 11.205 ;
     RECT  22.032 11.07 23.004 11.205 ;
     RECT  23.058 11.07 23.49 11.205 ;
     RECT  23.652 11.07 23.76 11.205 ;
     RECT  2.592 11.475 4.428 11.61 ;
     RECT  4.806 11.475 6.966 11.61 ;
     RECT  7.182 11.475 8.262 11.61 ;
     RECT  12.474 11.475 12.744 11.61 ;
     RECT  14.256 11.475 14.526 11.61 ;
     RECT  18.63 11.475 19.062 11.61 ;
     RECT  19.818 11.475 20.952 11.61 ;
     RECT  21.114 11.475 21.546 11.61 ;
     RECT  21.6 11.475 22.842 11.61 ;
     RECT  22.95 11.475 23.22 11.61 ;
     RECT  23.328 11.475 23.76 11.61 ;
     RECT  2.16 11.475 2.268 11.745 ;
     RECT  2.538 11.61 6.534 11.745 ;
     RECT  6.75 11.61 7.83 11.745 ;
     RECT  7.992 11.61 9.072 11.745 ;
     RECT  9.774 11.61 10.044 11.745 ;
     RECT  10.908 11.61 11.178 11.745 ;
     RECT  11.61 11.61 11.88 11.745 ;
     RECT  13.23 11.61 13.5 11.745 ;
     RECT  18.954 11.61 19.386 11.745 ;
     RECT  19.818 11.61 21.222 11.745 ;
     RECT  21.276 11.61 23.112 11.745 ;
     RECT  23.22 11.61 23.76 11.745 ;
     RECT  2.16 12.015 2.268 12.15 ;
     RECT  2.646 12.015 2.916 12.15 ;
     RECT  3.078 12.015 3.348 12.15 ;
     RECT  3.456 12.015 4.32 12.15 ;
     RECT  4.698 12.015 5.13 12.15 ;
     RECT  5.4 12.015 7.56 12.15 ;
     RECT  9.72 12.015 9.99 12.15 ;
     RECT  10.044 12.015 10.314 12.15 ;
     RECT  11.502 12.015 11.772 12.15 ;
     RECT  19.494 12.015 20.034 12.15 ;
     RECT  20.304 12.015 21.168 12.15 ;
     RECT  21.222 12.015 21.492 12.15 ;
     RECT  21.546 12.015 21.87 12.15 ;
     RECT  21.924 12.015 22.356 12.15 ;
     RECT  22.464 12.015 23.166 12.15 ;
     RECT  23.274 12.015 23.544 12.15 ;
     RECT  23.652 12.015 23.76 12.15 ;
     RECT  2.16 12.15 3.51 12.285 ;
     RECT  3.78 12.15 4.212 12.285 ;
     RECT  4.428 12.15 6.588 12.285 ;
     RECT  7.56 12.15 8.64 12.285 ;
     RECT  10.26 12.15 10.53 12.285 ;
     RECT  19.602 12.15 19.926 12.285 ;
     RECT  19.98 12.15 22.68 12.285 ;
     RECT  22.896 12.15 23.328 12.285 ;
     RECT  23.382 12.15 23.76 12.285 ;
     RECT  2.592 12.555 2.862 12.69 ;
     RECT  2.916 12.555 3.348 12.69 ;
     RECT  3.402 12.555 4.752 12.69 ;
     RECT  4.806 12.555 6.426 12.69 ;
     RECT  6.858 12.555 9.018 12.69 ;
     RECT  10.26 12.555 10.53 12.69 ;
     RECT  13.446 12.555 13.986 12.69 ;
     RECT  19.602 12.555 23.76 12.69 ;
     RECT  2.16 12.555 2.538 12.825 ;
     RECT  2.808 12.69 3.078 12.825 ;
     RECT  3.834 12.69 4.104 12.825 ;
     RECT  4.914 12.69 6.102 12.825 ;
     RECT  6.318 12.69 7.398 12.825 ;
     RECT  14.958 12.69 15.228 12.825 ;
     RECT  16.254 12.69 16.524 12.825 ;
     RECT  19.116 12.69 19.656 12.825 ;
     RECT  20.034 12.69 23.112 12.825 ;
     RECT  23.22 12.69 23.76 12.825 ;
     RECT  2.322 13.095 3.996 13.23 ;
     RECT  4.104 13.095 5.184 13.23 ;
     RECT  5.292 13.095 6.372 13.23 ;
     RECT  7.074 13.095 8.154 13.23 ;
     RECT  9.828 13.095 10.098 13.23 ;
     RECT  10.854 13.095 11.124 13.23 ;
     RECT  11.502 13.095 11.772 13.23 ;
     RECT  18.198 13.095 18.63 13.23 ;
     RECT  19.062 13.095 23.76 13.23 ;
     RECT  2.16 13.095 2.268 13.365 ;
     RECT  2.538 13.23 2.808 13.365 ;
     RECT  3.078 13.23 3.348 13.365 ;
     RECT  3.564 13.23 7.668 13.365 ;
     RECT  8.046 13.23 9.666 13.365 ;
     RECT  10.422 13.23 10.692 13.365 ;
     RECT  12.906 13.23 13.176 13.365 ;
     RECT  19.332 13.23 19.872 13.365 ;
     RECT  19.926 13.23 20.25 13.365 ;
     RECT  20.304 13.23 20.628 13.365 ;
     RECT  20.682 13.23 23.76 13.365 ;
     RECT  2.16 13.635 3.672 13.77 ;
     RECT  3.726 13.635 7.398 13.77 ;
     RECT  10.152 13.635 10.422 13.77 ;
     RECT  11.772 13.635 12.042 13.77 ;
     RECT  19.116 13.635 19.548 13.77 ;
     RECT  19.818 13.635 20.142 13.77 ;
     RECT  20.196 13.635 22.464 13.77 ;
     RECT  22.572 13.635 23.274 13.77 ;
     RECT  2.16 13.77 2.268 13.905 ;
     RECT  2.538 13.77 2.808 13.905 ;
     RECT  2.862 13.77 5.076 13.905 ;
     RECT  5.616 13.77 6.048 13.905 ;
     RECT  7.506 13.77 8.586 13.905 ;
     RECT  9.288 13.77 9.558 13.905 ;
     RECT  9.828 13.77 10.098 13.905 ;
     RECT  11.61 13.77 11.88 13.905 ;
     RECT  19.116 13.77 19.656 13.905 ;
     RECT  19.71 13.77 20.142 13.905 ;
     RECT  20.196 13.77 22.626 13.905 ;
     RECT  22.734 13.77 23.598 13.905 ;
     RECT  23.652 13.635 23.76 13.905 ;
     RECT  2.16 14.175 3.078 14.31 ;
     RECT  3.294 14.175 5.508 14.31 ;
     RECT  5.886 14.175 6.156 14.31 ;
     RECT  6.21 14.175 8.37 14.31 ;
     RECT  9.018 14.175 9.288 14.31 ;
     RECT  19.17 14.175 19.818 14.31 ;
     RECT  19.926 14.175 20.466 14.31 ;
     RECT  20.52 14.175 20.952 14.31 ;
     RECT  21.006 14.175 21.546 14.31 ;
     RECT  21.6 14.175 23.112 14.31 ;
     RECT  23.166 14.175 23.598 14.31 ;
     RECT  2.16 14.31 2.808 14.445 ;
     RECT  2.916 14.31 3.78 14.445 ;
     RECT  4.482 14.31 4.914 14.445 ;
     RECT  5.184 14.31 7.344 14.445 ;
     RECT  9.828 14.31 10.098 14.445 ;
     RECT  11.61 14.31 11.88 14.445 ;
     RECT  18.63 14.31 18.954 14.445 ;
     RECT  19.062 14.31 22.896 14.445 ;
     RECT  22.95 14.31 23.544 14.445 ;
     RECT  23.652 14.175 23.76 14.445 ;
     RECT  2.16 14.715 2.268 14.85 ;
     RECT  2.538 14.715 5.832 14.85 ;
     RECT  6.048 14.715 7.398 14.85 ;
     RECT  8.046 14.715 9.126 14.85 ;
     RECT  10.098 14.715 10.368 14.85 ;
     RECT  10.8 14.715 11.07 14.85 ;
     RECT  12.312 14.715 12.582 14.85 ;
     RECT  18.846 14.715 20.358 14.85 ;
     RECT  20.466 14.715 22.572 14.85 ;
     RECT  22.626 14.715 23.76 14.85 ;
     RECT  2.16 14.85 3.942 14.985 ;
     RECT  3.996 14.85 4.86 14.985 ;
     RECT  5.076 14.85 7.344 14.985 ;
     RECT  11.07 14.85 11.34 14.985 ;
     RECT  12.528 14.85 12.798 14.985 ;
     RECT  13.176 14.85 13.446 14.985 ;
     RECT  16.146 14.85 16.416 14.985 ;
     RECT  18.846 14.85 20.142 14.985 ;
     RECT  20.25 14.85 21.762 14.985 ;
     RECT  21.87 14.85 23.436 14.985 ;
     RECT  23.652 14.85 23.76 14.985 ;
     RECT  2.16 15.255 2.808 15.39 ;
     RECT  2.97 15.255 5.184 15.39 ;
     RECT  5.346 15.255 7.506 15.39 ;
     RECT  7.668 15.255 8.748 15.39 ;
     RECT  10.152 15.255 10.422 15.39 ;
     RECT  13.176 15.255 13.446 15.39 ;
     RECT  17.712 15.255 17.982 15.39 ;
     RECT  18.738 15.255 20.142 15.39 ;
     RECT  20.25 15.255 23.76 15.39 ;
     RECT  2.16 15.39 3.51 15.525 ;
     RECT  3.726 15.39 6.75 15.525 ;
     RECT  7.776 15.39 8.964 15.525 ;
     RECT  13.122 15.39 13.392 15.525 ;
     RECT  14.526 15.39 14.796 15.525 ;
     RECT  18.36 15.39 18.9 15.525 ;
     RECT  19.008 15.39 19.764 15.525 ;
     RECT  19.926 15.39 22.572 15.525 ;
     RECT  22.788 15.39 23.76 15.525 ;
     RECT  2.16 15.795 2.268 15.93 ;
     RECT  2.538 15.795 3.078 15.93 ;
     RECT  3.726 15.795 5.346 15.93 ;
     RECT  5.67 15.795 8.91 15.93 ;
     RECT  12.528 15.795 12.798 15.93 ;
     RECT  14.094 15.795 14.364 15.93 ;
     RECT  18.468 15.795 18.792 15.93 ;
     RECT  18.846 15.795 19.71 15.93 ;
     RECT  19.764 15.795 20.088 15.93 ;
     RECT  20.142 15.795 23.544 15.93 ;
     RECT  23.652 15.795 23.76 15.93 ;
     RECT  2.16 15.93 3.078 16.065 ;
     RECT  3.24 15.795 3.51 16.065 ;
     RECT  3.78 15.93 4.644 16.065 ;
     RECT  4.914 15.93 5.994 16.065 ;
     RECT  6.048 15.93 7.128 16.065 ;
     RECT  14.094 15.93 14.634 16.065 ;
     RECT  18.576 15.93 19.44 16.065 ;
     RECT  19.656 15.93 20.196 16.065 ;
     RECT  20.25 15.93 21.924 16.065 ;
     RECT  22.032 15.93 22.842 16.065 ;
     RECT  22.896 15.93 23.328 16.065 ;
     RECT  23.382 15.93 23.76 16.065 ;
     RECT  2.16 16.335 3.078 16.47 ;
     RECT  3.132 16.335 3.564 16.47 ;
     RECT  3.726 16.335 5.778 16.47 ;
     RECT  6.75 16.335 7.83 16.47 ;
     RECT  8.046 16.335 9.126 16.47 ;
     RECT  14.31 16.335 14.58 16.47 ;
     RECT  15.714 16.335 15.984 16.47 ;
     RECT  18.684 16.335 19.224 16.47 ;
     RECT  19.278 16.335 19.602 16.47 ;
     RECT  19.656 16.335 19.98 16.47 ;
     RECT  20.034 16.335 20.79 16.47 ;
     RECT  20.898 16.335 21.438 16.47 ;
     RECT  21.492 16.335 22.518 16.47 ;
     RECT  22.572 16.335 23.166 16.47 ;
     RECT  2.16 16.47 2.538 16.605 ;
     RECT  2.916 16.47 6.372 16.605 ;
     RECT  6.966 16.47 8.046 16.605 ;
     RECT  12.042 16.47 12.312 16.605 ;
     RECT  12.96 16.47 13.23 16.605 ;
     RECT  18.576 16.47 18.9 16.605 ;
     RECT  18.954 16.47 19.818 16.605 ;
     RECT  19.872 16.47 20.412 16.605 ;
     RECT  20.466 16.47 23.112 16.605 ;
     RECT  23.22 16.335 23.76 16.605 ;
     RECT  2.16 16.875 5.184 17.01 ;
     RECT  5.4 16.875 7.83 17.01 ;
     RECT  15.066 16.875 15.336 17.01 ;
     RECT  16.038 16.875 16.308 17.01 ;
     RECT  16.686 16.875 16.956 17.01 ;
     RECT  18.414 16.875 20.574 17.01 ;
     RECT  20.682 16.875 23.544 17.01 ;
     RECT  23.652 16.875 23.76 17.01 ;
     RECT  2.16 17.01 3.24 17.145 ;
     RECT  3.294 17.01 3.996 17.145 ;
     RECT  4.05 17.01 4.914 17.145 ;
     RECT  4.968 17.01 5.4 17.145 ;
     RECT  5.832 17.01 7.992 17.145 ;
     RECT  8.046 17.01 9.126 17.145 ;
     RECT  9.882 17.01 10.152 17.145 ;
     RECT  10.206 17.01 10.476 17.145 ;
     RECT  13.122 17.01 13.392 17.145 ;
     RECT  14.904 17.01 15.174 17.145 ;
     RECT  15.39 17.01 15.66 17.145 ;
     RECT  18.414 17.01 19.278 17.145 ;
     RECT  19.494 17.01 20.034 17.145 ;
     RECT  20.088 17.01 20.52 17.145 ;
     RECT  20.574 17.01 22.464 17.145 ;
     RECT  22.572 17.01 23.112 17.145 ;
     RECT  23.22 17.01 23.76 17.145 ;
     RECT  2.16 17.415 3.942 17.55 ;
     RECT  4.104 17.415 5.616 17.55 ;
     RECT  5.67 17.415 7.83 17.55 ;
     RECT  8.208 17.415 9.288 17.55 ;
     RECT  10.962 17.415 11.232 17.55 ;
     RECT  11.286 17.415 11.556 17.55 ;
     RECT  13.932 17.415 14.202 17.55 ;
     RECT  18.09 17.415 19.278 17.55 ;
     RECT  19.332 17.415 19.656 17.55 ;
     RECT  19.71 17.415 22.842 17.55 ;
     RECT  22.95 17.415 23.76 17.55 ;
     RECT  2.16 17.55 3.348 17.685 ;
     RECT  3.402 17.55 3.672 17.685 ;
     RECT  3.78 17.55 4.212 17.685 ;
     RECT  4.536 17.55 5.616 17.685 ;
     RECT  5.67 17.55 6.318 17.685 ;
     RECT  6.696 17.55 8.856 17.685 ;
     RECT  8.91 17.55 9.18 17.685 ;
     RECT  11.826 17.55 12.096 17.685 ;
     RECT  18.198 17.55 19.062 17.685 ;
     RECT  19.224 17.55 22.842 17.685 ;
     RECT  22.896 17.55 23.328 17.685 ;
     RECT  23.382 17.55 23.76 17.685 ;
     RECT  2.16 17.955 2.268 18.09 ;
     RECT  2.538 17.955 2.808 18.09 ;
     RECT  3.024 17.955 3.726 18.09 ;
     RECT  3.942 17.955 5.886 18.09 ;
     RECT  6.966 17.955 9.126 18.09 ;
     RECT  9.774 17.955 10.044 18.09 ;
     RECT  10.692 17.955 10.962 18.09 ;
     RECT  11.772 17.955 12.042 18.09 ;
     RECT  18.414 17.955 20.25 18.09 ;
     RECT  20.304 17.955 22.95 18.09 ;
     RECT  23.058 17.955 23.49 18.09 ;
     RECT  2.16 18.09 4.266 18.225 ;
     RECT  4.536 18.09 5.616 18.225 ;
     RECT  5.778 18.09 7.938 18.225 ;
     RECT  11.448 18.09 11.718 18.225 ;
     RECT  18.36 18.09 18.684 18.225 ;
     RECT  18.738 18.09 19.494 18.225 ;
     RECT  19.548 18.09 20.088 18.225 ;
     RECT  20.142 18.09 23.22 18.225 ;
     RECT  23.328 18.09 23.598 18.225 ;
     RECT  23.652 17.955 23.76 18.225 ;
     RECT  2.16 18.495 2.808 18.63 ;
     RECT  2.862 18.495 4.806 18.63 ;
     RECT  5.67 18.495 6.858 18.63 ;
     RECT  9.504 18.495 9.774 18.63 ;
     RECT  11.664 18.495 11.934 18.63 ;
     RECT  12.15 18.495 12.42 18.63 ;
     RECT  18.522 18.495 19.386 18.63 ;
     RECT  19.44 18.495 20.412 18.63 ;
     RECT  20.466 18.495 23.004 18.63 ;
     RECT  23.112 18.495 23.544 18.63 ;
     RECT  23.652 18.495 23.76 18.63 ;
     RECT  2.16 18.63 3.672 18.765 ;
     RECT  3.942 18.63 5.022 18.765 ;
     RECT  5.4 18.63 6.75 18.765 ;
     RECT  6.858 18.63 7.938 18.765 ;
     RECT  8.046 18.63 8.316 18.765 ;
     RECT  8.586 18.63 8.856 18.765 ;
     RECT  10.53 18.63 10.8 18.765 ;
     RECT  17.82 18.63 22.68 18.765 ;
     RECT  22.788 18.63 23.76 18.765 ;
     RECT  2.16 19.035 4.374 19.17 ;
     RECT  4.59 19.035 5.022 19.17 ;
     RECT  5.67 19.035 7.83 19.17 ;
     RECT  8.046 19.035 9.396 19.17 ;
     RECT  16.038 19.035 16.308 19.17 ;
     RECT  18.252 19.035 19.764 19.17 ;
     RECT  19.872 19.035 23.544 19.17 ;
     RECT  23.652 19.035 23.76 19.17 ;
     RECT  2.16 19.17 2.538 19.305 ;
     RECT  2.808 19.17 3.78 19.305 ;
     RECT  3.942 19.17 4.374 19.305 ;
     RECT  5.022 19.17 5.454 19.305 ;
     RECT  6.966 19.17 8.046 19.305 ;
     RECT  10.206 19.17 10.476 19.305 ;
     RECT  10.584 19.17 10.854 19.305 ;
     RECT  15.12 19.17 15.39 19.305 ;
     RECT  18.252 19.17 18.576 19.305 ;
     RECT  18.684 19.17 19.008 19.305 ;
     RECT  19.17 19.17 23.112 19.305 ;
     RECT  23.22 19.17 23.76 19.305 ;
     RECT  2.16 19.575 2.538 19.71 ;
     RECT  2.808 19.575 5.562 19.71 ;
     RECT  6.75 19.575 8.91 19.71 ;
     RECT  12.744 19.575 13.014 19.71 ;
     RECT  13.122 19.575 13.392 19.71 ;
     RECT  17.982 19.575 18.306 19.71 ;
     RECT  18.63 19.575 23.598 19.71 ;
     RECT  23.652 19.575 23.76 19.71 ;
     RECT  2.16 19.71 3.78 19.845 ;
     RECT  4.212 19.71 4.482 19.845 ;
     RECT  5.076 19.71 6.588 19.845 ;
     RECT  8.316 19.71 9.396 19.845 ;
     RECT  11.826 19.71 12.096 19.845 ;
     RECT  14.202 19.71 14.472 19.845 ;
     RECT  17.874 19.71 18.414 19.845 ;
     RECT  18.792 19.71 20.844 19.845 ;
     RECT  20.952 19.71 23.76 19.845 ;
     RECT  2.16 20.115 3.24 20.25 ;
     RECT  3.294 20.115 7.398 20.25 ;
     RECT  7.614 20.115 8.694 20.25 ;
     RECT  12.258 20.115 12.798 20.25 ;
     RECT  13.554 20.115 13.824 20.25 ;
     RECT  15.282 20.115 15.552 20.25 ;
     RECT  18.036 20.115 18.576 20.25 ;
     RECT  18.63 20.115 21.006 20.25 ;
     RECT  21.06 20.115 23.76 20.25 ;
     RECT  2.16 20.25 3.672 20.385 ;
     RECT  3.78 20.25 4.212 20.385 ;
     RECT  4.428 20.25 5.508 20.385 ;
     RECT  6.912 20.25 7.992 20.385 ;
     RECT  12.366 20.25 12.636 20.385 ;
     RECT  16.2 20.25 16.47 20.385 ;
     RECT  17.658 20.25 17.982 20.385 ;
     RECT  18.09 20.25 18.846 20.385 ;
     RECT  19.116 20.25 19.44 20.385 ;
     RECT  19.548 20.25 20.628 20.385 ;
     RECT  20.736 20.25 23.76 20.385 ;
     RECT  2.16 20.655 6.534 20.79 ;
     RECT  6.912 20.655 9.072 20.79 ;
     RECT  9.882 20.655 10.152 20.79 ;
     RECT  11.664 20.655 11.934 20.79 ;
     RECT  14.958 20.655 15.228 20.79 ;
     RECT  18.306 20.655 19.71 20.79 ;
     RECT  19.818 20.655 20.142 20.79 ;
     RECT  20.25 20.655 20.79 20.79 ;
     RECT  20.844 20.655 23.76 20.79 ;
     RECT  2.16 20.79 3.672 20.925 ;
     RECT  3.888 20.79 6.48 20.925 ;
     RECT  9.018 20.79 9.288 20.925 ;
     RECT  10.422 20.79 10.962 20.925 ;
     RECT  13.824 20.79 14.094 20.925 ;
     RECT  18.198 20.79 19.494 20.925 ;
     RECT  19.602 20.79 19.926 20.925 ;
     RECT  19.98 20.79 23.436 20.925 ;
     RECT  23.652 20.79 23.76 20.925 ;
     RECT  2.16 21.195 2.538 21.33 ;
     RECT  2.592 21.195 4.536 21.33 ;
     RECT  4.644 21.195 5.076 21.33 ;
     RECT  5.13 21.195 5.562 21.33 ;
     RECT  5.886 21.195 6.966 21.33 ;
     RECT  7.992 21.195 9.072 21.33 ;
     RECT  11.124 21.195 11.394 21.33 ;
     RECT  16.2 21.195 16.47 21.33 ;
     RECT  17.982 21.195 18.63 21.33 ;
     RECT  18.684 21.195 20.52 21.33 ;
     RECT  20.574 21.195 21.114 21.33 ;
     RECT  21.222 21.195 23.598 21.33 ;
     RECT  23.652 21.195 23.76 21.33 ;
     RECT  2.16 21.33 3.402 21.465 ;
     RECT  3.564 21.33 3.834 21.465 ;
     RECT  3.888 21.33 5.4 21.465 ;
     RECT  5.724 21.33 6.372 21.465 ;
     RECT  6.48 21.33 7.56 21.465 ;
     RECT  11.718 21.33 11.988 21.465 ;
     RECT  15.39 21.33 15.66 21.465 ;
     RECT  17.442 21.33 17.712 21.465 ;
     RECT  18.036 21.33 18.9 21.465 ;
     RECT  18.954 21.33 19.494 21.465 ;
     RECT  19.548 21.33 20.088 21.465 ;
     RECT  20.142 21.33 21.762 21.465 ;
     RECT  21.816 21.33 23.112 21.465 ;
     RECT  23.22 21.33 23.76 21.465 ;
     RECT  2.16 21.735 3.078 21.87 ;
     RECT  3.294 21.735 7.398 21.87 ;
     RECT  11.016 21.735 11.286 21.87 ;
     RECT  15.174 21.735 15.444 21.87 ;
     RECT  18.522 21.735 19.71 21.87 ;
     RECT  19.764 21.735 21.492 21.87 ;
     RECT  21.546 21.735 23.112 21.87 ;
     RECT  23.22 21.735 23.76 21.87 ;
     RECT  2.16 21.87 3.672 22.005 ;
     RECT  3.726 21.87 3.996 22.005 ;
     RECT  4.158 21.87 5.238 22.005 ;
     RECT  5.508 21.87 6.588 22.005 ;
     RECT  6.912 21.87 7.992 22.005 ;
     RECT  8.208 21.87 9.558 22.005 ;
     RECT  13.23 21.87 13.5 22.005 ;
     RECT  14.256 21.87 14.526 22.005 ;
     RECT  14.85 21.87 15.12 22.005 ;
     RECT  15.66 21.87 15.93 22.005 ;
     RECT  18.144 21.87 23.76 22.005 ;
     RECT  2.16 22.275 4.644 22.41 ;
     RECT  4.806 22.275 5.238 22.41 ;
     RECT  5.67 22.275 8.91 22.41 ;
     RECT  9.558 22.275 9.828 22.41 ;
     RECT  15.822 22.275 16.092 22.41 ;
     RECT  17.874 22.275 18.198 22.41 ;
     RECT  18.414 22.275 20.358 22.41 ;
     RECT  20.52 22.275 22.032 22.41 ;
     RECT  22.14 22.275 23.112 22.41 ;
     RECT  23.22 22.275 23.76 22.41 ;
     RECT  2.16 22.41 3.672 22.545 ;
     RECT  3.888 22.41 6.48 22.545 ;
     RECT  7.83 22.41 8.91 22.545 ;
     RECT  12.258 22.41 12.528 22.545 ;
     RECT  13.554 22.41 13.824 22.545 ;
     RECT  18.306 22.41 18.63 22.545 ;
     RECT  18.792 22.41 19.656 22.545 ;
     RECT  19.764 22.41 22.302 22.545 ;
     RECT  22.356 22.41 23.76 22.545 ;
     RECT  2.16 22.815 3.942 22.95 ;
     RECT  3.996 22.815 4.266 22.95 ;
     RECT  4.482 22.815 6.75 22.95 ;
     RECT  7.02 22.815 8.208 22.95 ;
     RECT  11.664 22.815 11.934 22.95 ;
     RECT  18.36 22.815 18.684 22.95 ;
     RECT  18.738 22.815 19.278 22.95 ;
     RECT  19.332 22.815 20.952 22.95 ;
     RECT  21.06 22.815 23.598 22.95 ;
     RECT  23.652 22.815 23.76 22.95 ;
     RECT  2.16 22.95 2.268 23.085 ;
     RECT  2.538 22.95 3.078 23.085 ;
     RECT  3.294 22.95 7.83 23.085 ;
     RECT  8.262 22.95 9.342 23.085 ;
     RECT  11.61 22.95 11.88 23.085 ;
     RECT  12.528 22.95 12.798 23.085 ;
     RECT  14.04 22.95 14.31 23.085 ;
     RECT  15.768 22.95 16.308 23.085 ;
     RECT  18.306 22.95 18.846 23.085 ;
     RECT  18.9 22.95 19.224 23.085 ;
     RECT  19.332 22.95 20.088 23.085 ;
     RECT  20.142 22.95 23.76 23.085 ;
     RECT  2.16 23.355 3.672 23.49 ;
     RECT  3.78 23.355 6.372 23.49 ;
     RECT  7.506 23.355 8.586 23.49 ;
     RECT  10.854 23.355 11.124 23.49 ;
     RECT  12.528 23.355 12.798 23.49 ;
     RECT  18.144 23.355 19.548 23.49 ;
     RECT  19.818 23.355 23.76 23.49 ;
     RECT  2.16 23.49 2.268 23.625 ;
     RECT  2.808 23.49 3.618 23.625 ;
     RECT  3.996 23.49 5.94 23.625 ;
     RECT  6.21 23.49 7.29 23.625 ;
     RECT  7.83 23.49 8.91 23.625 ;
     RECT  14.58 23.49 14.85 23.625 ;
     RECT  16.848 23.49 17.388 23.625 ;
     RECT  17.928 23.49 19.224 23.625 ;
     RECT  19.332 23.49 19.764 23.625 ;
     RECT  19.818 23.49 22.95 23.625 ;
     RECT  23.22 23.49 23.76 23.625 ;
     RECT  2.16 23.895 3.78 24.03 ;
     RECT  3.996 23.895 6.588 24.03 ;
     RECT  7.668 23.895 8.748 24.03 ;
     RECT  10.692 23.895 10.962 24.03 ;
     RECT  13.77 23.895 14.31 24.03 ;
     RECT  18.252 23.895 18.576 24.03 ;
     RECT  18.63 23.895 19.062 24.03 ;
     RECT  19.116 23.895 19.764 24.03 ;
     RECT  19.818 23.895 21.06 24.03 ;
     RECT  21.168 23.895 22.302 24.03 ;
     RECT  22.356 23.895 23.76 24.03 ;
     RECT  2.16 24.03 2.538 24.165 ;
     RECT  2.808 24.03 3.51 24.165 ;
     RECT  4.212 24.03 4.644 24.165 ;
     RECT  5.292 24.03 7.452 24.165 ;
     RECT  7.992 24.03 8.262 24.165 ;
     RECT  12.042 24.03 12.312 24.165 ;
     RECT  16.416 24.03 16.686 24.165 ;
     RECT  17.82 24.03 18.36 24.165 ;
     RECT  18.468 24.03 18.792 24.165 ;
     RECT  18.846 24.03 19.386 24.165 ;
     RECT  19.494 24.03 19.818 24.165 ;
     RECT  19.872 24.03 20.736 24.165 ;
     RECT  20.79 24.03 22.086 24.165 ;
     RECT  22.14 24.03 23.112 24.165 ;
     RECT  23.166 24.03 23.598 24.165 ;
     RECT  23.652 24.03 23.76 24.165 ;
     RECT  2.16 24.435 6.966 24.57 ;
     RECT  8.046 24.435 9.126 24.57 ;
     RECT  13.392 24.435 13.662 24.57 ;
     RECT  17.874 24.435 18.144 24.57 ;
     RECT  18.36 24.435 20.088 24.57 ;
     RECT  20.142 24.435 22.626 24.57 ;
     RECT  22.68 24.435 23.544 24.57 ;
     RECT  23.652 24.435 23.76 24.57 ;
     RECT  2.16 24.57 4.482 24.705 ;
     RECT  4.752 24.57 7.344 24.705 ;
     RECT  14.148 24.57 14.688 24.705 ;
     RECT  15.39 24.57 15.66 24.705 ;
     RECT  16.092 24.57 16.362 24.705 ;
     RECT  17.658 24.57 18.522 24.705 ;
     RECT  18.576 24.57 19.008 24.705 ;
     RECT  19.062 24.57 19.602 24.705 ;
     RECT  19.656 24.57 20.52 24.705 ;
     RECT  20.574 24.57 23.166 24.705 ;
     RECT  23.22 24.57 23.76 24.705 ;
     RECT  2.16 24.975 3.672 25.11 ;
     RECT  3.888 24.975 5.832 25.11 ;
     RECT  6.426 24.975 7.506 25.11 ;
     RECT  8.316 24.975 9.396 25.11 ;
     RECT  13.716 24.975 13.986 25.11 ;
     RECT  14.526 24.975 14.796 25.11 ;
     RECT  15.336 24.975 15.606 25.11 ;
     RECT  18.036 24.975 18.468 25.11 ;
     RECT  18.792 24.975 20.412 25.11 ;
     RECT  20.466 24.975 22.194 25.11 ;
     RECT  22.248 24.975 23.76 25.11 ;
     RECT  2.16 25.11 4.752 25.245 ;
     RECT  4.86 25.11 5.292 25.245 ;
     RECT  6.048 25.11 7.128 25.245 ;
     RECT  9.828 25.11 10.098 25.245 ;
     RECT  18.252 25.11 18.576 25.245 ;
     RECT  18.792 25.11 23.544 25.245 ;
     RECT  23.652 25.11 23.76 25.245 ;
     RECT  2.16 25.515 5.184 25.65 ;
     RECT  5.94 25.515 6.588 25.65 ;
     RECT  6.75 25.515 7.83 25.65 ;
     RECT  7.938 25.515 9.018 25.65 ;
     RECT  12.312 25.515 12.582 25.65 ;
     RECT  15.066 25.515 15.336 25.65 ;
     RECT  16.956 25.515 17.226 25.65 ;
     RECT  18.684 25.515 19.872 25.65 ;
     RECT  19.926 25.515 23.22 25.65 ;
     RECT  23.382 25.515 23.76 25.65 ;
     RECT  2.16 25.65 2.808 25.785 ;
     RECT  3.078 25.65 4.05 25.785 ;
     RECT  4.104 25.65 5.184 25.785 ;
     RECT  5.238 25.65 6.318 25.785 ;
     RECT  6.48 25.65 7.56 25.785 ;
     RECT  14.796 25.65 15.066 25.785 ;
     RECT  15.714 25.65 15.984 25.785 ;
     RECT  17.712 25.65 18.036 25.785 ;
     RECT  18.306 25.515 18.576 25.785 ;
     RECT  18.63 25.65 18.954 25.785 ;
     RECT  19.008 25.65 20.196 25.785 ;
     RECT  20.304 25.65 23.544 25.785 ;
     RECT  23.652 25.65 23.76 25.785 ;
     RECT  2.16 26.055 3.348 26.19 ;
     RECT  3.51 26.055 3.78 26.19 ;
     RECT  4.266 26.055 5.562 26.19 ;
     RECT  5.886 26.055 8.046 26.19 ;
     RECT  17.01 26.055 17.55 26.19 ;
     RECT  18.306 26.055 19.926 26.19 ;
     RECT  20.034 26.055 21.924 26.19 ;
     RECT  22.086 26.055 23.76 26.19 ;
     RECT  2.16 26.19 2.268 26.325 ;
     RECT  2.538 26.19 4.374 26.325 ;
     RECT  4.536 26.19 5.616 26.325 ;
     RECT  5.886 26.19 9.126 26.325 ;
     RECT  16.038 26.19 16.308 26.325 ;
     RECT  17.55 26.19 17.82 26.325 ;
     RECT  18.252 26.19 18.792 26.325 ;
     RECT  18.846 26.19 19.386 26.325 ;
     RECT  19.44 26.19 22.788 26.325 ;
     RECT  22.842 26.19 23.112 26.325 ;
     RECT  23.22 26.19 23.76 26.325 ;
     RECT  2.16 26.595 2.97 26.73 ;
     RECT  3.186 26.595 4.482 26.73 ;
     RECT  5.508 26.595 6.588 26.73 ;
     RECT  7.02 26.595 9.18 26.73 ;
     RECT  9.234 26.595 9.504 26.73 ;
     RECT  10.8 26.595 11.07 26.73 ;
     RECT  12.636 26.595 12.906 26.73 ;
     RECT  14.85 26.595 15.12 26.73 ;
     RECT  17.874 26.595 19.008 26.73 ;
     RECT  19.062 26.595 19.386 26.73 ;
     RECT  19.494 26.595 19.818 26.73 ;
     RECT  20.034 26.595 20.466 26.73 ;
     RECT  20.52 26.595 22.14 26.73 ;
     RECT  22.194 26.595 23.166 26.73 ;
     RECT  23.22 26.595 23.76 26.73 ;
     RECT  2.16 26.73 2.268 26.865 ;
     RECT  2.484 26.73 2.754 26.865 ;
     RECT  2.916 26.73 3.78 26.865 ;
     RECT  3.996 26.73 5.508 26.865 ;
     RECT  5.724 26.73 7.884 26.865 ;
     RECT  13.932 26.73 14.202 26.865 ;
     RECT  16.794 26.73 17.064 26.865 ;
     RECT  17.874 26.73 18.144 26.865 ;
     RECT  18.306 26.73 22.734 26.865 ;
     RECT  22.896 26.73 23.598 26.865 ;
     RECT  23.652 26.73 23.76 26.865 ;
     RECT  2.16 27.135 2.268 27.27 ;
     RECT  2.538 27.135 3.78 27.27 ;
     RECT  3.996 27.135 5.508 27.27 ;
     RECT  5.994 27.135 7.182 27.27 ;
     RECT  8.316 27.135 9.396 27.27 ;
     RECT  12.96 27.135 13.23 27.27 ;
     RECT  18.414 27.135 18.846 27.27 ;
     RECT  18.954 27.135 21.384 27.27 ;
     RECT  21.492 27.135 23.436 27.27 ;
     RECT  23.652 27.135 23.76 27.27 ;
     RECT  2.16 27.27 5.292 27.405 ;
     RECT  5.67 27.27 6.75 27.405 ;
     RECT  6.966 27.27 9.126 27.405 ;
     RECT  9.72 27.27 9.99 27.405 ;
     RECT  11.286 27.27 11.556 27.405 ;
     RECT  16.038 27.27 16.308 27.405 ;
     RECT  18.576 27.27 19.44 27.405 ;
     RECT  19.764 27.27 20.628 27.405 ;
     RECT  20.736 27.27 23.76 27.405 ;
     RECT  2.16 27.675 3.24 27.81 ;
     RECT  3.888 27.675 4.32 27.81 ;
     RECT  4.806 27.675 5.67 27.81 ;
     RECT  5.994 27.675 6.21 27.81 ;
     RECT  14.904 27.675 15.174 27.81 ;
     RECT  18.63 27.675 18.954 27.81 ;
     RECT  19.062 27.675 20.25 27.81 ;
     RECT  20.358 27.675 23.112 27.81 ;
     RECT  2.16 27.81 5.454 27.945 ;
     RECT  5.616 27.81 6.696 27.945 ;
     RECT  7.02 27.81 8.1 27.945 ;
     RECT  10.908 27.81 11.178 27.945 ;
     RECT  13.068 27.81 13.338 27.945 ;
     RECT  17.442 27.81 17.712 27.945 ;
     RECT  19.116 27.81 19.656 27.945 ;
     RECT  19.71 27.81 20.142 27.945 ;
     RECT  20.25 27.81 20.682 27.945 ;
     RECT  20.736 27.81 21.6 27.945 ;
     RECT  21.708 27.81 22.518 27.945 ;
     RECT  22.734 27.81 23.166 27.945 ;
     RECT  23.22 27.675 23.76 27.945 ;
     RECT  2.16 28.215 3.24 28.35 ;
     RECT  3.348 28.215 3.78 28.35 ;
     RECT  3.942 28.215 8.694 28.35 ;
     RECT  11.178 28.215 11.448 28.35 ;
     RECT  15.498 28.215 15.768 28.35 ;
     RECT  17.874 28.215 18.144 28.35 ;
     RECT  19.008 28.215 19.656 28.35 ;
     RECT  19.71 28.215 21.114 28.35 ;
     RECT  21.222 28.215 21.978 28.35 ;
     RECT  22.086 28.215 23.76 28.35 ;
     RECT  2.16 28.35 2.268 28.485 ;
     RECT  2.322 28.35 7.668 28.485 ;
     RECT  8.046 28.35 9.396 28.485 ;
     RECT  15.552 28.35 15.822 28.485 ;
     RECT  16.254 28.35 16.524 28.485 ;
     RECT  16.794 28.35 17.064 28.485 ;
     RECT  18.954 28.35 19.278 28.485 ;
     RECT  19.44 28.35 22.356 28.485 ;
     RECT  22.464 28.35 23.166 28.485 ;
     RECT  23.22 28.35 23.76 28.485 ;
     RECT  2.16 28.755 4.59 28.89 ;
     RECT  5.832 28.755 6.912 28.89 ;
     RECT  7.722 28.755 8.154 28.89 ;
     RECT  13.068 28.755 13.338 28.89 ;
     RECT  18.846 28.755 19.656 28.89 ;
     RECT  19.71 28.755 20.142 28.89 ;
     RECT  20.196 28.755 20.79 28.89 ;
     RECT  20.844 28.755 21.384 28.89 ;
     RECT  21.438 28.755 23.76 28.89 ;
     RECT  2.16 28.89 3.78 29.025 ;
     RECT  3.888 28.89 4.59 29.025 ;
     RECT  5.022 28.89 5.454 29.025 ;
     RECT  6.75 28.89 7.83 29.025 ;
     RECT  14.796 28.89 15.336 29.025 ;
     RECT  15.66 28.89 16.2 29.025 ;
     RECT  18.576 28.89 18.9 29.025 ;
     RECT  18.954 28.89 19.278 29.025 ;
     RECT  19.44 28.89 23.328 29.025 ;
     RECT  23.382 28.89 23.76 29.025 ;
     RECT  2.16 29.295 3.672 29.43 ;
     RECT  3.78 29.295 4.212 29.43 ;
     RECT  4.266 29.295 5.346 29.43 ;
     RECT  7.938 29.295 9.018 29.43 ;
     RECT  13.338 29.295 13.608 29.43 ;
     RECT  14.202 29.295 14.472 29.43 ;
     RECT  14.688 29.295 14.958 29.43 ;
     RECT  19.116 29.295 20.844 29.43 ;
     RECT  20.898 29.295 23.058 29.43 ;
     RECT  23.22 29.295 23.76 29.43 ;
     RECT  2.16 29.43 5.022 29.565 ;
     RECT  5.616 29.43 6.696 29.565 ;
     RECT  6.804 29.43 8.964 29.565 ;
     RECT  14.418 29.43 14.688 29.565 ;
     RECT  14.904 29.43 15.174 29.565 ;
     RECT  18.09 29.43 18.36 29.565 ;
     RECT  19.008 29.43 21.276 29.565 ;
     RECT  21.33 29.43 22.842 29.565 ;
     RECT  22.95 29.43 23.76 29.565 ;
     RECT  2.16 29.835 2.538 29.97 ;
     RECT  2.7 29.835 2.97 29.97 ;
     RECT  3.24 29.835 3.51 29.97 ;
     RECT  3.942 29.835 4.374 29.97 ;
     RECT  5.292 29.835 6.372 29.97 ;
     RECT  8.1 29.835 9.18 29.97 ;
     RECT  11.61 29.835 11.88 29.97 ;
     RECT  17.388 29.835 17.658 29.97 ;
     RECT  19.764 29.835 21.816 29.97 ;
     RECT  21.924 29.835 23.22 29.97 ;
     RECT  23.328 29.835 23.598 29.97 ;
     RECT  23.652 29.835 23.76 29.97 ;
     RECT  2.16 29.97 2.808 30.105 ;
     RECT  3.456 29.97 3.888 30.105 ;
     RECT  4.536 29.97 6.696 30.105 ;
     RECT  6.966 29.835 8.046 30.105 ;
     RECT  8.154 29.97 9.234 30.105 ;
     RECT  10.746 29.97 11.016 30.105 ;
     RECT  14.364 29.97 14.634 30.105 ;
     RECT  15.498 29.97 15.768 30.105 ;
     RECT  16.308 29.97 16.578 30.105 ;
     RECT  19.386 29.835 19.71 30.105 ;
     RECT  19.764 29.97 20.088 30.105 ;
     RECT  20.142 29.97 21.654 30.105 ;
     RECT  21.708 29.97 23.76 30.105 ;
     RECT  2.16 30.375 3.51 30.51 ;
     RECT  3.888 30.375 4.158 30.51 ;
     RECT  4.32 30.375 4.752 30.51 ;
     RECT  5.67 30.375 6.75 30.51 ;
     RECT  7.02 30.375 8.1 30.51 ;
     RECT  12.636 30.375 12.906 30.51 ;
     RECT  13.5 30.375 13.77 30.51 ;
     RECT  19.17 30.375 19.71 30.51 ;
     RECT  19.872 30.375 20.844 30.51 ;
     RECT  20.898 30.375 22.086 30.51 ;
     RECT  22.14 30.375 23.544 30.51 ;
     RECT  2.16 30.51 2.268 30.645 ;
     RECT  2.322 30.51 2.592 30.645 ;
     RECT  2.7 30.51 3.132 30.645 ;
     RECT  3.402 30.51 3.672 30.645 ;
     RECT  3.834 30.51 4.266 30.645 ;
     RECT  4.536 30.51 6.156 30.645 ;
     RECT  7.722 30.51 8.91 30.645 ;
     RECT  13.824 30.51 14.094 30.645 ;
     RECT  14.904 30.51 15.174 30.645 ;
     RECT  17.928 30.51 18.36 30.645 ;
     RECT  19.386 30.51 22.896 30.645 ;
     RECT  22.95 30.51 23.22 30.645 ;
     RECT  23.652 30.375 23.76 30.645 ;
     RECT  2.16 30.915 3.672 31.05 ;
     RECT  4.05 30.915 4.482 31.05 ;
     RECT  5.4 30.915 6.48 31.05 ;
     RECT  7.938 30.915 9.018 31.05 ;
     RECT  12.852 30.915 13.122 31.05 ;
     RECT  13.23 30.915 13.5 31.05 ;
     RECT  19.44 30.915 20.898 31.05 ;
     RECT  21.006 30.915 21.33 31.05 ;
     RECT  21.384 30.915 21.654 31.05 ;
     RECT  21.816 30.915 22.788 31.05 ;
     RECT  22.95 30.915 23.76 31.05 ;
     RECT  2.16 31.05 2.808 31.185 ;
     RECT  3.24 31.05 4.104 31.185 ;
     RECT  4.428 31.05 7.668 31.185 ;
     RECT  8.046 31.05 9.126 31.185 ;
     RECT  10.368 31.05 10.638 31.185 ;
     RECT  12.582 31.05 13.122 31.185 ;
     RECT  14.742 31.05 15.012 31.185 ;
     RECT  19.278 31.05 20.682 31.185 ;
     RECT  20.736 31.05 21.708 31.185 ;
     RECT  21.762 31.05 22.734 31.185 ;
     RECT  22.842 31.05 23.112 31.185 ;
     RECT  23.22 31.05 23.76 31.185 ;
     RECT  2.16 31.455 2.97 31.59 ;
     RECT  3.51 31.455 6.534 31.59 ;
     RECT  8.046 31.455 9.126 31.59 ;
     RECT  12.636 31.455 12.906 31.59 ;
     RECT  13.608 31.455 13.878 31.59 ;
     RECT  19.548 31.455 19.872 31.59 ;
     RECT  20.142 31.455 20.682 31.59 ;
     RECT  20.736 31.455 21.492 31.59 ;
     RECT  21.654 31.455 23.76 31.59 ;
     RECT  2.16 31.59 3.24 31.725 ;
     RECT  3.402 31.59 3.834 31.725 ;
     RECT  3.996 31.59 7.236 31.725 ;
     RECT  12.69 31.59 12.96 31.725 ;
     RECT  13.77 31.59 14.31 31.725 ;
     RECT  14.796 31.59 15.066 31.725 ;
     RECT  19.656 31.59 22.194 31.725 ;
     RECT  22.248 31.59 23.004 31.725 ;
     RECT  23.112 31.59 23.544 31.725 ;
     RECT  23.652 31.59 23.76 31.725 ;
     RECT  2.16 31.995 2.268 32.13 ;
     RECT  2.862 31.995 3.402 32.13 ;
     RECT  3.51 31.995 4.914 32.13 ;
     RECT  5.184 31.995 8.424 32.13 ;
     RECT  12.528 31.995 12.798 32.13 ;
     RECT  12.96 31.995 13.23 32.13 ;
     RECT  19.926 31.995 20.682 32.13 ;
     RECT  20.736 31.995 21.762 32.13 ;
     RECT  21.816 31.995 22.788 32.13 ;
     RECT  22.896 31.995 23.76 32.13 ;
     RECT  2.16 32.13 2.538 32.265 ;
     RECT  2.646 32.13 3.078 32.265 ;
     RECT  3.402 32.13 5.562 32.265 ;
     RECT  5.778 32.13 7.938 32.265 ;
     RECT  10.26 32.13 10.53 32.265 ;
     RECT  11.88 32.13 12.15 32.265 ;
     RECT  13.932 32.13 14.202 32.265 ;
     RECT  15.66 32.13 15.93 32.265 ;
     RECT  19.926 32.13 20.466 32.265 ;
     RECT  20.52 32.13 22.518 32.265 ;
     RECT  22.572 32.13 23.274 32.265 ;
     RECT  23.382 32.13 23.76 32.265 ;
     RECT  2.16 32.535 2.538 32.67 ;
     RECT  3.024 32.535 3.294 32.67 ;
     RECT  4.32 32.535 6.48 32.67 ;
     RECT  6.966 32.535 8.046 32.67 ;
     RECT  10.962 32.535 11.232 32.67 ;
     RECT  13.392 32.535 13.662 32.67 ;
     RECT  13.878 32.535 14.148 32.67 ;
     RECT  19.818 32.535 20.79 32.67 ;
     RECT  20.898 32.535 21.222 32.67 ;
     RECT  21.33 32.535 21.6 32.67 ;
     RECT  21.654 32.535 23.76 32.67 ;
     RECT  2.16 32.67 2.97 32.805 ;
     RECT  3.024 32.67 3.456 32.805 ;
     RECT  3.618 32.67 4.05 32.805 ;
     RECT  4.482 32.67 4.914 32.805 ;
     RECT  7.182 32.67 8.262 32.805 ;
     RECT  13.014 32.67 13.284 32.805 ;
     RECT  20.25 32.67 23.328 32.805 ;
     RECT  23.382 32.67 23.76 32.805 ;
     RECT  2.16 33.075 2.808 33.21 ;
     RECT  3.24 33.075 4.32 33.21 ;
     RECT  4.428 33.075 5.508 33.21 ;
     RECT  6.048 33.075 7.128 33.21 ;
     RECT  8.208 33.075 9.288 33.21 ;
     RECT  12.312 33.075 12.582 33.21 ;
     RECT  13.284 33.075 13.554 33.21 ;
     RECT  18.144 33.075 18.414 33.21 ;
     RECT  20.25 33.075 23.544 33.21 ;
     RECT  23.652 33.075 23.76 33.21 ;
     RECT  2.16 33.21 2.268 33.345 ;
     RECT  2.376 33.21 2.646 33.345 ;
     RECT  2.916 33.21 3.456 33.345 ;
     RECT  3.51 33.21 4.374 33.345 ;
     RECT  4.806 33.21 5.238 33.345 ;
     RECT  5.508 33.21 6.588 33.345 ;
     RECT  6.966 33.21 8.046 33.345 ;
     RECT  8.586 33.21 8.856 33.345 ;
     RECT  11.286 33.21 11.556 33.345 ;
     RECT  20.412 33.21 22.41 33.345 ;
     RECT  22.464 33.21 23.166 33.345 ;
     RECT  23.22 33.21 23.76 33.345 ;
     RECT  2.16 33.615 3.672 33.75 ;
     RECT  3.726 33.615 5.238 33.75 ;
     RECT  6.966 33.615 9.126 33.75 ;
     RECT  9.18 33.615 9.45 33.75 ;
     RECT  14.526 33.615 15.066 33.75 ;
     RECT  19.224 33.615 19.656 33.75 ;
     RECT  20.412 33.615 21.384 33.75 ;
     RECT  21.438 33.615 23.274 33.75 ;
     RECT  23.382 33.615 23.76 33.75 ;
     RECT  2.16 33.75 2.808 33.885 ;
     RECT  3.024 33.75 3.726 33.885 ;
     RECT  4.158 33.75 4.59 33.885 ;
     RECT  5.346 33.75 5.616 33.885 ;
     RECT  6.696 33.75 8.856 33.885 ;
     RECT  9.396 33.75 9.666 33.885 ;
     RECT  12.042 33.75 12.312 33.885 ;
     RECT  12.852 33.75 13.122 33.885 ;
     RECT  13.662 33.75 13.932 33.885 ;
     RECT  20.79 33.75 23.166 33.885 ;
     RECT  23.22 33.75 23.76 33.885 ;
     RECT  2.16 34.155 2.538 34.29 ;
     RECT  2.97 34.155 3.672 34.29 ;
     RECT  4.482 34.155 4.914 34.29 ;
     RECT  5.616 34.155 6.696 34.29 ;
     RECT  7.938 34.155 9.018 34.29 ;
     RECT  12.312 34.155 12.582 34.29 ;
     RECT  20.25 34.155 20.844 34.29 ;
     RECT  20.952 34.155 23.166 34.29 ;
     RECT  23.22 34.155 23.76 34.29 ;
     RECT  2.16 34.29 3.564 34.425 ;
     RECT  3.78 34.29 5.292 34.425 ;
     RECT  20.304 34.29 23.76 34.425 ;
     RECT  2.16 34.695 2.538 34.83 ;
     RECT  3.024 34.695 3.294 34.83 ;
     RECT  4.914 34.695 5.994 34.83 ;
     RECT  20.412 34.695 20.736 34.83 ;
     RECT  21.06 34.695 22.194 34.83 ;
     RECT  22.356 34.695 23.76 34.83 ;
     RECT  2.16 34.83 2.268 34.965 ;
     RECT  2.646 34.83 2.916 34.965 ;
     RECT  3.078 34.83 3.51 34.965 ;
     RECT  3.618 34.695 4.05 34.965 ;
     RECT  4.212 34.695 4.644 34.965 ;
     RECT  20.574 34.83 22.086 34.965 ;
     RECT  22.194 34.83 23.76 34.965 ;
     RECT  3.51 35.235 4.374 35.37 ;
     RECT  20.79 35.235 22.464 35.37 ;
     RECT  22.518 35.235 22.788 35.37 ;
     RECT  22.95 35.235 23.49 35.37 ;
     RECT  2.16 35.235 2.538 35.505 ;
     RECT  2.754 35.37 3.024 35.505 ;
     RECT  3.672 35.37 4.104 35.505 ;
     RECT  21.33 35.37 23.382 35.505 ;
     RECT  23.652 35.235 23.76 35.505 ;
     RECT  3.24 35.775 3.51 35.91 ;
     RECT  20.52 35.775 21.06 35.91 ;
     RECT  21.384 35.775 23.76 35.91 ;
     RECT  2.16 35.775 2.268 36.045 ;
     RECT  3.132 35.91 3.402 36.045 ;
     RECT  20.79 35.91 22.626 36.045 ;
     RECT  22.68 35.91 23.76 36.045 ;
     RECT  3.078 36.315 3.78 36.45 ;
     RECT  20.682 36.315 23.166 36.45 ;
     RECT  23.22 36.315 23.76 36.45 ;
     RECT  2.16 36.315 2.268 36.585 ;
     RECT  21.114 36.45 22.95 36.585 ;
     RECT  23.112 36.45 23.544 36.585 ;
     RECT  23.652 36.45 23.76 36.585 ;
     RECT  2.16 36.855 2.268 37.125 ;
     RECT  20.952 36.855 23.544 37.125 ;
     RECT  23.652 36.855 23.76 37.125 ;
     RECT  20.898 37.395 21.33 37.53 ;
     RECT  21.6 37.395 22.572 37.53 ;
     RECT  22.626 37.395 22.95 37.53 ;
     RECT  23.112 37.395 23.76 37.53 ;
     RECT  2.16 37.395 2.268 37.665 ;
     RECT  21.276 37.53 21.708 37.665 ;
     RECT  21.87 37.53 23.274 37.665 ;
     RECT  23.652 37.53 23.76 37.665 ;
     RECT  21.708 37.935 22.572 38.07 ;
     RECT  22.68 37.935 23.76 38.07 ;
     RECT  2.16 37.935 2.268 38.205 ;
     RECT  21.492 38.07 23.76 38.205 ;
     RECT  21.33 38.475 23.382 38.61 ;
     RECT  23.652 38.475 23.76 38.61 ;
     RECT  2.16 38.475 2.268 38.745 ;
     RECT  20.898 38.61 21.762 38.745 ;
     RECT  21.816 38.61 22.248 38.745 ;
     RECT  22.302 38.61 22.95 38.745 ;
     RECT  23.112 38.61 23.76 38.745 ;
     RECT  21.708 39.015 22.14 39.15 ;
     RECT  22.572 39.015 23.76 39.15 ;
     RECT  2.16 39.015 2.268 39.285 ;
     RECT  21.924 39.15 22.356 39.285 ;
     RECT  22.788 39.15 23.76 39.285 ;
     RECT  22.95 39.555 23.598 39.69 ;
     RECT  23.652 39.555 23.76 39.69 ;
     RECT  2.16 39.555 2.268 39.825 ;
     RECT  23.112 39.69 23.76 39.825 ;
     RECT  21.708 40.095 22.14 40.23 ;
     RECT  23.112 40.095 23.76 40.23 ;
     RECT  2.16 40.095 2.268 40.365 ;
     RECT  22.788 40.23 23.76 40.365 ;
     RECT  2.16 40.635 2.268 40.905 ;
     RECT  23.652 40.635 23.76 40.905 ;
    LAYER M1 ;
     RECT  2.16 2.151 23.76 41.049 ;
    LAYER M2 ;
     RECT  2.16 2.151 23.76 41.049 ;
    LAYER M3 ;
     RECT  2.415 2.143 2.505 2.413 ;
     RECT  7.815 2.143 7.905 2.413 ;
     RECT  13.215 2.143 13.305 2.413 ;
     RECT  18.615 2.143 18.705 2.413 ;
     RECT  2.415 2.413 2.697 40.787 ;
     RECT  7.815 2.413 8.097 40.787 ;
     RECT  13.215 2.413 13.497 40.787 ;
     RECT  18.615 2.413 18.897 40.787 ;
     RECT  2.415 40.787 2.505 41.057 ;
     RECT  7.815 40.787 7.905 41.057 ;
     RECT  13.215 40.787 13.305 41.057 ;
     RECT  18.615 40.787 18.705 41.057 ;
    LAYER M4 ;
     RECT  2.408 2.148 2.512 41.052 ;
     RECT  2.512 2.418 2.704 40.782 ;
     RECT  7.808 2.148 7.912 41.052 ;
     RECT  7.912 2.418 8.104 40.782 ;
     RECT  13.208 2.148 13.312 41.052 ;
     RECT  13.312 2.418 13.504 40.782 ;
     RECT  18.608 2.148 18.712 41.052 ;
     RECT  18.712 2.418 18.904 40.782 ;
    LAYER M5 ;
     RECT  2.4 2.137 2.52 2.151 ;
     RECT  7.8 2.137 7.92 2.151 ;
     RECT  13.2 2.137 13.32 2.151 ;
     RECT  18.6 2.137 18.72 2.151 ;
     RECT  2.4 2.151 2.712 41.049 ;
     RECT  7.8 2.151 8.112 41.049 ;
     RECT  13.2 2.151 13.512 41.049 ;
     RECT  18.6 2.151 18.912 41.049 ;
     RECT  2.4 41.049 2.52 41.063 ;
     RECT  7.8 41.049 7.92 41.063 ;
     RECT  13.2 41.049 13.32 41.063 ;
     RECT  18.6 41.049 18.72 41.063 ;
  END
END ot_smh_static_stage256
END LIBRARY
